VERSION 5.8 ;
BUSBITCHARS "[]" ;
DIVIDERCHAR "/" ;
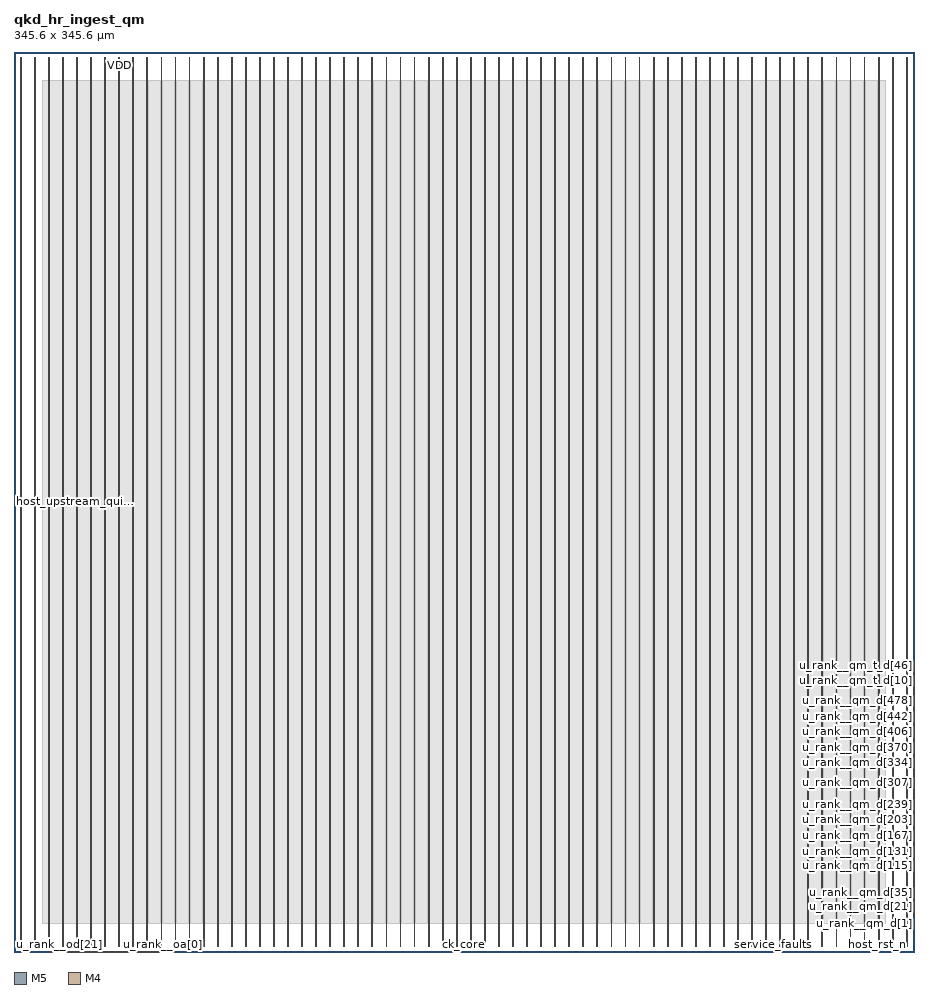
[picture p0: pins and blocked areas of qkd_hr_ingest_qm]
MACRO qkd_hr_ingest_qm
  CLASS BLOCK ;
  ORIGIN 0 0 ;
  FOREIGN qkd_hr_ingest_qm 0 0 ;
  SIZE 345.6 BY 345.6 ;
  SYMMETRY X Y ;
  PIN ck_core
    DIRECTION INPUT ;
    USE CLOCK ;
    PORT
      LAYER M5 ;
        RECT 172.800 0.000 172.824 0.192 ;
    END
  END ck_core
  PIN ck_host
    DIRECTION INPUT ;
    USE CLOCK ;
    PORT
      LAYER M5 ;
        RECT 177.120 0.000 177.144 0.192 ;
    END
  END ck_host
  PIN ck_ingest
    DIRECTION INPUT ;
    USE CLOCK ;
    PORT
      LAYER M5 ;
        RECT 181.440 0.000 181.464 0.192 ;
    END
  END ck_ingest
  PIN host_rst_n
    DIRECTION INPUT ;
    USE SIGNAL ;
    PORT
      LAYER M5 ;
        RECT 331.680 0.000 331.704 0.192 ;
    END
  END host_rst_n
  PIN host_upstream_quiet_core
    DIRECTION OUTPUT ;
    USE SIGNAL ;
    PORT
      LAYER M4 ;
        RECT 0.000 172.800 0.192 172.824 ;
    END
  END host_upstream_quiet_core
  PIN host_upstream_quiet_host
    DIRECTION OUTPUT ;
    USE SIGNAL ;
    PORT
      LAYER M4 ;
        RECT 0.000 172.944 0.192 172.968 ;
    END
  END host_upstream_quiet_host
  PIN host_upstream_quiet_ingest
    DIRECTION OUTPUT ;
    USE SIGNAL ;
    PORT
      LAYER M4 ;
        RECT 0.000 173.136 0.192 173.160 ;
    END
  END host_upstream_quiet_ingest
  PIN service_faults
    DIRECTION OUTPUT ;
    USE SIGNAL ;
    PORT
      LAYER M5 ;
        RECT 291.552 0.000 291.576 0.192 ;
    END
  END service_faults
  PIN u_rank__oa[0]
    DIRECTION OUTPUT ;
    USE SIGNAL ;
    PORT
      LAYER M5 ;
        RECT 57.072 0.000 57.096 0.192 ;
    END
  END u_rank__oa[0]
  PIN u_rank__oa[10]
    DIRECTION OUTPUT ;
    USE SIGNAL ;
    PORT
      LAYER M5 ;
        RECT 58.752 0.000 58.776 0.192 ;
    END
  END u_rank__oa[10]
  PIN u_rank__oa[11]
    DIRECTION OUTPUT ;
    USE SIGNAL ;
    PORT
      LAYER M5 ;
        RECT 58.896 0.000 58.920 0.192 ;
    END
  END u_rank__oa[11]
  PIN u_rank__oa[12]
    DIRECTION OUTPUT ;
    USE SIGNAL ;
    PORT
      LAYER M5 ;
        RECT 59.040 0.000 59.064 0.192 ;
    END
  END u_rank__oa[12]
  PIN u_rank__oa[13]
    DIRECTION OUTPUT ;
    USE SIGNAL ;
    PORT
      LAYER M5 ;
        RECT 59.232 0.000 59.256 0.192 ;
    END
  END u_rank__oa[13]
  PIN u_rank__oa[14]
    DIRECTION OUTPUT ;
    USE SIGNAL ;
    PORT
      LAYER M5 ;
        RECT 59.376 0.000 59.400 0.192 ;
    END
  END u_rank__oa[14]
  PIN u_rank__oa[15]
    DIRECTION OUTPUT ;
    USE SIGNAL ;
    PORT
      LAYER M5 ;
        RECT 59.568 0.000 59.592 0.192 ;
    END
  END u_rank__oa[15]
  PIN u_rank__oa[16]
    DIRECTION OUTPUT ;
    USE SIGNAL ;
    PORT
      LAYER M5 ;
        RECT 59.712 0.000 59.736 0.192 ;
    END
  END u_rank__oa[16]
  PIN u_rank__oa[17]
    DIRECTION OUTPUT ;
    USE SIGNAL ;
    PORT
      LAYER M5 ;
        RECT 59.904 0.000 59.928 0.192 ;
    END
  END u_rank__oa[17]
  PIN u_rank__oa[18]
    DIRECTION OUTPUT ;
    USE SIGNAL ;
    PORT
      LAYER M5 ;
        RECT 60.048 0.000 60.072 0.192 ;
    END
  END u_rank__oa[18]
  PIN u_rank__oa[19]
    DIRECTION OUTPUT ;
    USE SIGNAL ;
    PORT
      LAYER M5 ;
        RECT 60.240 0.000 60.264 0.192 ;
    END
  END u_rank__oa[19]
  PIN u_rank__oa[1]
    DIRECTION OUTPUT ;
    USE SIGNAL ;
    PORT
      LAYER M5 ;
        RECT 57.216 0.000 57.240 0.192 ;
    END
  END u_rank__oa[1]
  PIN u_rank__oa[20]
    DIRECTION OUTPUT ;
    USE SIGNAL ;
    PORT
      LAYER M5 ;
        RECT 60.384 0.000 60.408 0.192 ;
    END
  END u_rank__oa[20]
  PIN u_rank__oa[21]
    DIRECTION OUTPUT ;
    USE SIGNAL ;
    PORT
      LAYER M5 ;
        RECT 60.576 0.000 60.600 0.192 ;
    END
  END u_rank__oa[21]
  PIN u_rank__oa[22]
    DIRECTION OUTPUT ;
    USE SIGNAL ;
    PORT
      LAYER M5 ;
        RECT 60.720 0.000 60.744 0.192 ;
    END
  END u_rank__oa[22]
  PIN u_rank__oa[23]
    DIRECTION OUTPUT ;
    USE SIGNAL ;
    PORT
      LAYER M5 ;
        RECT 60.912 0.000 60.936 0.192 ;
    END
  END u_rank__oa[23]
  PIN u_rank__oa[24]
    DIRECTION OUTPUT ;
    USE SIGNAL ;
    PORT
      LAYER M5 ;
        RECT 61.056 0.000 61.080 0.192 ;
    END
  END u_rank__oa[24]
  PIN u_rank__oa[25]
    DIRECTION OUTPUT ;
    USE SIGNAL ;
    PORT
      LAYER M5 ;
        RECT 61.248 0.000 61.272 0.192 ;
    END
  END u_rank__oa[25]
  PIN u_rank__oa[26]
    DIRECTION OUTPUT ;
    USE SIGNAL ;
    PORT
      LAYER M5 ;
        RECT 61.392 0.000 61.416 0.192 ;
    END
  END u_rank__oa[26]
  PIN u_rank__oa[27]
    DIRECTION OUTPUT ;
    USE SIGNAL ;
    PORT
      LAYER M5 ;
        RECT 61.584 0.000 61.608 0.192 ;
    END
  END u_rank__oa[27]
  PIN u_rank__oa[28]
    DIRECTION OUTPUT ;
    USE SIGNAL ;
    PORT
      LAYER M5 ;
        RECT 62.304 0.000 62.328 0.192 ;
    END
  END u_rank__oa[28]
  PIN u_rank__oa[29]
    DIRECTION OUTPUT ;
    USE SIGNAL ;
    PORT
      LAYER M5 ;
        RECT 62.352 0.000 62.376 0.192 ;
    END
  END u_rank__oa[29]
  PIN u_rank__oa[2]
    DIRECTION OUTPUT ;
    USE SIGNAL ;
    PORT
      LAYER M5 ;
        RECT 57.408 0.000 57.432 0.192 ;
    END
  END u_rank__oa[2]
  PIN u_rank__oa[30]
    DIRECTION OUTPUT ;
    USE SIGNAL ;
    PORT
      LAYER M5 ;
        RECT 62.400 0.000 62.424 0.192 ;
    END
  END u_rank__oa[30]
  PIN u_rank__oa[31]
    DIRECTION OUTPUT ;
    USE SIGNAL ;
    PORT
      LAYER M5 ;
        RECT 62.448 0.000 62.472 0.192 ;
    END
  END u_rank__oa[31]
  PIN u_rank__oa[3]
    DIRECTION OUTPUT ;
    USE SIGNAL ;
    PORT
      LAYER M5 ;
        RECT 57.552 0.000 57.576 0.192 ;
    END
  END u_rank__oa[3]
  PIN u_rank__oa[4]
    DIRECTION OUTPUT ;
    USE SIGNAL ;
    PORT
      LAYER M5 ;
        RECT 57.744 0.000 57.768 0.192 ;
    END
  END u_rank__oa[4]
  PIN u_rank__oa[5]
    DIRECTION OUTPUT ;
    USE SIGNAL ;
    PORT
      LAYER M5 ;
        RECT 57.888 0.000 57.912 0.192 ;
    END
  END u_rank__oa[5]
  PIN u_rank__oa[6]
    DIRECTION OUTPUT ;
    USE SIGNAL ;
    PORT
      LAYER M5 ;
        RECT 58.080 0.000 58.104 0.192 ;
    END
  END u_rank__oa[6]
  PIN u_rank__oa[7]
    DIRECTION OUTPUT ;
    USE SIGNAL ;
    PORT
      LAYER M5 ;
        RECT 58.224 0.000 58.248 0.192 ;
    END
  END u_rank__oa[7]
  PIN u_rank__oa[8]
    DIRECTION OUTPUT ;
    USE SIGNAL ;
    PORT
      LAYER M5 ;
        RECT 58.416 0.000 58.440 0.192 ;
    END
  END u_rank__oa[8]
  PIN u_rank__oa[9]
    DIRECTION OUTPUT ;
    USE SIGNAL ;
    PORT
      LAYER M5 ;
        RECT 58.560 0.000 58.584 0.192 ;
    END
  END u_rank__oa[9]
  PIN u_rank__ocr
    DIRECTION INPUT ;
    USE SIGNAL ;
    PORT
      LAYER M5 ;
        RECT 56.928 0.000 56.952 0.192 ;
    END
  END u_rank__ocr
  PIN u_rank__od[0]
    DIRECTION OUTPUT ;
    USE SIGNAL ;
    PORT
      LAYER M5 ;
        RECT 13.872 0.000 13.896 0.192 ;
    END
  END u_rank__od[0]
  PIN u_rank__od[100]
    DIRECTION OUTPUT ;
    USE SIGNAL ;
    PORT
      LAYER M5 ;
        RECT 30.576 0.000 30.600 0.192 ;
    END
  END u_rank__od[100]
  PIN u_rank__od[101]
    DIRECTION OUTPUT ;
    USE SIGNAL ;
    PORT
      LAYER M5 ;
        RECT 30.720 0.000 30.744 0.192 ;
    END
  END u_rank__od[101]
  PIN u_rank__od[102]
    DIRECTION OUTPUT ;
    USE SIGNAL ;
    PORT
      LAYER M5 ;
        RECT 30.912 0.000 30.936 0.192 ;
    END
  END u_rank__od[102]
  PIN u_rank__od[103]
    DIRECTION OUTPUT ;
    USE SIGNAL ;
    PORT
      LAYER M5 ;
        RECT 31.056 0.000 31.080 0.192 ;
    END
  END u_rank__od[103]
  PIN u_rank__od[104]
    DIRECTION OUTPUT ;
    USE SIGNAL ;
    PORT
      LAYER M5 ;
        RECT 31.248 0.000 31.272 0.192 ;
    END
  END u_rank__od[104]
  PIN u_rank__od[105]
    DIRECTION OUTPUT ;
    USE SIGNAL ;
    PORT
      LAYER M5 ;
        RECT 31.392 0.000 31.416 0.192 ;
    END
  END u_rank__od[105]
  PIN u_rank__od[106]
    DIRECTION OUTPUT ;
    USE SIGNAL ;
    PORT
      LAYER M5 ;
        RECT 31.584 0.000 31.608 0.192 ;
    END
  END u_rank__od[106]
  PIN u_rank__od[107]
    DIRECTION OUTPUT ;
    USE SIGNAL ;
    PORT
      LAYER M5 ;
        RECT 31.728 0.000 31.752 0.192 ;
    END
  END u_rank__od[107]
  PIN u_rank__od[108]
    DIRECTION OUTPUT ;
    USE SIGNAL ;
    PORT
      LAYER M5 ;
        RECT 31.872 0.000 31.896 0.192 ;
    END
  END u_rank__od[108]
  PIN u_rank__od[109]
    DIRECTION OUTPUT ;
    USE SIGNAL ;
    PORT
      LAYER M5 ;
        RECT 32.064 0.000 32.088 0.192 ;
    END
  END u_rank__od[109]
  PIN u_rank__od[10]
    DIRECTION OUTPUT ;
    USE SIGNAL ;
    PORT
      LAYER M5 ;
        RECT 15.552 0.000 15.576 0.192 ;
    END
  END u_rank__od[10]
  PIN u_rank__od[110]
    DIRECTION OUTPUT ;
    USE SIGNAL ;
    PORT
      LAYER M5 ;
        RECT 32.208 0.000 32.232 0.192 ;
    END
  END u_rank__od[110]
  PIN u_rank__od[111]
    DIRECTION OUTPUT ;
    USE SIGNAL ;
    PORT
      LAYER M5 ;
        RECT 32.400 0.000 32.424 0.192 ;
    END
  END u_rank__od[111]
  PIN u_rank__od[112]
    DIRECTION OUTPUT ;
    USE SIGNAL ;
    PORT
      LAYER M5 ;
        RECT 32.544 0.000 32.568 0.192 ;
    END
  END u_rank__od[112]
  PIN u_rank__od[113]
    DIRECTION OUTPUT ;
    USE SIGNAL ;
    PORT
      LAYER M5 ;
        RECT 32.736 0.000 32.760 0.192 ;
    END
  END u_rank__od[113]
  PIN u_rank__od[114]
    DIRECTION OUTPUT ;
    USE SIGNAL ;
    PORT
      LAYER M5 ;
        RECT 32.880 0.000 32.904 0.192 ;
    END
  END u_rank__od[114]
  PIN u_rank__od[115]
    DIRECTION OUTPUT ;
    USE SIGNAL ;
    PORT
      LAYER M5 ;
        RECT 33.072 0.000 33.096 0.192 ;
    END
  END u_rank__od[115]
  PIN u_rank__od[116]
    DIRECTION OUTPUT ;
    USE SIGNAL ;
    PORT
      LAYER M5 ;
        RECT 33.216 0.000 33.240 0.192 ;
    END
  END u_rank__od[116]
  PIN u_rank__od[117]
    DIRECTION OUTPUT ;
    USE SIGNAL ;
    PORT
      LAYER M5 ;
        RECT 33.408 0.000 33.432 0.192 ;
    END
  END u_rank__od[117]
  PIN u_rank__od[118]
    DIRECTION OUTPUT ;
    USE SIGNAL ;
    PORT
      LAYER M5 ;
        RECT 33.552 0.000 33.576 0.192 ;
    END
  END u_rank__od[118]
  PIN u_rank__od[119]
    DIRECTION OUTPUT ;
    USE SIGNAL ;
    PORT
      LAYER M5 ;
        RECT 33.744 0.000 33.768 0.192 ;
    END
  END u_rank__od[119]
  PIN u_rank__od[11]
    DIRECTION OUTPUT ;
    USE SIGNAL ;
    PORT
      LAYER M5 ;
        RECT 15.744 0.000 15.768 0.192 ;
    END
  END u_rank__od[11]
  PIN u_rank__od[120]
    DIRECTION OUTPUT ;
    USE SIGNAL ;
    PORT
      LAYER M5 ;
        RECT 33.888 0.000 33.912 0.192 ;
    END
  END u_rank__od[120]
  PIN u_rank__od[121]
    DIRECTION OUTPUT ;
    USE SIGNAL ;
    PORT
      LAYER M5 ;
        RECT 34.080 0.000 34.104 0.192 ;
    END
  END u_rank__od[121]
  PIN u_rank__od[122]
    DIRECTION OUTPUT ;
    USE SIGNAL ;
    PORT
      LAYER M5 ;
        RECT 34.224 0.000 34.248 0.192 ;
    END
  END u_rank__od[122]
  PIN u_rank__od[123]
    DIRECTION OUTPUT ;
    USE SIGNAL ;
    PORT
      LAYER M5 ;
        RECT 34.416 0.000 34.440 0.192 ;
    END
  END u_rank__od[123]
  PIN u_rank__od[124]
    DIRECTION OUTPUT ;
    USE SIGNAL ;
    PORT
      LAYER M5 ;
        RECT 34.560 0.000 34.584 0.192 ;
    END
  END u_rank__od[124]
  PIN u_rank__od[125]
    DIRECTION OUTPUT ;
    USE SIGNAL ;
    PORT
      LAYER M5 ;
        RECT 35.328 0.000 35.352 0.192 ;
    END
  END u_rank__od[125]
  PIN u_rank__od[126]
    DIRECTION OUTPUT ;
    USE SIGNAL ;
    PORT
      LAYER M5 ;
        RECT 35.376 0.000 35.400 0.192 ;
    END
  END u_rank__od[126]
  PIN u_rank__od[127]
    DIRECTION OUTPUT ;
    USE SIGNAL ;
    PORT
      LAYER M5 ;
        RECT 35.424 0.000 35.448 0.192 ;
    END
  END u_rank__od[127]
  PIN u_rank__od[128]
    DIRECTION OUTPUT ;
    USE SIGNAL ;
    PORT
      LAYER M5 ;
        RECT 35.472 0.000 35.496 0.192 ;
    END
  END u_rank__od[128]
  PIN u_rank__od[129]
    DIRECTION OUTPUT ;
    USE SIGNAL ;
    PORT
      LAYER M5 ;
        RECT 35.520 0.000 35.544 0.192 ;
    END
  END u_rank__od[129]
  PIN u_rank__od[12]
    DIRECTION OUTPUT ;
    USE SIGNAL ;
    PORT
      LAYER M5 ;
        RECT 15.888 0.000 15.912 0.192 ;
    END
  END u_rank__od[12]
  PIN u_rank__od[130]
    DIRECTION OUTPUT ;
    USE SIGNAL ;
    PORT
      LAYER M5 ;
        RECT 35.568 0.000 35.592 0.192 ;
    END
  END u_rank__od[130]
  PIN u_rank__od[131]
    DIRECTION OUTPUT ;
    USE SIGNAL ;
    PORT
      LAYER M5 ;
        RECT 35.712 0.000 35.736 0.192 ;
    END
  END u_rank__od[131]
  PIN u_rank__od[132]
    DIRECTION OUTPUT ;
    USE SIGNAL ;
    PORT
      LAYER M5 ;
        RECT 35.904 0.000 35.928 0.192 ;
    END
  END u_rank__od[132]
  PIN u_rank__od[133]
    DIRECTION OUTPUT ;
    USE SIGNAL ;
    PORT
      LAYER M5 ;
        RECT 36.048 0.000 36.072 0.192 ;
    END
  END u_rank__od[133]
  PIN u_rank__od[134]
    DIRECTION OUTPUT ;
    USE SIGNAL ;
    PORT
      LAYER M5 ;
        RECT 36.240 0.000 36.264 0.192 ;
    END
  END u_rank__od[134]
  PIN u_rank__od[135]
    DIRECTION OUTPUT ;
    USE SIGNAL ;
    PORT
      LAYER M5 ;
        RECT 36.384 0.000 36.408 0.192 ;
    END
  END u_rank__od[135]
  PIN u_rank__od[136]
    DIRECTION OUTPUT ;
    USE SIGNAL ;
    PORT
      LAYER M5 ;
        RECT 36.576 0.000 36.600 0.192 ;
    END
  END u_rank__od[136]
  PIN u_rank__od[137]
    DIRECTION OUTPUT ;
    USE SIGNAL ;
    PORT
      LAYER M5 ;
        RECT 36.720 0.000 36.744 0.192 ;
    END
  END u_rank__od[137]
  PIN u_rank__od[138]
    DIRECTION OUTPUT ;
    USE SIGNAL ;
    PORT
      LAYER M5 ;
        RECT 36.912 0.000 36.936 0.192 ;
    END
  END u_rank__od[138]
  PIN u_rank__od[139]
    DIRECTION OUTPUT ;
    USE SIGNAL ;
    PORT
      LAYER M5 ;
        RECT 37.056 0.000 37.080 0.192 ;
    END
  END u_rank__od[139]
  PIN u_rank__od[13]
    DIRECTION OUTPUT ;
    USE SIGNAL ;
    PORT
      LAYER M5 ;
        RECT 16.080 0.000 16.104 0.192 ;
    END
  END u_rank__od[13]
  PIN u_rank__od[140]
    DIRECTION OUTPUT ;
    USE SIGNAL ;
    PORT
      LAYER M5 ;
        RECT 37.248 0.000 37.272 0.192 ;
    END
  END u_rank__od[140]
  PIN u_rank__od[141]
    DIRECTION OUTPUT ;
    USE SIGNAL ;
    PORT
      LAYER M5 ;
        RECT 37.392 0.000 37.416 0.192 ;
    END
  END u_rank__od[141]
  PIN u_rank__od[142]
    DIRECTION OUTPUT ;
    USE SIGNAL ;
    PORT
      LAYER M5 ;
        RECT 37.584 0.000 37.608 0.192 ;
    END
  END u_rank__od[142]
  PIN u_rank__od[143]
    DIRECTION OUTPUT ;
    USE SIGNAL ;
    PORT
      LAYER M5 ;
        RECT 37.728 0.000 37.752 0.192 ;
    END
  END u_rank__od[143]
  PIN u_rank__od[144]
    DIRECTION OUTPUT ;
    USE SIGNAL ;
    PORT
      LAYER M5 ;
        RECT 37.872 0.000 37.896 0.192 ;
    END
  END u_rank__od[144]
  PIN u_rank__od[145]
    DIRECTION OUTPUT ;
    USE SIGNAL ;
    PORT
      LAYER M5 ;
        RECT 38.064 0.000 38.088 0.192 ;
    END
  END u_rank__od[145]
  PIN u_rank__od[146]
    DIRECTION OUTPUT ;
    USE SIGNAL ;
    PORT
      LAYER M5 ;
        RECT 38.208 0.000 38.232 0.192 ;
    END
  END u_rank__od[146]
  PIN u_rank__od[147]
    DIRECTION OUTPUT ;
    USE SIGNAL ;
    PORT
      LAYER M5 ;
        RECT 38.400 0.000 38.424 0.192 ;
    END
  END u_rank__od[147]
  PIN u_rank__od[148]
    DIRECTION OUTPUT ;
    USE SIGNAL ;
    PORT
      LAYER M5 ;
        RECT 38.544 0.000 38.568 0.192 ;
    END
  END u_rank__od[148]
  PIN u_rank__od[149]
    DIRECTION OUTPUT ;
    USE SIGNAL ;
    PORT
      LAYER M5 ;
        RECT 38.736 0.000 38.760 0.192 ;
    END
  END u_rank__od[149]
  PIN u_rank__od[14]
    DIRECTION OUTPUT ;
    USE SIGNAL ;
    PORT
      LAYER M5 ;
        RECT 16.224 0.000 16.248 0.192 ;
    END
  END u_rank__od[14]
  PIN u_rank__od[150]
    DIRECTION OUTPUT ;
    USE SIGNAL ;
    PORT
      LAYER M5 ;
        RECT 38.880 0.000 38.904 0.192 ;
    END
  END u_rank__od[150]
  PIN u_rank__od[151]
    DIRECTION OUTPUT ;
    USE SIGNAL ;
    PORT
      LAYER M5 ;
        RECT 39.072 0.000 39.096 0.192 ;
    END
  END u_rank__od[151]
  PIN u_rank__od[152]
    DIRECTION OUTPUT ;
    USE SIGNAL ;
    PORT
      LAYER M5 ;
        RECT 39.216 0.000 39.240 0.192 ;
    END
  END u_rank__od[152]
  PIN u_rank__od[153]
    DIRECTION OUTPUT ;
    USE SIGNAL ;
    PORT
      LAYER M5 ;
        RECT 39.408 0.000 39.432 0.192 ;
    END
  END u_rank__od[153]
  PIN u_rank__od[154]
    DIRECTION OUTPUT ;
    USE SIGNAL ;
    PORT
      LAYER M5 ;
        RECT 39.552 0.000 39.576 0.192 ;
    END
  END u_rank__od[154]
  PIN u_rank__od[155]
    DIRECTION OUTPUT ;
    USE SIGNAL ;
    PORT
      LAYER M5 ;
        RECT 39.744 0.000 39.768 0.192 ;
    END
  END u_rank__od[155]
  PIN u_rank__od[156]
    DIRECTION OUTPUT ;
    USE SIGNAL ;
    PORT
      LAYER M5 ;
        RECT 39.888 0.000 39.912 0.192 ;
    END
  END u_rank__od[156]
  PIN u_rank__od[157]
    DIRECTION OUTPUT ;
    USE SIGNAL ;
    PORT
      LAYER M5 ;
        RECT 40.080 0.000 40.104 0.192 ;
    END
  END u_rank__od[157]
  PIN u_rank__od[158]
    DIRECTION OUTPUT ;
    USE SIGNAL ;
    PORT
      LAYER M5 ;
        RECT 40.704 0.000 40.728 0.192 ;
    END
  END u_rank__od[158]
  PIN u_rank__od[159]
    DIRECTION OUTPUT ;
    USE SIGNAL ;
    PORT
      LAYER M5 ;
        RECT 40.752 0.000 40.776 0.192 ;
    END
  END u_rank__od[159]
  PIN u_rank__od[15]
    DIRECTION OUTPUT ;
    USE SIGNAL ;
    PORT
      LAYER M5 ;
        RECT 16.416 0.000 16.440 0.192 ;
    END
  END u_rank__od[15]
  PIN u_rank__od[160]
    DIRECTION OUTPUT ;
    USE SIGNAL ;
    PORT
      LAYER M5 ;
        RECT 40.800 0.000 40.824 0.192 ;
    END
  END u_rank__od[160]
  PIN u_rank__od[161]
    DIRECTION OUTPUT ;
    USE SIGNAL ;
    PORT
      LAYER M5 ;
        RECT 40.848 0.000 40.872 0.192 ;
    END
  END u_rank__od[161]
  PIN u_rank__od[162]
    DIRECTION OUTPUT ;
    USE SIGNAL ;
    PORT
      LAYER M5 ;
        RECT 40.896 0.000 40.920 0.192 ;
    END
  END u_rank__od[162]
  PIN u_rank__od[163]
    DIRECTION OUTPUT ;
    USE SIGNAL ;
    PORT
      LAYER M5 ;
        RECT 41.040 0.000 41.064 0.192 ;
    END
  END u_rank__od[163]
  PIN u_rank__od[164]
    DIRECTION OUTPUT ;
    USE SIGNAL ;
    PORT
      LAYER M5 ;
        RECT 41.232 0.000 41.256 0.192 ;
    END
  END u_rank__od[164]
  PIN u_rank__od[165]
    DIRECTION OUTPUT ;
    USE SIGNAL ;
    PORT
      LAYER M5 ;
        RECT 41.376 0.000 41.400 0.192 ;
    END
  END u_rank__od[165]
  PIN u_rank__od[166]
    DIRECTION OUTPUT ;
    USE SIGNAL ;
    PORT
      LAYER M5 ;
        RECT 41.568 0.000 41.592 0.192 ;
    END
  END u_rank__od[166]
  PIN u_rank__od[167]
    DIRECTION OUTPUT ;
    USE SIGNAL ;
    PORT
      LAYER M5 ;
        RECT 41.712 0.000 41.736 0.192 ;
    END
  END u_rank__od[167]
  PIN u_rank__od[168]
    DIRECTION OUTPUT ;
    USE SIGNAL ;
    PORT
      LAYER M5 ;
        RECT 41.904 0.000 41.928 0.192 ;
    END
  END u_rank__od[168]
  PIN u_rank__od[169]
    DIRECTION OUTPUT ;
    USE SIGNAL ;
    PORT
      LAYER M5 ;
        RECT 42.048 0.000 42.072 0.192 ;
    END
  END u_rank__od[169]
  PIN u_rank__od[16]
    DIRECTION OUTPUT ;
    USE SIGNAL ;
    PORT
      LAYER M5 ;
        RECT 16.560 0.000 16.584 0.192 ;
    END
  END u_rank__od[16]
  PIN u_rank__od[170]
    DIRECTION OUTPUT ;
    USE SIGNAL ;
    PORT
      LAYER M5 ;
        RECT 42.240 0.000 42.264 0.192 ;
    END
  END u_rank__od[170]
  PIN u_rank__od[171]
    DIRECTION OUTPUT ;
    USE SIGNAL ;
    PORT
      LAYER M5 ;
        RECT 42.384 0.000 42.408 0.192 ;
    END
  END u_rank__od[171]
  PIN u_rank__od[172]
    DIRECTION OUTPUT ;
    USE SIGNAL ;
    PORT
      LAYER M5 ;
        RECT 42.576 0.000 42.600 0.192 ;
    END
  END u_rank__od[172]
  PIN u_rank__od[173]
    DIRECTION OUTPUT ;
    USE SIGNAL ;
    PORT
      LAYER M5 ;
        RECT 42.720 0.000 42.744 0.192 ;
    END
  END u_rank__od[173]
  PIN u_rank__od[174]
    DIRECTION OUTPUT ;
    USE SIGNAL ;
    PORT
      LAYER M5 ;
        RECT 42.912 0.000 42.936 0.192 ;
    END
  END u_rank__od[174]
  PIN u_rank__od[175]
    DIRECTION OUTPUT ;
    USE SIGNAL ;
    PORT
      LAYER M5 ;
        RECT 43.056 0.000 43.080 0.192 ;
    END
  END u_rank__od[175]
  PIN u_rank__od[176]
    DIRECTION OUTPUT ;
    USE SIGNAL ;
    PORT
      LAYER M5 ;
        RECT 43.248 0.000 43.272 0.192 ;
    END
  END u_rank__od[176]
  PIN u_rank__od[177]
    DIRECTION OUTPUT ;
    USE SIGNAL ;
    PORT
      LAYER M5 ;
        RECT 43.392 0.000 43.416 0.192 ;
    END
  END u_rank__od[177]
  PIN u_rank__od[178]
    DIRECTION OUTPUT ;
    USE SIGNAL ;
    PORT
      LAYER M5 ;
        RECT 43.584 0.000 43.608 0.192 ;
    END
  END u_rank__od[178]
  PIN u_rank__od[179]
    DIRECTION OUTPUT ;
    USE SIGNAL ;
    PORT
      LAYER M5 ;
        RECT 43.728 0.000 43.752 0.192 ;
    END
  END u_rank__od[179]
  PIN u_rank__od[17]
    DIRECTION OUTPUT ;
    USE SIGNAL ;
    PORT
      LAYER M5 ;
        RECT 16.752 0.000 16.776 0.192 ;
    END
  END u_rank__od[17]
  PIN u_rank__od[180]
    DIRECTION OUTPUT ;
    USE SIGNAL ;
    PORT
      LAYER M5 ;
        RECT 43.872 0.000 43.896 0.192 ;
    END
  END u_rank__od[180]
  PIN u_rank__od[181]
    DIRECTION OUTPUT ;
    USE SIGNAL ;
    PORT
      LAYER M5 ;
        RECT 44.064 0.000 44.088 0.192 ;
    END
  END u_rank__od[181]
  PIN u_rank__od[182]
    DIRECTION OUTPUT ;
    USE SIGNAL ;
    PORT
      LAYER M5 ;
        RECT 44.208 0.000 44.232 0.192 ;
    END
  END u_rank__od[182]
  PIN u_rank__od[183]
    DIRECTION OUTPUT ;
    USE SIGNAL ;
    PORT
      LAYER M5 ;
        RECT 44.400 0.000 44.424 0.192 ;
    END
  END u_rank__od[183]
  PIN u_rank__od[184]
    DIRECTION OUTPUT ;
    USE SIGNAL ;
    PORT
      LAYER M5 ;
        RECT 44.544 0.000 44.568 0.192 ;
    END
  END u_rank__od[184]
  PIN u_rank__od[185]
    DIRECTION OUTPUT ;
    USE SIGNAL ;
    PORT
      LAYER M5 ;
        RECT 44.736 0.000 44.760 0.192 ;
    END
  END u_rank__od[185]
  PIN u_rank__od[186]
    DIRECTION OUTPUT ;
    USE SIGNAL ;
    PORT
      LAYER M5 ;
        RECT 44.880 0.000 44.904 0.192 ;
    END
  END u_rank__od[186]
  PIN u_rank__od[187]
    DIRECTION OUTPUT ;
    USE SIGNAL ;
    PORT
      LAYER M5 ;
        RECT 45.072 0.000 45.096 0.192 ;
    END
  END u_rank__od[187]
  PIN u_rank__od[188]
    DIRECTION OUTPUT ;
    USE SIGNAL ;
    PORT
      LAYER M5 ;
        RECT 45.216 0.000 45.240 0.192 ;
    END
  END u_rank__od[188]
  PIN u_rank__od[189]
    DIRECTION OUTPUT ;
    USE SIGNAL ;
    PORT
      LAYER M5 ;
        RECT 45.408 0.000 45.432 0.192 ;
    END
  END u_rank__od[189]
  PIN u_rank__od[18]
    DIRECTION OUTPUT ;
    USE SIGNAL ;
    PORT
      LAYER M5 ;
        RECT 16.896 0.000 16.920 0.192 ;
    END
  END u_rank__od[18]
  PIN u_rank__od[190]
    DIRECTION OUTPUT ;
    USE SIGNAL ;
    PORT
      LAYER M5 ;
        RECT 46.128 0.000 46.152 0.192 ;
    END
  END u_rank__od[190]
  PIN u_rank__od[191]
    DIRECTION OUTPUT ;
    USE SIGNAL ;
    PORT
      LAYER M5 ;
        RECT 46.176 0.000 46.200 0.192 ;
    END
  END u_rank__od[191]
  PIN u_rank__od[192]
    DIRECTION OUTPUT ;
    USE SIGNAL ;
    PORT
      LAYER M5 ;
        RECT 46.224 0.000 46.248 0.192 ;
    END
  END u_rank__od[192]
  PIN u_rank__od[193]
    DIRECTION OUTPUT ;
    USE SIGNAL ;
    PORT
      LAYER M5 ;
        RECT 46.272 0.000 46.296 0.192 ;
    END
  END u_rank__od[193]
  PIN u_rank__od[194]
    DIRECTION OUTPUT ;
    USE SIGNAL ;
    PORT
      LAYER M5 ;
        RECT 46.320 0.000 46.344 0.192 ;
    END
  END u_rank__od[194]
  PIN u_rank__od[195]
    DIRECTION OUTPUT ;
    USE SIGNAL ;
    PORT
      LAYER M5 ;
        RECT 46.416 0.000 46.440 0.192 ;
    END
  END u_rank__od[195]
  PIN u_rank__od[196]
    DIRECTION OUTPUT ;
    USE SIGNAL ;
    PORT
      LAYER M5 ;
        RECT 46.560 0.000 46.584 0.192 ;
    END
  END u_rank__od[196]
  PIN u_rank__od[197]
    DIRECTION OUTPUT ;
    USE SIGNAL ;
    PORT
      LAYER M5 ;
        RECT 46.752 0.000 46.776 0.192 ;
    END
  END u_rank__od[197]
  PIN u_rank__od[198]
    DIRECTION OUTPUT ;
    USE SIGNAL ;
    PORT
      LAYER M5 ;
        RECT 46.896 0.000 46.920 0.192 ;
    END
  END u_rank__od[198]
  PIN u_rank__od[199]
    DIRECTION OUTPUT ;
    USE SIGNAL ;
    PORT
      LAYER M5 ;
        RECT 47.040 0.000 47.064 0.192 ;
    END
  END u_rank__od[199]
  PIN u_rank__od[19]
    DIRECTION OUTPUT ;
    USE SIGNAL ;
    PORT
      LAYER M5 ;
        RECT 17.040 0.000 17.064 0.192 ;
    END
  END u_rank__od[19]
  PIN u_rank__od[1]
    DIRECTION OUTPUT ;
    USE SIGNAL ;
    PORT
      LAYER M5 ;
        RECT 14.064 0.000 14.088 0.192 ;
    END
  END u_rank__od[1]
  PIN u_rank__od[200]
    DIRECTION OUTPUT ;
    USE SIGNAL ;
    PORT
      LAYER M5 ;
        RECT 47.232 0.000 47.256 0.192 ;
    END
  END u_rank__od[200]
  PIN u_rank__od[201]
    DIRECTION OUTPUT ;
    USE SIGNAL ;
    PORT
      LAYER M5 ;
        RECT 47.376 0.000 47.400 0.192 ;
    END
  END u_rank__od[201]
  PIN u_rank__od[202]
    DIRECTION OUTPUT ;
    USE SIGNAL ;
    PORT
      LAYER M5 ;
        RECT 47.568 0.000 47.592 0.192 ;
    END
  END u_rank__od[202]
  PIN u_rank__od[203]
    DIRECTION OUTPUT ;
    USE SIGNAL ;
    PORT
      LAYER M5 ;
        RECT 47.712 0.000 47.736 0.192 ;
    END
  END u_rank__od[203]
  PIN u_rank__od[204]
    DIRECTION OUTPUT ;
    USE SIGNAL ;
    PORT
      LAYER M5 ;
        RECT 47.904 0.000 47.928 0.192 ;
    END
  END u_rank__od[204]
  PIN u_rank__od[205]
    DIRECTION OUTPUT ;
    USE SIGNAL ;
    PORT
      LAYER M5 ;
        RECT 48.048 0.000 48.072 0.192 ;
    END
  END u_rank__od[205]
  PIN u_rank__od[206]
    DIRECTION OUTPUT ;
    USE SIGNAL ;
    PORT
      LAYER M5 ;
        RECT 48.240 0.000 48.264 0.192 ;
    END
  END u_rank__od[206]
  PIN u_rank__od[207]
    DIRECTION OUTPUT ;
    USE SIGNAL ;
    PORT
      LAYER M5 ;
        RECT 48.384 0.000 48.408 0.192 ;
    END
  END u_rank__od[207]
  PIN u_rank__od[208]
    DIRECTION OUTPUT ;
    USE SIGNAL ;
    PORT
      LAYER M5 ;
        RECT 48.576 0.000 48.600 0.192 ;
    END
  END u_rank__od[208]
  PIN u_rank__od[209]
    DIRECTION OUTPUT ;
    USE SIGNAL ;
    PORT
      LAYER M5 ;
        RECT 48.720 0.000 48.744 0.192 ;
    END
  END u_rank__od[209]
  PIN u_rank__od[20]
    DIRECTION OUTPUT ;
    USE SIGNAL ;
    PORT
      LAYER M5 ;
        RECT 17.232 0.000 17.256 0.192 ;
    END
  END u_rank__od[20]
  PIN u_rank__od[210]
    DIRECTION OUTPUT ;
    USE SIGNAL ;
    PORT
      LAYER M5 ;
        RECT 48.912 0.000 48.936 0.192 ;
    END
  END u_rank__od[210]
  PIN u_rank__od[211]
    DIRECTION OUTPUT ;
    USE SIGNAL ;
    PORT
      LAYER M5 ;
        RECT 49.056 0.000 49.080 0.192 ;
    END
  END u_rank__od[211]
  PIN u_rank__od[212]
    DIRECTION OUTPUT ;
    USE SIGNAL ;
    PORT
      LAYER M5 ;
        RECT 49.248 0.000 49.272 0.192 ;
    END
  END u_rank__od[212]
  PIN u_rank__od[213]
    DIRECTION OUTPUT ;
    USE SIGNAL ;
    PORT
      LAYER M5 ;
        RECT 49.392 0.000 49.416 0.192 ;
    END
  END u_rank__od[213]
  PIN u_rank__od[214]
    DIRECTION OUTPUT ;
    USE SIGNAL ;
    PORT
      LAYER M5 ;
        RECT 49.584 0.000 49.608 0.192 ;
    END
  END u_rank__od[214]
  PIN u_rank__od[215]
    DIRECTION OUTPUT ;
    USE SIGNAL ;
    PORT
      LAYER M5 ;
        RECT 49.728 0.000 49.752 0.192 ;
    END
  END u_rank__od[215]
  PIN u_rank__od[216]
    DIRECTION OUTPUT ;
    USE SIGNAL ;
    PORT
      LAYER M5 ;
        RECT 49.872 0.000 49.896 0.192 ;
    END
  END u_rank__od[216]
  PIN u_rank__od[217]
    DIRECTION OUTPUT ;
    USE SIGNAL ;
    PORT
      LAYER M5 ;
        RECT 50.064 0.000 50.088 0.192 ;
    END
  END u_rank__od[217]
  PIN u_rank__od[218]
    DIRECTION OUTPUT ;
    USE SIGNAL ;
    PORT
      LAYER M5 ;
        RECT 50.208 0.000 50.232 0.192 ;
    END
  END u_rank__od[218]
  PIN u_rank__od[219]
    DIRECTION OUTPUT ;
    USE SIGNAL ;
    PORT
      LAYER M5 ;
        RECT 50.400 0.000 50.424 0.192 ;
    END
  END u_rank__od[219]
  PIN u_rank__od[21]
    DIRECTION OUTPUT ;
    USE SIGNAL ;
    PORT
      LAYER M5 ;
        RECT 17.376 0.000 17.400 0.192 ;
    END
  END u_rank__od[21]
  PIN u_rank__od[220]
    DIRECTION OUTPUT ;
    USE SIGNAL ;
    PORT
      LAYER M5 ;
        RECT 50.544 0.000 50.568 0.192 ;
    END
  END u_rank__od[220]
  PIN u_rank__od[221]
    DIRECTION OUTPUT ;
    USE SIGNAL ;
    PORT
      LAYER M5 ;
        RECT 50.736 0.000 50.760 0.192 ;
    END
  END u_rank__od[221]
  PIN u_rank__od[222]
    DIRECTION OUTPUT ;
    USE SIGNAL ;
    PORT
      LAYER M5 ;
        RECT 50.880 0.000 50.904 0.192 ;
    END
  END u_rank__od[222]
  PIN u_rank__od[223]
    DIRECTION OUTPUT ;
    USE SIGNAL ;
    PORT
      LAYER M5 ;
        RECT 51.504 0.000 51.528 0.192 ;
    END
  END u_rank__od[223]
  PIN u_rank__od[224]
    DIRECTION OUTPUT ;
    USE SIGNAL ;
    PORT
      LAYER M5 ;
        RECT 51.552 0.000 51.576 0.192 ;
    END
  END u_rank__od[224]
  PIN u_rank__od[225]
    DIRECTION OUTPUT ;
    USE SIGNAL ;
    PORT
      LAYER M5 ;
        RECT 51.600 0.000 51.624 0.192 ;
    END
  END u_rank__od[225]
  PIN u_rank__od[226]
    DIRECTION OUTPUT ;
    USE SIGNAL ;
    PORT
      LAYER M5 ;
        RECT 51.648 0.000 51.672 0.192 ;
    END
  END u_rank__od[226]
  PIN u_rank__od[227]
    DIRECTION OUTPUT ;
    USE SIGNAL ;
    PORT
      LAYER M5 ;
        RECT 51.744 0.000 51.768 0.192 ;
    END
  END u_rank__od[227]
  PIN u_rank__od[228]
    DIRECTION OUTPUT ;
    USE SIGNAL ;
    PORT
      LAYER M5 ;
        RECT 51.888 0.000 51.912 0.192 ;
    END
  END u_rank__od[228]
  PIN u_rank__od[229]
    DIRECTION OUTPUT ;
    USE SIGNAL ;
    PORT
      LAYER M5 ;
        RECT 52.080 0.000 52.104 0.192 ;
    END
  END u_rank__od[229]
  PIN u_rank__od[22]
    DIRECTION OUTPUT ;
    USE SIGNAL ;
    PORT
      LAYER M5 ;
        RECT 17.568 0.000 17.592 0.192 ;
    END
  END u_rank__od[22]
  PIN u_rank__od[230]
    DIRECTION OUTPUT ;
    USE SIGNAL ;
    PORT
      LAYER M5 ;
        RECT 52.224 0.000 52.248 0.192 ;
    END
  END u_rank__od[230]
  PIN u_rank__od[231]
    DIRECTION OUTPUT ;
    USE SIGNAL ;
    PORT
      LAYER M5 ;
        RECT 52.416 0.000 52.440 0.192 ;
    END
  END u_rank__od[231]
  PIN u_rank__od[232]
    DIRECTION OUTPUT ;
    USE SIGNAL ;
    PORT
      LAYER M5 ;
        RECT 52.560 0.000 52.584 0.192 ;
    END
  END u_rank__od[232]
  PIN u_rank__od[233]
    DIRECTION OUTPUT ;
    USE SIGNAL ;
    PORT
      LAYER M5 ;
        RECT 52.752 0.000 52.776 0.192 ;
    END
  END u_rank__od[233]
  PIN u_rank__od[234]
    DIRECTION OUTPUT ;
    USE SIGNAL ;
    PORT
      LAYER M5 ;
        RECT 52.896 0.000 52.920 0.192 ;
    END
  END u_rank__od[234]
  PIN u_rank__od[235]
    DIRECTION OUTPUT ;
    USE SIGNAL ;
    PORT
      LAYER M5 ;
        RECT 53.040 0.000 53.064 0.192 ;
    END
  END u_rank__od[235]
  PIN u_rank__od[236]
    DIRECTION OUTPUT ;
    USE SIGNAL ;
    PORT
      LAYER M5 ;
        RECT 53.232 0.000 53.256 0.192 ;
    END
  END u_rank__od[236]
  PIN u_rank__od[237]
    DIRECTION OUTPUT ;
    USE SIGNAL ;
    PORT
      LAYER M5 ;
        RECT 53.376 0.000 53.400 0.192 ;
    END
  END u_rank__od[237]
  PIN u_rank__od[238]
    DIRECTION OUTPUT ;
    USE SIGNAL ;
    PORT
      LAYER M5 ;
        RECT 53.568 0.000 53.592 0.192 ;
    END
  END u_rank__od[238]
  PIN u_rank__od[239]
    DIRECTION OUTPUT ;
    USE SIGNAL ;
    PORT
      LAYER M5 ;
        RECT 53.712 0.000 53.736 0.192 ;
    END
  END u_rank__od[239]
  PIN u_rank__od[23]
    DIRECTION OUTPUT ;
    USE SIGNAL ;
    PORT
      LAYER M5 ;
        RECT 17.712 0.000 17.736 0.192 ;
    END
  END u_rank__od[23]
  PIN u_rank__od[240]
    DIRECTION OUTPUT ;
    USE SIGNAL ;
    PORT
      LAYER M5 ;
        RECT 53.904 0.000 53.928 0.192 ;
    END
  END u_rank__od[240]
  PIN u_rank__od[241]
    DIRECTION OUTPUT ;
    USE SIGNAL ;
    PORT
      LAYER M5 ;
        RECT 54.048 0.000 54.072 0.192 ;
    END
  END u_rank__od[241]
  PIN u_rank__od[242]
    DIRECTION OUTPUT ;
    USE SIGNAL ;
    PORT
      LAYER M5 ;
        RECT 54.240 0.000 54.264 0.192 ;
    END
  END u_rank__od[242]
  PIN u_rank__od[243]
    DIRECTION OUTPUT ;
    USE SIGNAL ;
    PORT
      LAYER M5 ;
        RECT 54.384 0.000 54.408 0.192 ;
    END
  END u_rank__od[243]
  PIN u_rank__od[244]
    DIRECTION OUTPUT ;
    USE SIGNAL ;
    PORT
      LAYER M5 ;
        RECT 54.576 0.000 54.600 0.192 ;
    END
  END u_rank__od[244]
  PIN u_rank__od[245]
    DIRECTION OUTPUT ;
    USE SIGNAL ;
    PORT
      LAYER M5 ;
        RECT 54.720 0.000 54.744 0.192 ;
    END
  END u_rank__od[245]
  PIN u_rank__od[246]
    DIRECTION OUTPUT ;
    USE SIGNAL ;
    PORT
      LAYER M5 ;
        RECT 54.912 0.000 54.936 0.192 ;
    END
  END u_rank__od[246]
  PIN u_rank__od[247]
    DIRECTION OUTPUT ;
    USE SIGNAL ;
    PORT
      LAYER M5 ;
        RECT 55.056 0.000 55.080 0.192 ;
    END
  END u_rank__od[247]
  PIN u_rank__od[248]
    DIRECTION OUTPUT ;
    USE SIGNAL ;
    PORT
      LAYER M5 ;
        RECT 55.248 0.000 55.272 0.192 ;
    END
  END u_rank__od[248]
  PIN u_rank__od[249]
    DIRECTION OUTPUT ;
    USE SIGNAL ;
    PORT
      LAYER M5 ;
        RECT 55.392 0.000 55.416 0.192 ;
    END
  END u_rank__od[249]
  PIN u_rank__od[24]
    DIRECTION OUTPUT ;
    USE SIGNAL ;
    PORT
      LAYER M5 ;
        RECT 17.904 0.000 17.928 0.192 ;
    END
  END u_rank__od[24]
  PIN u_rank__od[250]
    DIRECTION OUTPUT ;
    USE SIGNAL ;
    PORT
      LAYER M5 ;
        RECT 55.584 0.000 55.608 0.192 ;
    END
  END u_rank__od[250]
  PIN u_rank__od[251]
    DIRECTION OUTPUT ;
    USE SIGNAL ;
    PORT
      LAYER M5 ;
        RECT 55.728 0.000 55.752 0.192 ;
    END
  END u_rank__od[251]
  PIN u_rank__od[252]
    DIRECTION OUTPUT ;
    USE SIGNAL ;
    PORT
      LAYER M5 ;
        RECT 55.872 0.000 55.896 0.192 ;
    END
  END u_rank__od[252]
  PIN u_rank__od[253]
    DIRECTION OUTPUT ;
    USE SIGNAL ;
    PORT
      LAYER M5 ;
        RECT 56.064 0.000 56.088 0.192 ;
    END
  END u_rank__od[253]
  PIN u_rank__od[254]
    DIRECTION OUTPUT ;
    USE SIGNAL ;
    PORT
      LAYER M5 ;
        RECT 56.208 0.000 56.232 0.192 ;
    END
  END u_rank__od[254]
  PIN u_rank__od[255]
    DIRECTION OUTPUT ;
    USE SIGNAL ;
    PORT
      LAYER M5 ;
        RECT 56.976 0.000 57.000 0.192 ;
    END
  END u_rank__od[255]
  PIN u_rank__od[25]
    DIRECTION OUTPUT ;
    USE SIGNAL ;
    PORT
      LAYER M5 ;
        RECT 18.048 0.000 18.072 0.192 ;
    END
  END u_rank__od[25]
  PIN u_rank__od[26]
    DIRECTION OUTPUT ;
    USE SIGNAL ;
    PORT
      LAYER M5 ;
        RECT 18.240 0.000 18.264 0.192 ;
    END
  END u_rank__od[26]
  PIN u_rank__od[27]
    DIRECTION OUTPUT ;
    USE SIGNAL ;
    PORT
      LAYER M5 ;
        RECT 18.384 0.000 18.408 0.192 ;
    END
  END u_rank__od[27]
  PIN u_rank__od[28]
    DIRECTION OUTPUT ;
    USE SIGNAL ;
    PORT
      LAYER M5 ;
        RECT 19.104 0.000 19.128 0.192 ;
    END
  END u_rank__od[28]
  PIN u_rank__od[29]
    DIRECTION OUTPUT ;
    USE SIGNAL ;
    PORT
      LAYER M5 ;
        RECT 19.152 0.000 19.176 0.192 ;
    END
  END u_rank__od[29]
  PIN u_rank__od[2]
    DIRECTION OUTPUT ;
    USE SIGNAL ;
    PORT
      LAYER M5 ;
        RECT 14.208 0.000 14.232 0.192 ;
    END
  END u_rank__od[2]
  PIN u_rank__od[30]
    DIRECTION OUTPUT ;
    USE SIGNAL ;
    PORT
      LAYER M5 ;
        RECT 19.200 0.000 19.224 0.192 ;
    END
  END u_rank__od[30]
  PIN u_rank__od[31]
    DIRECTION OUTPUT ;
    USE SIGNAL ;
    PORT
      LAYER M5 ;
        RECT 19.248 0.000 19.272 0.192 ;
    END
  END u_rank__od[31]
  PIN u_rank__od[32]
    DIRECTION OUTPUT ;
    USE SIGNAL ;
    PORT
      LAYER M5 ;
        RECT 19.296 0.000 19.320 0.192 ;
    END
  END u_rank__od[32]
  PIN u_rank__od[33]
    DIRECTION OUTPUT ;
    USE SIGNAL ;
    PORT
      LAYER M5 ;
        RECT 19.392 0.000 19.416 0.192 ;
    END
  END u_rank__od[33]
  PIN u_rank__od[34]
    DIRECTION OUTPUT ;
    USE SIGNAL ;
    PORT
      LAYER M5 ;
        RECT 19.584 0.000 19.608 0.192 ;
    END
  END u_rank__od[34]
  PIN u_rank__od[35]
    DIRECTION OUTPUT ;
    USE SIGNAL ;
    PORT
      LAYER M5 ;
        RECT 19.728 0.000 19.752 0.192 ;
    END
  END u_rank__od[35]
  PIN u_rank__od[36]
    DIRECTION OUTPUT ;
    USE SIGNAL ;
    PORT
      LAYER M5 ;
        RECT 19.872 0.000 19.896 0.192 ;
    END
  END u_rank__od[36]
  PIN u_rank__od[37]
    DIRECTION OUTPUT ;
    USE SIGNAL ;
    PORT
      LAYER M5 ;
        RECT 20.064 0.000 20.088 0.192 ;
    END
  END u_rank__od[37]
  PIN u_rank__od[38]
    DIRECTION OUTPUT ;
    USE SIGNAL ;
    PORT
      LAYER M5 ;
        RECT 20.208 0.000 20.232 0.192 ;
    END
  END u_rank__od[38]
  PIN u_rank__od[39]
    DIRECTION OUTPUT ;
    USE SIGNAL ;
    PORT
      LAYER M5 ;
        RECT 20.400 0.000 20.424 0.192 ;
    END
  END u_rank__od[39]
  PIN u_rank__od[3]
    DIRECTION OUTPUT ;
    USE SIGNAL ;
    PORT
      LAYER M5 ;
        RECT 14.400 0.000 14.424 0.192 ;
    END
  END u_rank__od[3]
  PIN u_rank__od[40]
    DIRECTION OUTPUT ;
    USE SIGNAL ;
    PORT
      LAYER M5 ;
        RECT 20.544 0.000 20.568 0.192 ;
    END
  END u_rank__od[40]
  PIN u_rank__od[41]
    DIRECTION OUTPUT ;
    USE SIGNAL ;
    PORT
      LAYER M5 ;
        RECT 20.736 0.000 20.760 0.192 ;
    END
  END u_rank__od[41]
  PIN u_rank__od[42]
    DIRECTION OUTPUT ;
    USE SIGNAL ;
    PORT
      LAYER M5 ;
        RECT 20.880 0.000 20.904 0.192 ;
    END
  END u_rank__od[42]
  PIN u_rank__od[43]
    DIRECTION OUTPUT ;
    USE SIGNAL ;
    PORT
      LAYER M5 ;
        RECT 21.072 0.000 21.096 0.192 ;
    END
  END u_rank__od[43]
  PIN u_rank__od[44]
    DIRECTION OUTPUT ;
    USE SIGNAL ;
    PORT
      LAYER M5 ;
        RECT 21.216 0.000 21.240 0.192 ;
    END
  END u_rank__od[44]
  PIN u_rank__od[45]
    DIRECTION OUTPUT ;
    USE SIGNAL ;
    PORT
      LAYER M5 ;
        RECT 21.408 0.000 21.432 0.192 ;
    END
  END u_rank__od[45]
  PIN u_rank__od[46]
    DIRECTION OUTPUT ;
    USE SIGNAL ;
    PORT
      LAYER M5 ;
        RECT 21.552 0.000 21.576 0.192 ;
    END
  END u_rank__od[46]
  PIN u_rank__od[47]
    DIRECTION OUTPUT ;
    USE SIGNAL ;
    PORT
      LAYER M5 ;
        RECT 21.744 0.000 21.768 0.192 ;
    END
  END u_rank__od[47]
  PIN u_rank__od[48]
    DIRECTION OUTPUT ;
    USE SIGNAL ;
    PORT
      LAYER M5 ;
        RECT 21.888 0.000 21.912 0.192 ;
    END
  END u_rank__od[48]
  PIN u_rank__od[49]
    DIRECTION OUTPUT ;
    USE SIGNAL ;
    PORT
      LAYER M5 ;
        RECT 22.080 0.000 22.104 0.192 ;
    END
  END u_rank__od[49]
  PIN u_rank__od[4]
    DIRECTION OUTPUT ;
    USE SIGNAL ;
    PORT
      LAYER M5 ;
        RECT 14.544 0.000 14.568 0.192 ;
    END
  END u_rank__od[4]
  PIN u_rank__od[50]
    DIRECTION OUTPUT ;
    USE SIGNAL ;
    PORT
      LAYER M5 ;
        RECT 22.224 0.000 22.248 0.192 ;
    END
  END u_rank__od[50]
  PIN u_rank__od[51]
    DIRECTION OUTPUT ;
    USE SIGNAL ;
    PORT
      LAYER M5 ;
        RECT 22.416 0.000 22.440 0.192 ;
    END
  END u_rank__od[51]
  PIN u_rank__od[52]
    DIRECTION OUTPUT ;
    USE SIGNAL ;
    PORT
      LAYER M5 ;
        RECT 22.560 0.000 22.584 0.192 ;
    END
  END u_rank__od[52]
  PIN u_rank__od[53]
    DIRECTION OUTPUT ;
    USE SIGNAL ;
    PORT
      LAYER M5 ;
        RECT 22.752 0.000 22.776 0.192 ;
    END
  END u_rank__od[53]
  PIN u_rank__od[54]
    DIRECTION OUTPUT ;
    USE SIGNAL ;
    PORT
      LAYER M5 ;
        RECT 22.896 0.000 22.920 0.192 ;
    END
  END u_rank__od[54]
  PIN u_rank__od[55]
    DIRECTION OUTPUT ;
    USE SIGNAL ;
    PORT
      LAYER M5 ;
        RECT 23.040 0.000 23.064 0.192 ;
    END
  END u_rank__od[55]
  PIN u_rank__od[56]
    DIRECTION OUTPUT ;
    USE SIGNAL ;
    PORT
      LAYER M5 ;
        RECT 23.232 0.000 23.256 0.192 ;
    END
  END u_rank__od[56]
  PIN u_rank__od[57]
    DIRECTION OUTPUT ;
    USE SIGNAL ;
    PORT
      LAYER M5 ;
        RECT 23.376 0.000 23.400 0.192 ;
    END
  END u_rank__od[57]
  PIN u_rank__od[58]
    DIRECTION OUTPUT ;
    USE SIGNAL ;
    PORT
      LAYER M5 ;
        RECT 23.568 0.000 23.592 0.192 ;
    END
  END u_rank__od[58]
  PIN u_rank__od[59]
    DIRECTION OUTPUT ;
    USE SIGNAL ;
    PORT
      LAYER M5 ;
        RECT 23.712 0.000 23.736 0.192 ;
    END
  END u_rank__od[59]
  PIN u_rank__od[5]
    DIRECTION OUTPUT ;
    USE SIGNAL ;
    PORT
      LAYER M5 ;
        RECT 14.736 0.000 14.760 0.192 ;
    END
  END u_rank__od[5]
  PIN u_rank__od[60]
    DIRECTION OUTPUT ;
    USE SIGNAL ;
    PORT
      LAYER M5 ;
        RECT 23.904 0.000 23.928 0.192 ;
    END
  END u_rank__od[60]
  PIN u_rank__od[61]
    DIRECTION OUTPUT ;
    USE SIGNAL ;
    PORT
      LAYER M5 ;
        RECT 24.528 0.000 24.552 0.192 ;
    END
  END u_rank__od[61]
  PIN u_rank__od[62]
    DIRECTION OUTPUT ;
    USE SIGNAL ;
    PORT
      LAYER M5 ;
        RECT 24.576 0.000 24.600 0.192 ;
    END
  END u_rank__od[62]
  PIN u_rank__od[63]
    DIRECTION OUTPUT ;
    USE SIGNAL ;
    PORT
      LAYER M5 ;
        RECT 24.624 0.000 24.648 0.192 ;
    END
  END u_rank__od[63]
  PIN u_rank__od[64]
    DIRECTION OUTPUT ;
    USE SIGNAL ;
    PORT
      LAYER M5 ;
        RECT 24.672 0.000 24.696 0.192 ;
    END
  END u_rank__od[64]
  PIN u_rank__od[65]
    DIRECTION OUTPUT ;
    USE SIGNAL ;
    PORT
      LAYER M5 ;
        RECT 24.720 0.000 24.744 0.192 ;
    END
  END u_rank__od[65]
  PIN u_rank__od[66]
    DIRECTION OUTPUT ;
    USE SIGNAL ;
    PORT
      LAYER M5 ;
        RECT 24.912 0.000 24.936 0.192 ;
    END
  END u_rank__od[66]
  PIN u_rank__od[67]
    DIRECTION OUTPUT ;
    USE SIGNAL ;
    PORT
      LAYER M5 ;
        RECT 25.056 0.000 25.080 0.192 ;
    END
  END u_rank__od[67]
  PIN u_rank__od[68]
    DIRECTION OUTPUT ;
    USE SIGNAL ;
    PORT
      LAYER M5 ;
        RECT 25.248 0.000 25.272 0.192 ;
    END
  END u_rank__od[68]
  PIN u_rank__od[69]
    DIRECTION OUTPUT ;
    USE SIGNAL ;
    PORT
      LAYER M5 ;
        RECT 25.392 0.000 25.416 0.192 ;
    END
  END u_rank__od[69]
  PIN u_rank__od[6]
    DIRECTION OUTPUT ;
    USE SIGNAL ;
    PORT
      LAYER M5 ;
        RECT 14.880 0.000 14.904 0.192 ;
    END
  END u_rank__od[6]
  PIN u_rank__od[70]
    DIRECTION OUTPUT ;
    USE SIGNAL ;
    PORT
      LAYER M5 ;
        RECT 25.584 0.000 25.608 0.192 ;
    END
  END u_rank__od[70]
  PIN u_rank__od[71]
    DIRECTION OUTPUT ;
    USE SIGNAL ;
    PORT
      LAYER M5 ;
        RECT 25.728 0.000 25.752 0.192 ;
    END
  END u_rank__od[71]
  PIN u_rank__od[72]
    DIRECTION OUTPUT ;
    USE SIGNAL ;
    PORT
      LAYER M5 ;
        RECT 25.872 0.000 25.896 0.192 ;
    END
  END u_rank__od[72]
  PIN u_rank__od[73]
    DIRECTION OUTPUT ;
    USE SIGNAL ;
    PORT
      LAYER M5 ;
        RECT 26.064 0.000 26.088 0.192 ;
    END
  END u_rank__od[73]
  PIN u_rank__od[74]
    DIRECTION OUTPUT ;
    USE SIGNAL ;
    PORT
      LAYER M5 ;
        RECT 26.208 0.000 26.232 0.192 ;
    END
  END u_rank__od[74]
  PIN u_rank__od[75]
    DIRECTION OUTPUT ;
    USE SIGNAL ;
    PORT
      LAYER M5 ;
        RECT 26.400 0.000 26.424 0.192 ;
    END
  END u_rank__od[75]
  PIN u_rank__od[76]
    DIRECTION OUTPUT ;
    USE SIGNAL ;
    PORT
      LAYER M5 ;
        RECT 26.544 0.000 26.568 0.192 ;
    END
  END u_rank__od[76]
  PIN u_rank__od[77]
    DIRECTION OUTPUT ;
    USE SIGNAL ;
    PORT
      LAYER M5 ;
        RECT 26.736 0.000 26.760 0.192 ;
    END
  END u_rank__od[77]
  PIN u_rank__od[78]
    DIRECTION OUTPUT ;
    USE SIGNAL ;
    PORT
      LAYER M5 ;
        RECT 26.880 0.000 26.904 0.192 ;
    END
  END u_rank__od[78]
  PIN u_rank__od[79]
    DIRECTION OUTPUT ;
    USE SIGNAL ;
    PORT
      LAYER M5 ;
        RECT 27.072 0.000 27.096 0.192 ;
    END
  END u_rank__od[79]
  PIN u_rank__od[7]
    DIRECTION OUTPUT ;
    USE SIGNAL ;
    PORT
      LAYER M5 ;
        RECT 15.072 0.000 15.096 0.192 ;
    END
  END u_rank__od[7]
  PIN u_rank__od[80]
    DIRECTION OUTPUT ;
    USE SIGNAL ;
    PORT
      LAYER M5 ;
        RECT 27.216 0.000 27.240 0.192 ;
    END
  END u_rank__od[80]
  PIN u_rank__od[81]
    DIRECTION OUTPUT ;
    USE SIGNAL ;
    PORT
      LAYER M5 ;
        RECT 27.408 0.000 27.432 0.192 ;
    END
  END u_rank__od[81]
  PIN u_rank__od[82]
    DIRECTION OUTPUT ;
    USE SIGNAL ;
    PORT
      LAYER M5 ;
        RECT 27.552 0.000 27.576 0.192 ;
    END
  END u_rank__od[82]
  PIN u_rank__od[83]
    DIRECTION OUTPUT ;
    USE SIGNAL ;
    PORT
      LAYER M5 ;
        RECT 27.744 0.000 27.768 0.192 ;
    END
  END u_rank__od[83]
  PIN u_rank__od[84]
    DIRECTION OUTPUT ;
    USE SIGNAL ;
    PORT
      LAYER M5 ;
        RECT 27.888 0.000 27.912 0.192 ;
    END
  END u_rank__od[84]
  PIN u_rank__od[85]
    DIRECTION OUTPUT ;
    USE SIGNAL ;
    PORT
      LAYER M5 ;
        RECT 28.080 0.000 28.104 0.192 ;
    END
  END u_rank__od[85]
  PIN u_rank__od[86]
    DIRECTION OUTPUT ;
    USE SIGNAL ;
    PORT
      LAYER M5 ;
        RECT 28.224 0.000 28.248 0.192 ;
    END
  END u_rank__od[86]
  PIN u_rank__od[87]
    DIRECTION OUTPUT ;
    USE SIGNAL ;
    PORT
      LAYER M5 ;
        RECT 28.416 0.000 28.440 0.192 ;
    END
  END u_rank__od[87]
  PIN u_rank__od[88]
    DIRECTION OUTPUT ;
    USE SIGNAL ;
    PORT
      LAYER M5 ;
        RECT 28.560 0.000 28.584 0.192 ;
    END
  END u_rank__od[88]
  PIN u_rank__od[89]
    DIRECTION OUTPUT ;
    USE SIGNAL ;
    PORT
      LAYER M5 ;
        RECT 28.752 0.000 28.776 0.192 ;
    END
  END u_rank__od[89]
  PIN u_rank__od[8]
    DIRECTION OUTPUT ;
    USE SIGNAL ;
    PORT
      LAYER M5 ;
        RECT 15.216 0.000 15.240 0.192 ;
    END
  END u_rank__od[8]
  PIN u_rank__od[90]
    DIRECTION OUTPUT ;
    USE SIGNAL ;
    PORT
      LAYER M5 ;
        RECT 28.896 0.000 28.920 0.192 ;
    END
  END u_rank__od[90]
  PIN u_rank__od[91]
    DIRECTION OUTPUT ;
    USE SIGNAL ;
    PORT
      LAYER M5 ;
        RECT 29.040 0.000 29.064 0.192 ;
    END
  END u_rank__od[91]
  PIN u_rank__od[92]
    DIRECTION OUTPUT ;
    USE SIGNAL ;
    PORT
      LAYER M5 ;
        RECT 29.232 0.000 29.256 0.192 ;
    END
  END u_rank__od[92]
  PIN u_rank__od[93]
    DIRECTION OUTPUT ;
    USE SIGNAL ;
    PORT
      LAYER M5 ;
        RECT 29.904 0.000 29.928 0.192 ;
    END
  END u_rank__od[93]
  PIN u_rank__od[94]
    DIRECTION OUTPUT ;
    USE SIGNAL ;
    PORT
      LAYER M5 ;
        RECT 29.952 0.000 29.976 0.192 ;
    END
  END u_rank__od[94]
  PIN u_rank__od[95]
    DIRECTION OUTPUT ;
    USE SIGNAL ;
    PORT
      LAYER M5 ;
        RECT 30.000 0.000 30.024 0.192 ;
    END
  END u_rank__od[95]
  PIN u_rank__od[96]
    DIRECTION OUTPUT ;
    USE SIGNAL ;
    PORT
      LAYER M5 ;
        RECT 30.048 0.000 30.072 0.192 ;
    END
  END u_rank__od[96]
  PIN u_rank__od[97]
    DIRECTION OUTPUT ;
    USE SIGNAL ;
    PORT
      LAYER M5 ;
        RECT 30.096 0.000 30.120 0.192 ;
    END
  END u_rank__od[97]
  PIN u_rank__od[98]
    DIRECTION OUTPUT ;
    USE SIGNAL ;
    PORT
      LAYER M5 ;
        RECT 30.240 0.000 30.264 0.192 ;
    END
  END u_rank__od[98]
  PIN u_rank__od[99]
    DIRECTION OUTPUT ;
    USE SIGNAL ;
    PORT
      LAYER M5 ;
        RECT 30.384 0.000 30.408 0.192 ;
    END
  END u_rank__od[99]
  PIN u_rank__od[9]
    DIRECTION OUTPUT ;
    USE SIGNAL ;
    PORT
      LAYER M5 ;
        RECT 15.408 0.000 15.432 0.192 ;
    END
  END u_rank__od[9]
  PIN u_rank__ov
    DIRECTION OUTPUT ;
    USE SIGNAL ;
    PORT
      LAYER M5 ;
        RECT 57.024 0.000 57.048 0.192 ;
    END
  END u_rank__ov
  PIN u_rank__owe
    DIRECTION OUTPUT ;
    USE SIGNAL ;
    PORT
      LAYER M5 ;
        RECT 57.120 0.000 57.144 0.192 ;
    END
  END u_rank__owe
  PIN u_rank__qm_cls[0]
    DIRECTION INPUT ;
    USE SIGNAL ;
    PORT
      LAYER M5 ;
        RECT 330.528 0.000 330.552 0.192 ;
    END
  END u_rank__qm_cls[0]
  PIN u_rank__qm_cls[1]
    DIRECTION INPUT ;
    USE SIGNAL ;
    PORT
      LAYER M5 ;
        RECT 330.672 0.000 330.696 0.192 ;
    END
  END u_rank__qm_cls[1]
  PIN u_rank__qm_crn[0]
    DIRECTION OUTPUT ;
    USE SIGNAL ;
    PORT
      LAYER M5 ;
        RECT 330.864 0.000 330.888 0.192 ;
    END
  END u_rank__qm_crn[0]
  PIN u_rank__qm_crn[1]
    DIRECTION OUTPUT ;
    USE SIGNAL ;
    PORT
      LAYER M5 ;
        RECT 331.008 0.000 331.032 0.192 ;
    END
  END u_rank__qm_crn[1]
  PIN u_rank__qm_crn[2]
    DIRECTION OUTPUT ;
    USE SIGNAL ;
    PORT
      LAYER M5 ;
        RECT 331.200 0.000 331.224 0.192 ;
    END
  END u_rank__qm_crn[2]
  PIN u_rank__qm_crn[3]
    DIRECTION OUTPUT ;
    USE SIGNAL ;
    PORT
      LAYER M5 ;
        RECT 331.344 0.000 331.368 0.192 ;
    END
  END u_rank__qm_crn[3]
  PIN u_rank__qm_crn[4]
    DIRECTION OUTPUT ;
    USE SIGNAL ;
    PORT
      LAYER M5 ;
        RECT 331.536 0.000 331.560 0.192 ;
    END
  END u_rank__qm_crn[4]
  PIN u_rank__qm_d[0]
    DIRECTION INPUT ;
    USE SIGNAL ;
    PORT
      LAYER M4 ;
        RECT 345.408 13.872 345.600 13.896 ;
    END
  END u_rank__qm_d[0]
  PIN u_rank__qm_d[100]
    DIRECTION INPUT ;
    USE SIGNAL ;
    PORT
      LAYER M4 ;
        RECT 345.408 30.576 345.600 30.600 ;
    END
  END u_rank__qm_d[100]
  PIN u_rank__qm_d[101]
    DIRECTION INPUT ;
    USE SIGNAL ;
    PORT
      LAYER M4 ;
        RECT 345.408 30.720 345.600 30.744 ;
    END
  END u_rank__qm_d[101]
  PIN u_rank__qm_d[102]
    DIRECTION INPUT ;
    USE SIGNAL ;
    PORT
      LAYER M4 ;
        RECT 345.408 30.912 345.600 30.936 ;
    END
  END u_rank__qm_d[102]
  PIN u_rank__qm_d[103]
    DIRECTION INPUT ;
    USE SIGNAL ;
    PORT
      LAYER M4 ;
        RECT 345.408 31.056 345.600 31.080 ;
    END
  END u_rank__qm_d[103]
  PIN u_rank__qm_d[104]
    DIRECTION INPUT ;
    USE SIGNAL ;
    PORT
      LAYER M4 ;
        RECT 345.408 31.248 345.600 31.272 ;
    END
  END u_rank__qm_d[104]
  PIN u_rank__qm_d[105]
    DIRECTION INPUT ;
    USE SIGNAL ;
    PORT
      LAYER M4 ;
        RECT 345.408 31.392 345.600 31.416 ;
    END
  END u_rank__qm_d[105]
  PIN u_rank__qm_d[106]
    DIRECTION INPUT ;
    USE SIGNAL ;
    PORT
      LAYER M4 ;
        RECT 345.408 31.584 345.600 31.608 ;
    END
  END u_rank__qm_d[106]
  PIN u_rank__qm_d[107]
    DIRECTION INPUT ;
    USE SIGNAL ;
    PORT
      LAYER M4 ;
        RECT 345.408 31.728 345.600 31.752 ;
    END
  END u_rank__qm_d[107]
  PIN u_rank__qm_d[108]
    DIRECTION INPUT ;
    USE SIGNAL ;
    PORT
      LAYER M4 ;
        RECT 345.408 31.872 345.600 31.896 ;
    END
  END u_rank__qm_d[108]
  PIN u_rank__qm_d[109]
    DIRECTION INPUT ;
    USE SIGNAL ;
    PORT
      LAYER M4 ;
        RECT 345.408 32.064 345.600 32.088 ;
    END
  END u_rank__qm_d[109]
  PIN u_rank__qm_d[10]
    DIRECTION INPUT ;
    USE SIGNAL ;
    PORT
      LAYER M4 ;
        RECT 345.408 15.552 345.600 15.576 ;
    END
  END u_rank__qm_d[10]
  PIN u_rank__qm_d[110]
    DIRECTION INPUT ;
    USE SIGNAL ;
    PORT
      LAYER M4 ;
        RECT 345.408 32.208 345.600 32.232 ;
    END
  END u_rank__qm_d[110]
  PIN u_rank__qm_d[111]
    DIRECTION INPUT ;
    USE SIGNAL ;
    PORT
      LAYER M4 ;
        RECT 345.408 32.400 345.600 32.424 ;
    END
  END u_rank__qm_d[111]
  PIN u_rank__qm_d[112]
    DIRECTION INPUT ;
    USE SIGNAL ;
    PORT
      LAYER M4 ;
        RECT 345.408 32.544 345.600 32.568 ;
    END
  END u_rank__qm_d[112]
  PIN u_rank__qm_d[113]
    DIRECTION INPUT ;
    USE SIGNAL ;
    PORT
      LAYER M4 ;
        RECT 345.408 32.736 345.600 32.760 ;
    END
  END u_rank__qm_d[113]
  PIN u_rank__qm_d[114]
    DIRECTION INPUT ;
    USE SIGNAL ;
    PORT
      LAYER M4 ;
        RECT 345.408 32.880 345.600 32.904 ;
    END
  END u_rank__qm_d[114]
  PIN u_rank__qm_d[115]
    DIRECTION INPUT ;
    USE SIGNAL ;
    PORT
      LAYER M4 ;
        RECT 345.408 33.072 345.600 33.096 ;
    END
  END u_rank__qm_d[115]
  PIN u_rank__qm_d[116]
    DIRECTION INPUT ;
    USE SIGNAL ;
    PORT
      LAYER M4 ;
        RECT 345.408 33.216 345.600 33.240 ;
    END
  END u_rank__qm_d[116]
  PIN u_rank__qm_d[117]
    DIRECTION INPUT ;
    USE SIGNAL ;
    PORT
      LAYER M4 ;
        RECT 345.408 33.408 345.600 33.432 ;
    END
  END u_rank__qm_d[117]
  PIN u_rank__qm_d[118]
    DIRECTION INPUT ;
    USE SIGNAL ;
    PORT
      LAYER M4 ;
        RECT 345.408 33.552 345.600 33.576 ;
    END
  END u_rank__qm_d[118]
  PIN u_rank__qm_d[119]
    DIRECTION INPUT ;
    USE SIGNAL ;
    PORT
      LAYER M4 ;
        RECT 345.408 33.744 345.600 33.768 ;
    END
  END u_rank__qm_d[119]
  PIN u_rank__qm_d[11]
    DIRECTION INPUT ;
    USE SIGNAL ;
    PORT
      LAYER M4 ;
        RECT 345.408 15.744 345.600 15.768 ;
    END
  END u_rank__qm_d[11]
  PIN u_rank__qm_d[120]
    DIRECTION INPUT ;
    USE SIGNAL ;
    PORT
      LAYER M4 ;
        RECT 345.408 33.888 345.600 33.912 ;
    END
  END u_rank__qm_d[120]
  PIN u_rank__qm_d[121]
    DIRECTION INPUT ;
    USE SIGNAL ;
    PORT
      LAYER M4 ;
        RECT 345.408 34.080 345.600 34.104 ;
    END
  END u_rank__qm_d[121]
  PIN u_rank__qm_d[122]
    DIRECTION INPUT ;
    USE SIGNAL ;
    PORT
      LAYER M4 ;
        RECT 345.408 34.224 345.600 34.248 ;
    END
  END u_rank__qm_d[122]
  PIN u_rank__qm_d[123]
    DIRECTION INPUT ;
    USE SIGNAL ;
    PORT
      LAYER M4 ;
        RECT 345.408 34.416 345.600 34.440 ;
    END
  END u_rank__qm_d[123]
  PIN u_rank__qm_d[124]
    DIRECTION INPUT ;
    USE SIGNAL ;
    PORT
      LAYER M4 ;
        RECT 345.408 34.560 345.600 34.584 ;
    END
  END u_rank__qm_d[124]
  PIN u_rank__qm_d[125]
    DIRECTION INPUT ;
    USE SIGNAL ;
    PORT
      LAYER M4 ;
        RECT 345.408 34.752 345.600 34.776 ;
    END
  END u_rank__qm_d[125]
  PIN u_rank__qm_d[126]
    DIRECTION INPUT ;
    USE SIGNAL ;
    PORT
      LAYER M4 ;
        RECT 345.408 34.896 345.600 34.920 ;
    END
  END u_rank__qm_d[126]
  PIN u_rank__qm_d[127]
    DIRECTION INPUT ;
    USE SIGNAL ;
    PORT
      LAYER M4 ;
        RECT 345.408 35.040 345.600 35.064 ;
    END
  END u_rank__qm_d[127]
  PIN u_rank__qm_d[128]
    DIRECTION INPUT ;
    USE SIGNAL ;
    PORT
      LAYER M4 ;
        RECT 345.408 35.232 345.600 35.256 ;
    END
  END u_rank__qm_d[128]
  PIN u_rank__qm_d[129]
    DIRECTION INPUT ;
    USE SIGNAL ;
    PORT
      LAYER M4 ;
        RECT 345.408 35.376 345.600 35.400 ;
    END
  END u_rank__qm_d[129]
  PIN u_rank__qm_d[12]
    DIRECTION INPUT ;
    USE SIGNAL ;
    PORT
      LAYER M4 ;
        RECT 345.408 15.888 345.600 15.912 ;
    END
  END u_rank__qm_d[12]
  PIN u_rank__qm_d[130]
    DIRECTION INPUT ;
    USE SIGNAL ;
    PORT
      LAYER M4 ;
        RECT 345.408 35.568 345.600 35.592 ;
    END
  END u_rank__qm_d[130]
  PIN u_rank__qm_d[131]
    DIRECTION INPUT ;
    USE SIGNAL ;
    PORT
      LAYER M4 ;
        RECT 345.408 35.712 345.600 35.736 ;
    END
  END u_rank__qm_d[131]
  PIN u_rank__qm_d[132]
    DIRECTION INPUT ;
    USE SIGNAL ;
    PORT
      LAYER M4 ;
        RECT 345.408 35.904 345.600 35.928 ;
    END
  END u_rank__qm_d[132]
  PIN u_rank__qm_d[133]
    DIRECTION INPUT ;
    USE SIGNAL ;
    PORT
      LAYER M4 ;
        RECT 345.408 36.048 345.600 36.072 ;
    END
  END u_rank__qm_d[133]
  PIN u_rank__qm_d[134]
    DIRECTION INPUT ;
    USE SIGNAL ;
    PORT
      LAYER M4 ;
        RECT 345.408 36.240 345.600 36.264 ;
    END
  END u_rank__qm_d[134]
  PIN u_rank__qm_d[135]
    DIRECTION INPUT ;
    USE SIGNAL ;
    PORT
      LAYER M4 ;
        RECT 345.408 36.384 345.600 36.408 ;
    END
  END u_rank__qm_d[135]
  PIN u_rank__qm_d[136]
    DIRECTION INPUT ;
    USE SIGNAL ;
    PORT
      LAYER M4 ;
        RECT 345.408 36.576 345.600 36.600 ;
    END
  END u_rank__qm_d[136]
  PIN u_rank__qm_d[137]
    DIRECTION INPUT ;
    USE SIGNAL ;
    PORT
      LAYER M4 ;
        RECT 345.408 36.720 345.600 36.744 ;
    END
  END u_rank__qm_d[137]
  PIN u_rank__qm_d[138]
    DIRECTION INPUT ;
    USE SIGNAL ;
    PORT
      LAYER M4 ;
        RECT 345.408 36.912 345.600 36.936 ;
    END
  END u_rank__qm_d[138]
  PIN u_rank__qm_d[139]
    DIRECTION INPUT ;
    USE SIGNAL ;
    PORT
      LAYER M4 ;
        RECT 345.408 37.056 345.600 37.080 ;
    END
  END u_rank__qm_d[139]
  PIN u_rank__qm_d[13]
    DIRECTION INPUT ;
    USE SIGNAL ;
    PORT
      LAYER M4 ;
        RECT 345.408 16.080 345.600 16.104 ;
    END
  END u_rank__qm_d[13]
  PIN u_rank__qm_d[140]
    DIRECTION INPUT ;
    USE SIGNAL ;
    PORT
      LAYER M4 ;
        RECT 345.408 37.248 345.600 37.272 ;
    END
  END u_rank__qm_d[140]
  PIN u_rank__qm_d[141]
    DIRECTION INPUT ;
    USE SIGNAL ;
    PORT
      LAYER M4 ;
        RECT 345.408 37.392 345.600 37.416 ;
    END
  END u_rank__qm_d[141]
  PIN u_rank__qm_d[142]
    DIRECTION INPUT ;
    USE SIGNAL ;
    PORT
      LAYER M4 ;
        RECT 345.408 37.584 345.600 37.608 ;
    END
  END u_rank__qm_d[142]
  PIN u_rank__qm_d[143]
    DIRECTION INPUT ;
    USE SIGNAL ;
    PORT
      LAYER M4 ;
        RECT 345.408 37.728 345.600 37.752 ;
    END
  END u_rank__qm_d[143]
  PIN u_rank__qm_d[144]
    DIRECTION INPUT ;
    USE SIGNAL ;
    PORT
      LAYER M4 ;
        RECT 345.408 37.872 345.600 37.896 ;
    END
  END u_rank__qm_d[144]
  PIN u_rank__qm_d[145]
    DIRECTION INPUT ;
    USE SIGNAL ;
    PORT
      LAYER M4 ;
        RECT 345.408 38.064 345.600 38.088 ;
    END
  END u_rank__qm_d[145]
  PIN u_rank__qm_d[146]
    DIRECTION INPUT ;
    USE SIGNAL ;
    PORT
      LAYER M4 ;
        RECT 345.408 38.208 345.600 38.232 ;
    END
  END u_rank__qm_d[146]
  PIN u_rank__qm_d[147]
    DIRECTION INPUT ;
    USE SIGNAL ;
    PORT
      LAYER M4 ;
        RECT 345.408 38.400 345.600 38.424 ;
    END
  END u_rank__qm_d[147]
  PIN u_rank__qm_d[148]
    DIRECTION INPUT ;
    USE SIGNAL ;
    PORT
      LAYER M4 ;
        RECT 345.408 38.544 345.600 38.568 ;
    END
  END u_rank__qm_d[148]
  PIN u_rank__qm_d[149]
    DIRECTION INPUT ;
    USE SIGNAL ;
    PORT
      LAYER M4 ;
        RECT 345.408 38.736 345.600 38.760 ;
    END
  END u_rank__qm_d[149]
  PIN u_rank__qm_d[14]
    DIRECTION INPUT ;
    USE SIGNAL ;
    PORT
      LAYER M4 ;
        RECT 345.408 16.224 345.600 16.248 ;
    END
  END u_rank__qm_d[14]
  PIN u_rank__qm_d[150]
    DIRECTION INPUT ;
    USE SIGNAL ;
    PORT
      LAYER M4 ;
        RECT 345.408 38.880 345.600 38.904 ;
    END
  END u_rank__qm_d[150]
  PIN u_rank__qm_d[151]
    DIRECTION INPUT ;
    USE SIGNAL ;
    PORT
      LAYER M4 ;
        RECT 345.408 39.072 345.600 39.096 ;
    END
  END u_rank__qm_d[151]
  PIN u_rank__qm_d[152]
    DIRECTION INPUT ;
    USE SIGNAL ;
    PORT
      LAYER M4 ;
        RECT 345.408 39.216 345.600 39.240 ;
    END
  END u_rank__qm_d[152]
  PIN u_rank__qm_d[153]
    DIRECTION INPUT ;
    USE SIGNAL ;
    PORT
      LAYER M4 ;
        RECT 345.408 39.408 345.600 39.432 ;
    END
  END u_rank__qm_d[153]
  PIN u_rank__qm_d[154]
    DIRECTION INPUT ;
    USE SIGNAL ;
    PORT
      LAYER M4 ;
        RECT 345.408 39.552 345.600 39.576 ;
    END
  END u_rank__qm_d[154]
  PIN u_rank__qm_d[155]
    DIRECTION INPUT ;
    USE SIGNAL ;
    PORT
      LAYER M4 ;
        RECT 345.408 39.744 345.600 39.768 ;
    END
  END u_rank__qm_d[155]
  PIN u_rank__qm_d[156]
    DIRECTION INPUT ;
    USE SIGNAL ;
    PORT
      LAYER M4 ;
        RECT 345.408 39.888 345.600 39.912 ;
    END
  END u_rank__qm_d[156]
  PIN u_rank__qm_d[157]
    DIRECTION INPUT ;
    USE SIGNAL ;
    PORT
      LAYER M4 ;
        RECT 345.408 40.080 345.600 40.104 ;
    END
  END u_rank__qm_d[157]
  PIN u_rank__qm_d[158]
    DIRECTION INPUT ;
    USE SIGNAL ;
    PORT
      LAYER M4 ;
        RECT 345.408 40.224 345.600 40.248 ;
    END
  END u_rank__qm_d[158]
  PIN u_rank__qm_d[159]
    DIRECTION INPUT ;
    USE SIGNAL ;
    PORT
      LAYER M4 ;
        RECT 345.408 40.416 345.600 40.440 ;
    END
  END u_rank__qm_d[159]
  PIN u_rank__qm_d[15]
    DIRECTION INPUT ;
    USE SIGNAL ;
    PORT
      LAYER M4 ;
        RECT 345.408 16.416 345.600 16.440 ;
    END
  END u_rank__qm_d[15]
  PIN u_rank__qm_d[160]
    DIRECTION INPUT ;
    USE SIGNAL ;
    PORT
      LAYER M4 ;
        RECT 345.408 40.560 345.600 40.584 ;
    END
  END u_rank__qm_d[160]
  PIN u_rank__qm_d[161]
    DIRECTION INPUT ;
    USE SIGNAL ;
    PORT
      LAYER M4 ;
        RECT 345.408 40.752 345.600 40.776 ;
    END
  END u_rank__qm_d[161]
  PIN u_rank__qm_d[162]
    DIRECTION INPUT ;
    USE SIGNAL ;
    PORT
      LAYER M4 ;
        RECT 345.408 40.896 345.600 40.920 ;
    END
  END u_rank__qm_d[162]
  PIN u_rank__qm_d[163]
    DIRECTION INPUT ;
    USE SIGNAL ;
    PORT
      LAYER M4 ;
        RECT 345.408 41.040 345.600 41.064 ;
    END
  END u_rank__qm_d[163]
  PIN u_rank__qm_d[164]
    DIRECTION INPUT ;
    USE SIGNAL ;
    PORT
      LAYER M4 ;
        RECT 345.408 41.232 345.600 41.256 ;
    END
  END u_rank__qm_d[164]
  PIN u_rank__qm_d[165]
    DIRECTION INPUT ;
    USE SIGNAL ;
    PORT
      LAYER M4 ;
        RECT 345.408 41.376 345.600 41.400 ;
    END
  END u_rank__qm_d[165]
  PIN u_rank__qm_d[166]
    DIRECTION INPUT ;
    USE SIGNAL ;
    PORT
      LAYER M4 ;
        RECT 345.408 41.568 345.600 41.592 ;
    END
  END u_rank__qm_d[166]
  PIN u_rank__qm_d[167]
    DIRECTION INPUT ;
    USE SIGNAL ;
    PORT
      LAYER M4 ;
        RECT 345.408 41.712 345.600 41.736 ;
    END
  END u_rank__qm_d[167]
  PIN u_rank__qm_d[168]
    DIRECTION INPUT ;
    USE SIGNAL ;
    PORT
      LAYER M4 ;
        RECT 345.408 41.904 345.600 41.928 ;
    END
  END u_rank__qm_d[168]
  PIN u_rank__qm_d[169]
    DIRECTION INPUT ;
    USE SIGNAL ;
    PORT
      LAYER M4 ;
        RECT 345.408 42.048 345.600 42.072 ;
    END
  END u_rank__qm_d[169]
  PIN u_rank__qm_d[16]
    DIRECTION INPUT ;
    USE SIGNAL ;
    PORT
      LAYER M4 ;
        RECT 345.408 16.560 345.600 16.584 ;
    END
  END u_rank__qm_d[16]
  PIN u_rank__qm_d[170]
    DIRECTION INPUT ;
    USE SIGNAL ;
    PORT
      LAYER M4 ;
        RECT 345.408 42.240 345.600 42.264 ;
    END
  END u_rank__qm_d[170]
  PIN u_rank__qm_d[171]
    DIRECTION INPUT ;
    USE SIGNAL ;
    PORT
      LAYER M4 ;
        RECT 345.408 42.384 345.600 42.408 ;
    END
  END u_rank__qm_d[171]
  PIN u_rank__qm_d[172]
    DIRECTION INPUT ;
    USE SIGNAL ;
    PORT
      LAYER M4 ;
        RECT 345.408 42.576 345.600 42.600 ;
    END
  END u_rank__qm_d[172]
  PIN u_rank__qm_d[173]
    DIRECTION INPUT ;
    USE SIGNAL ;
    PORT
      LAYER M4 ;
        RECT 345.408 42.720 345.600 42.744 ;
    END
  END u_rank__qm_d[173]
  PIN u_rank__qm_d[174]
    DIRECTION INPUT ;
    USE SIGNAL ;
    PORT
      LAYER M4 ;
        RECT 345.408 42.912 345.600 42.936 ;
    END
  END u_rank__qm_d[174]
  PIN u_rank__qm_d[175]
    DIRECTION INPUT ;
    USE SIGNAL ;
    PORT
      LAYER M4 ;
        RECT 345.408 43.056 345.600 43.080 ;
    END
  END u_rank__qm_d[175]
  PIN u_rank__qm_d[176]
    DIRECTION INPUT ;
    USE SIGNAL ;
    PORT
      LAYER M4 ;
        RECT 345.408 43.248 345.600 43.272 ;
    END
  END u_rank__qm_d[176]
  PIN u_rank__qm_d[177]
    DIRECTION INPUT ;
    USE SIGNAL ;
    PORT
      LAYER M4 ;
        RECT 345.408 43.392 345.600 43.416 ;
    END
  END u_rank__qm_d[177]
  PIN u_rank__qm_d[178]
    DIRECTION INPUT ;
    USE SIGNAL ;
    PORT
      LAYER M4 ;
        RECT 345.408 43.584 345.600 43.608 ;
    END
  END u_rank__qm_d[178]
  PIN u_rank__qm_d[179]
    DIRECTION INPUT ;
    USE SIGNAL ;
    PORT
      LAYER M4 ;
        RECT 345.408 43.728 345.600 43.752 ;
    END
  END u_rank__qm_d[179]
  PIN u_rank__qm_d[17]
    DIRECTION INPUT ;
    USE SIGNAL ;
    PORT
      LAYER M4 ;
        RECT 345.408 16.752 345.600 16.776 ;
    END
  END u_rank__qm_d[17]
  PIN u_rank__qm_d[180]
    DIRECTION INPUT ;
    USE SIGNAL ;
    PORT
      LAYER M4 ;
        RECT 345.408 43.872 345.600 43.896 ;
    END
  END u_rank__qm_d[180]
  PIN u_rank__qm_d[181]
    DIRECTION INPUT ;
    USE SIGNAL ;
    PORT
      LAYER M4 ;
        RECT 345.408 44.064 345.600 44.088 ;
    END
  END u_rank__qm_d[181]
  PIN u_rank__qm_d[182]
    DIRECTION INPUT ;
    USE SIGNAL ;
    PORT
      LAYER M4 ;
        RECT 345.408 44.208 345.600 44.232 ;
    END
  END u_rank__qm_d[182]
  PIN u_rank__qm_d[183]
    DIRECTION INPUT ;
    USE SIGNAL ;
    PORT
      LAYER M4 ;
        RECT 345.408 44.400 345.600 44.424 ;
    END
  END u_rank__qm_d[183]
  PIN u_rank__qm_d[184]
    DIRECTION INPUT ;
    USE SIGNAL ;
    PORT
      LAYER M4 ;
        RECT 345.408 44.544 345.600 44.568 ;
    END
  END u_rank__qm_d[184]
  PIN u_rank__qm_d[185]
    DIRECTION INPUT ;
    USE SIGNAL ;
    PORT
      LAYER M4 ;
        RECT 345.408 44.736 345.600 44.760 ;
    END
  END u_rank__qm_d[185]
  PIN u_rank__qm_d[186]
    DIRECTION INPUT ;
    USE SIGNAL ;
    PORT
      LAYER M4 ;
        RECT 345.408 44.880 345.600 44.904 ;
    END
  END u_rank__qm_d[186]
  PIN u_rank__qm_d[187]
    DIRECTION INPUT ;
    USE SIGNAL ;
    PORT
      LAYER M4 ;
        RECT 345.408 45.072 345.600 45.096 ;
    END
  END u_rank__qm_d[187]
  PIN u_rank__qm_d[188]
    DIRECTION INPUT ;
    USE SIGNAL ;
    PORT
      LAYER M4 ;
        RECT 345.408 45.216 345.600 45.240 ;
    END
  END u_rank__qm_d[188]
  PIN u_rank__qm_d[189]
    DIRECTION INPUT ;
    USE SIGNAL ;
    PORT
      LAYER M4 ;
        RECT 345.408 45.408 345.600 45.432 ;
    END
  END u_rank__qm_d[189]
  PIN u_rank__qm_d[18]
    DIRECTION INPUT ;
    USE SIGNAL ;
    PORT
      LAYER M4 ;
        RECT 345.408 16.896 345.600 16.920 ;
    END
  END u_rank__qm_d[18]
  PIN u_rank__qm_d[190]
    DIRECTION INPUT ;
    USE SIGNAL ;
    PORT
      LAYER M4 ;
        RECT 345.408 45.552 345.600 45.576 ;
    END
  END u_rank__qm_d[190]
  PIN u_rank__qm_d[191]
    DIRECTION INPUT ;
    USE SIGNAL ;
    PORT
      LAYER M4 ;
        RECT 345.408 45.744 345.600 45.768 ;
    END
  END u_rank__qm_d[191]
  PIN u_rank__qm_d[192]
    DIRECTION INPUT ;
    USE SIGNAL ;
    PORT
      LAYER M4 ;
        RECT 345.408 45.888 345.600 45.912 ;
    END
  END u_rank__qm_d[192]
  PIN u_rank__qm_d[193]
    DIRECTION INPUT ;
    USE SIGNAL ;
    PORT
      LAYER M4 ;
        RECT 345.408 46.080 345.600 46.104 ;
    END
  END u_rank__qm_d[193]
  PIN u_rank__qm_d[194]
    DIRECTION INPUT ;
    USE SIGNAL ;
    PORT
      LAYER M4 ;
        RECT 345.408 46.224 345.600 46.248 ;
    END
  END u_rank__qm_d[194]
  PIN u_rank__qm_d[195]
    DIRECTION INPUT ;
    USE SIGNAL ;
    PORT
      LAYER M4 ;
        RECT 345.408 46.416 345.600 46.440 ;
    END
  END u_rank__qm_d[195]
  PIN u_rank__qm_d[196]
    DIRECTION INPUT ;
    USE SIGNAL ;
    PORT
      LAYER M4 ;
        RECT 345.408 46.560 345.600 46.584 ;
    END
  END u_rank__qm_d[196]
  PIN u_rank__qm_d[197]
    DIRECTION INPUT ;
    USE SIGNAL ;
    PORT
      LAYER M4 ;
        RECT 345.408 46.752 345.600 46.776 ;
    END
  END u_rank__qm_d[197]
  PIN u_rank__qm_d[198]
    DIRECTION INPUT ;
    USE SIGNAL ;
    PORT
      LAYER M4 ;
        RECT 345.408 46.896 345.600 46.920 ;
    END
  END u_rank__qm_d[198]
  PIN u_rank__qm_d[199]
    DIRECTION INPUT ;
    USE SIGNAL ;
    PORT
      LAYER M4 ;
        RECT 345.408 47.040 345.600 47.064 ;
    END
  END u_rank__qm_d[199]
  PIN u_rank__qm_d[19]
    DIRECTION INPUT ;
    USE SIGNAL ;
    PORT
      LAYER M4 ;
        RECT 345.408 17.040 345.600 17.064 ;
    END
  END u_rank__qm_d[19]
  PIN u_rank__qm_d[1]
    DIRECTION INPUT ;
    USE SIGNAL ;
    PORT
      LAYER M4 ;
        RECT 345.408 14.064 345.600 14.088 ;
    END
  END u_rank__qm_d[1]
  PIN u_rank__qm_d[200]
    DIRECTION INPUT ;
    USE SIGNAL ;
    PORT
      LAYER M4 ;
        RECT 345.408 47.232 345.600 47.256 ;
    END
  END u_rank__qm_d[200]
  PIN u_rank__qm_d[201]
    DIRECTION INPUT ;
    USE SIGNAL ;
    PORT
      LAYER M4 ;
        RECT 345.408 47.376 345.600 47.400 ;
    END
  END u_rank__qm_d[201]
  PIN u_rank__qm_d[202]
    DIRECTION INPUT ;
    USE SIGNAL ;
    PORT
      LAYER M4 ;
        RECT 345.408 47.568 345.600 47.592 ;
    END
  END u_rank__qm_d[202]
  PIN u_rank__qm_d[203]
    DIRECTION INPUT ;
    USE SIGNAL ;
    PORT
      LAYER M4 ;
        RECT 345.408 47.712 345.600 47.736 ;
    END
  END u_rank__qm_d[203]
  PIN u_rank__qm_d[204]
    DIRECTION INPUT ;
    USE SIGNAL ;
    PORT
      LAYER M4 ;
        RECT 345.408 47.904 345.600 47.928 ;
    END
  END u_rank__qm_d[204]
  PIN u_rank__qm_d[205]
    DIRECTION INPUT ;
    USE SIGNAL ;
    PORT
      LAYER M4 ;
        RECT 345.408 48.048 345.600 48.072 ;
    END
  END u_rank__qm_d[205]
  PIN u_rank__qm_d[206]
    DIRECTION INPUT ;
    USE SIGNAL ;
    PORT
      LAYER M4 ;
        RECT 345.408 48.240 345.600 48.264 ;
    END
  END u_rank__qm_d[206]
  PIN u_rank__qm_d[207]
    DIRECTION INPUT ;
    USE SIGNAL ;
    PORT
      LAYER M4 ;
        RECT 345.408 48.384 345.600 48.408 ;
    END
  END u_rank__qm_d[207]
  PIN u_rank__qm_d[208]
    DIRECTION INPUT ;
    USE SIGNAL ;
    PORT
      LAYER M4 ;
        RECT 345.408 48.576 345.600 48.600 ;
    END
  END u_rank__qm_d[208]
  PIN u_rank__qm_d[209]
    DIRECTION INPUT ;
    USE SIGNAL ;
    PORT
      LAYER M4 ;
        RECT 345.408 48.720 345.600 48.744 ;
    END
  END u_rank__qm_d[209]
  PIN u_rank__qm_d[20]
    DIRECTION INPUT ;
    USE SIGNAL ;
    PORT
      LAYER M4 ;
        RECT 345.408 17.232 345.600 17.256 ;
    END
  END u_rank__qm_d[20]
  PIN u_rank__qm_d[210]
    DIRECTION INPUT ;
    USE SIGNAL ;
    PORT
      LAYER M4 ;
        RECT 345.408 48.912 345.600 48.936 ;
    END
  END u_rank__qm_d[210]
  PIN u_rank__qm_d[211]
    DIRECTION INPUT ;
    USE SIGNAL ;
    PORT
      LAYER M4 ;
        RECT 345.408 49.056 345.600 49.080 ;
    END
  END u_rank__qm_d[211]
  PIN u_rank__qm_d[212]
    DIRECTION INPUT ;
    USE SIGNAL ;
    PORT
      LAYER M4 ;
        RECT 345.408 49.248 345.600 49.272 ;
    END
  END u_rank__qm_d[212]
  PIN u_rank__qm_d[213]
    DIRECTION INPUT ;
    USE SIGNAL ;
    PORT
      LAYER M4 ;
        RECT 345.408 49.392 345.600 49.416 ;
    END
  END u_rank__qm_d[213]
  PIN u_rank__qm_d[214]
    DIRECTION INPUT ;
    USE SIGNAL ;
    PORT
      LAYER M4 ;
        RECT 345.408 49.584 345.600 49.608 ;
    END
  END u_rank__qm_d[214]
  PIN u_rank__qm_d[215]
    DIRECTION INPUT ;
    USE SIGNAL ;
    PORT
      LAYER M4 ;
        RECT 345.408 49.728 345.600 49.752 ;
    END
  END u_rank__qm_d[215]
  PIN u_rank__qm_d[216]
    DIRECTION INPUT ;
    USE SIGNAL ;
    PORT
      LAYER M4 ;
        RECT 345.408 49.872 345.600 49.896 ;
    END
  END u_rank__qm_d[216]
  PIN u_rank__qm_d[217]
    DIRECTION INPUT ;
    USE SIGNAL ;
    PORT
      LAYER M4 ;
        RECT 345.408 50.064 345.600 50.088 ;
    END
  END u_rank__qm_d[217]
  PIN u_rank__qm_d[218]
    DIRECTION INPUT ;
    USE SIGNAL ;
    PORT
      LAYER M4 ;
        RECT 345.408 50.208 345.600 50.232 ;
    END
  END u_rank__qm_d[218]
  PIN u_rank__qm_d[219]
    DIRECTION INPUT ;
    USE SIGNAL ;
    PORT
      LAYER M4 ;
        RECT 345.408 50.400 345.600 50.424 ;
    END
  END u_rank__qm_d[219]
  PIN u_rank__qm_d[21]
    DIRECTION INPUT ;
    USE SIGNAL ;
    PORT
      LAYER M4 ;
        RECT 345.408 17.376 345.600 17.400 ;
    END
  END u_rank__qm_d[21]
  PIN u_rank__qm_d[220]
    DIRECTION INPUT ;
    USE SIGNAL ;
    PORT
      LAYER M4 ;
        RECT 345.408 50.544 345.600 50.568 ;
    END
  END u_rank__qm_d[220]
  PIN u_rank__qm_d[221]
    DIRECTION INPUT ;
    USE SIGNAL ;
    PORT
      LAYER M4 ;
        RECT 345.408 50.736 345.600 50.760 ;
    END
  END u_rank__qm_d[221]
  PIN u_rank__qm_d[222]
    DIRECTION INPUT ;
    USE SIGNAL ;
    PORT
      LAYER M4 ;
        RECT 345.408 50.880 345.600 50.904 ;
    END
  END u_rank__qm_d[222]
  PIN u_rank__qm_d[223]
    DIRECTION INPUT ;
    USE SIGNAL ;
    PORT
      LAYER M4 ;
        RECT 345.408 51.072 345.600 51.096 ;
    END
  END u_rank__qm_d[223]
  PIN u_rank__qm_d[224]
    DIRECTION INPUT ;
    USE SIGNAL ;
    PORT
      LAYER M4 ;
        RECT 345.408 51.216 345.600 51.240 ;
    END
  END u_rank__qm_d[224]
  PIN u_rank__qm_d[225]
    DIRECTION INPUT ;
    USE SIGNAL ;
    PORT
      LAYER M4 ;
        RECT 345.408 51.408 345.600 51.432 ;
    END
  END u_rank__qm_d[225]
  PIN u_rank__qm_d[226]
    DIRECTION INPUT ;
    USE SIGNAL ;
    PORT
      LAYER M4 ;
        RECT 345.408 51.552 345.600 51.576 ;
    END
  END u_rank__qm_d[226]
  PIN u_rank__qm_d[227]
    DIRECTION INPUT ;
    USE SIGNAL ;
    PORT
      LAYER M4 ;
        RECT 345.408 51.744 345.600 51.768 ;
    END
  END u_rank__qm_d[227]
  PIN u_rank__qm_d[228]
    DIRECTION INPUT ;
    USE SIGNAL ;
    PORT
      LAYER M4 ;
        RECT 345.408 51.888 345.600 51.912 ;
    END
  END u_rank__qm_d[228]
  PIN u_rank__qm_d[229]
    DIRECTION INPUT ;
    USE SIGNAL ;
    PORT
      LAYER M4 ;
        RECT 345.408 52.080 345.600 52.104 ;
    END
  END u_rank__qm_d[229]
  PIN u_rank__qm_d[22]
    DIRECTION INPUT ;
    USE SIGNAL ;
    PORT
      LAYER M4 ;
        RECT 345.408 17.568 345.600 17.592 ;
    END
  END u_rank__qm_d[22]
  PIN u_rank__qm_d[230]
    DIRECTION INPUT ;
    USE SIGNAL ;
    PORT
      LAYER M4 ;
        RECT 345.408 52.224 345.600 52.248 ;
    END
  END u_rank__qm_d[230]
  PIN u_rank__qm_d[231]
    DIRECTION INPUT ;
    USE SIGNAL ;
    PORT
      LAYER M4 ;
        RECT 345.408 52.416 345.600 52.440 ;
    END
  END u_rank__qm_d[231]
  PIN u_rank__qm_d[232]
    DIRECTION INPUT ;
    USE SIGNAL ;
    PORT
      LAYER M4 ;
        RECT 345.408 52.560 345.600 52.584 ;
    END
  END u_rank__qm_d[232]
  PIN u_rank__qm_d[233]
    DIRECTION INPUT ;
    USE SIGNAL ;
    PORT
      LAYER M4 ;
        RECT 345.408 52.752 345.600 52.776 ;
    END
  END u_rank__qm_d[233]
  PIN u_rank__qm_d[234]
    DIRECTION INPUT ;
    USE SIGNAL ;
    PORT
      LAYER M4 ;
        RECT 345.408 52.896 345.600 52.920 ;
    END
  END u_rank__qm_d[234]
  PIN u_rank__qm_d[235]
    DIRECTION INPUT ;
    USE SIGNAL ;
    PORT
      LAYER M4 ;
        RECT 345.408 53.040 345.600 53.064 ;
    END
  END u_rank__qm_d[235]
  PIN u_rank__qm_d[236]
    DIRECTION INPUT ;
    USE SIGNAL ;
    PORT
      LAYER M4 ;
        RECT 345.408 53.232 345.600 53.256 ;
    END
  END u_rank__qm_d[236]
  PIN u_rank__qm_d[237]
    DIRECTION INPUT ;
    USE SIGNAL ;
    PORT
      LAYER M4 ;
        RECT 345.408 53.376 345.600 53.400 ;
    END
  END u_rank__qm_d[237]
  PIN u_rank__qm_d[238]
    DIRECTION INPUT ;
    USE SIGNAL ;
    PORT
      LAYER M4 ;
        RECT 345.408 53.568 345.600 53.592 ;
    END
  END u_rank__qm_d[238]
  PIN u_rank__qm_d[239]
    DIRECTION INPUT ;
    USE SIGNAL ;
    PORT
      LAYER M4 ;
        RECT 345.408 53.712 345.600 53.736 ;
    END
  END u_rank__qm_d[239]
  PIN u_rank__qm_d[23]
    DIRECTION INPUT ;
    USE SIGNAL ;
    PORT
      LAYER M4 ;
        RECT 345.408 17.712 345.600 17.736 ;
    END
  END u_rank__qm_d[23]
  PIN u_rank__qm_d[240]
    DIRECTION INPUT ;
    USE SIGNAL ;
    PORT
      LAYER M4 ;
        RECT 345.408 53.904 345.600 53.928 ;
    END
  END u_rank__qm_d[240]
  PIN u_rank__qm_d[241]
    DIRECTION INPUT ;
    USE SIGNAL ;
    PORT
      LAYER M4 ;
        RECT 345.408 54.048 345.600 54.072 ;
    END
  END u_rank__qm_d[241]
  PIN u_rank__qm_d[242]
    DIRECTION INPUT ;
    USE SIGNAL ;
    PORT
      LAYER M4 ;
        RECT 345.408 54.240 345.600 54.264 ;
    END
  END u_rank__qm_d[242]
  PIN u_rank__qm_d[243]
    DIRECTION INPUT ;
    USE SIGNAL ;
    PORT
      LAYER M4 ;
        RECT 345.408 54.384 345.600 54.408 ;
    END
  END u_rank__qm_d[243]
  PIN u_rank__qm_d[244]
    DIRECTION INPUT ;
    USE SIGNAL ;
    PORT
      LAYER M4 ;
        RECT 345.408 54.576 345.600 54.600 ;
    END
  END u_rank__qm_d[244]
  PIN u_rank__qm_d[245]
    DIRECTION INPUT ;
    USE SIGNAL ;
    PORT
      LAYER M4 ;
        RECT 345.408 54.720 345.600 54.744 ;
    END
  END u_rank__qm_d[245]
  PIN u_rank__qm_d[246]
    DIRECTION INPUT ;
    USE SIGNAL ;
    PORT
      LAYER M4 ;
        RECT 345.408 54.912 345.600 54.936 ;
    END
  END u_rank__qm_d[246]
  PIN u_rank__qm_d[247]
    DIRECTION INPUT ;
    USE SIGNAL ;
    PORT
      LAYER M4 ;
        RECT 345.408 55.056 345.600 55.080 ;
    END
  END u_rank__qm_d[247]
  PIN u_rank__qm_d[248]
    DIRECTION INPUT ;
    USE SIGNAL ;
    PORT
      LAYER M4 ;
        RECT 345.408 55.248 345.600 55.272 ;
    END
  END u_rank__qm_d[248]
  PIN u_rank__qm_d[249]
    DIRECTION INPUT ;
    USE SIGNAL ;
    PORT
      LAYER M4 ;
        RECT 345.408 55.392 345.600 55.416 ;
    END
  END u_rank__qm_d[249]
  PIN u_rank__qm_d[24]
    DIRECTION INPUT ;
    USE SIGNAL ;
    PORT
      LAYER M4 ;
        RECT 345.408 17.904 345.600 17.928 ;
    END
  END u_rank__qm_d[24]
  PIN u_rank__qm_d[250]
    DIRECTION INPUT ;
    USE SIGNAL ;
    PORT
      LAYER M4 ;
        RECT 345.408 55.584 345.600 55.608 ;
    END
  END u_rank__qm_d[250]
  PIN u_rank__qm_d[251]
    DIRECTION INPUT ;
    USE SIGNAL ;
    PORT
      LAYER M4 ;
        RECT 345.408 55.728 345.600 55.752 ;
    END
  END u_rank__qm_d[251]
  PIN u_rank__qm_d[252]
    DIRECTION INPUT ;
    USE SIGNAL ;
    PORT
      LAYER M4 ;
        RECT 345.408 55.872 345.600 55.896 ;
    END
  END u_rank__qm_d[252]
  PIN u_rank__qm_d[253]
    DIRECTION INPUT ;
    USE SIGNAL ;
    PORT
      LAYER M4 ;
        RECT 345.408 56.064 345.600 56.088 ;
    END
  END u_rank__qm_d[253]
  PIN u_rank__qm_d[254]
    DIRECTION INPUT ;
    USE SIGNAL ;
    PORT
      LAYER M4 ;
        RECT 345.408 56.208 345.600 56.232 ;
    END
  END u_rank__qm_d[254]
  PIN u_rank__qm_d[255]
    DIRECTION INPUT ;
    USE SIGNAL ;
    PORT
      LAYER M4 ;
        RECT 345.408 56.400 345.600 56.424 ;
    END
  END u_rank__qm_d[255]
  PIN u_rank__qm_d[256]
    DIRECTION INPUT ;
    USE SIGNAL ;
    PORT
      LAYER M4 ;
        RECT 345.408 56.544 345.600 56.568 ;
    END
  END u_rank__qm_d[256]
  PIN u_rank__qm_d[257]
    DIRECTION INPUT ;
    USE SIGNAL ;
    PORT
      LAYER M4 ;
        RECT 345.408 56.736 345.600 56.760 ;
    END
  END u_rank__qm_d[257]
  PIN u_rank__qm_d[258]
    DIRECTION INPUT ;
    USE SIGNAL ;
    PORT
      LAYER M4 ;
        RECT 345.408 56.880 345.600 56.904 ;
    END
  END u_rank__qm_d[258]
  PIN u_rank__qm_d[259]
    DIRECTION INPUT ;
    USE SIGNAL ;
    PORT
      LAYER M4 ;
        RECT 345.408 57.072 345.600 57.096 ;
    END
  END u_rank__qm_d[259]
  PIN u_rank__qm_d[25]
    DIRECTION INPUT ;
    USE SIGNAL ;
    PORT
      LAYER M4 ;
        RECT 345.408 18.048 345.600 18.072 ;
    END
  END u_rank__qm_d[25]
  PIN u_rank__qm_d[260]
    DIRECTION INPUT ;
    USE SIGNAL ;
    PORT
      LAYER M4 ;
        RECT 345.408 57.216 345.600 57.240 ;
    END
  END u_rank__qm_d[260]
  PIN u_rank__qm_d[261]
    DIRECTION INPUT ;
    USE SIGNAL ;
    PORT
      LAYER M4 ;
        RECT 345.408 57.408 345.600 57.432 ;
    END
  END u_rank__qm_d[261]
  PIN u_rank__qm_d[262]
    DIRECTION INPUT ;
    USE SIGNAL ;
    PORT
      LAYER M4 ;
        RECT 345.408 57.552 345.600 57.576 ;
    END
  END u_rank__qm_d[262]
  PIN u_rank__qm_d[263]
    DIRECTION INPUT ;
    USE SIGNAL ;
    PORT
      LAYER M4 ;
        RECT 345.408 57.744 345.600 57.768 ;
    END
  END u_rank__qm_d[263]
  PIN u_rank__qm_d[264]
    DIRECTION INPUT ;
    USE SIGNAL ;
    PORT
      LAYER M4 ;
        RECT 345.408 57.888 345.600 57.912 ;
    END
  END u_rank__qm_d[264]
  PIN u_rank__qm_d[265]
    DIRECTION INPUT ;
    USE SIGNAL ;
    PORT
      LAYER M4 ;
        RECT 345.408 58.080 345.600 58.104 ;
    END
  END u_rank__qm_d[265]
  PIN u_rank__qm_d[266]
    DIRECTION INPUT ;
    USE SIGNAL ;
    PORT
      LAYER M4 ;
        RECT 345.408 58.224 345.600 58.248 ;
    END
  END u_rank__qm_d[266]
  PIN u_rank__qm_d[267]
    DIRECTION INPUT ;
    USE SIGNAL ;
    PORT
      LAYER M4 ;
        RECT 345.408 58.416 345.600 58.440 ;
    END
  END u_rank__qm_d[267]
  PIN u_rank__qm_d[268]
    DIRECTION INPUT ;
    USE SIGNAL ;
    PORT
      LAYER M4 ;
        RECT 345.408 58.560 345.600 58.584 ;
    END
  END u_rank__qm_d[268]
  PIN u_rank__qm_d[269]
    DIRECTION INPUT ;
    USE SIGNAL ;
    PORT
      LAYER M4 ;
        RECT 345.408 58.752 345.600 58.776 ;
    END
  END u_rank__qm_d[269]
  PIN u_rank__qm_d[26]
    DIRECTION INPUT ;
    USE SIGNAL ;
    PORT
      LAYER M4 ;
        RECT 345.408 18.240 345.600 18.264 ;
    END
  END u_rank__qm_d[26]
  PIN u_rank__qm_d[270]
    DIRECTION INPUT ;
    USE SIGNAL ;
    PORT
      LAYER M4 ;
        RECT 345.408 58.896 345.600 58.920 ;
    END
  END u_rank__qm_d[270]
  PIN u_rank__qm_d[271]
    DIRECTION INPUT ;
    USE SIGNAL ;
    PORT
      LAYER M4 ;
        RECT 345.408 59.040 345.600 59.064 ;
    END
  END u_rank__qm_d[271]
  PIN u_rank__qm_d[272]
    DIRECTION INPUT ;
    USE SIGNAL ;
    PORT
      LAYER M4 ;
        RECT 345.408 59.232 345.600 59.256 ;
    END
  END u_rank__qm_d[272]
  PIN u_rank__qm_d[273]
    DIRECTION INPUT ;
    USE SIGNAL ;
    PORT
      LAYER M4 ;
        RECT 345.408 59.376 345.600 59.400 ;
    END
  END u_rank__qm_d[273]
  PIN u_rank__qm_d[274]
    DIRECTION INPUT ;
    USE SIGNAL ;
    PORT
      LAYER M4 ;
        RECT 345.408 59.568 345.600 59.592 ;
    END
  END u_rank__qm_d[274]
  PIN u_rank__qm_d[275]
    DIRECTION INPUT ;
    USE SIGNAL ;
    PORT
      LAYER M4 ;
        RECT 345.408 59.712 345.600 59.736 ;
    END
  END u_rank__qm_d[275]
  PIN u_rank__qm_d[276]
    DIRECTION INPUT ;
    USE SIGNAL ;
    PORT
      LAYER M4 ;
        RECT 345.408 59.904 345.600 59.928 ;
    END
  END u_rank__qm_d[276]
  PIN u_rank__qm_d[277]
    DIRECTION INPUT ;
    USE SIGNAL ;
    PORT
      LAYER M4 ;
        RECT 345.408 60.048 345.600 60.072 ;
    END
  END u_rank__qm_d[277]
  PIN u_rank__qm_d[278]
    DIRECTION INPUT ;
    USE SIGNAL ;
    PORT
      LAYER M4 ;
        RECT 345.408 60.240 345.600 60.264 ;
    END
  END u_rank__qm_d[278]
  PIN u_rank__qm_d[279]
    DIRECTION INPUT ;
    USE SIGNAL ;
    PORT
      LAYER M4 ;
        RECT 345.408 60.384 345.600 60.408 ;
    END
  END u_rank__qm_d[279]
  PIN u_rank__qm_d[27]
    DIRECTION INPUT ;
    USE SIGNAL ;
    PORT
      LAYER M4 ;
        RECT 345.408 18.384 345.600 18.408 ;
    END
  END u_rank__qm_d[27]
  PIN u_rank__qm_d[280]
    DIRECTION INPUT ;
    USE SIGNAL ;
    PORT
      LAYER M4 ;
        RECT 345.408 60.576 345.600 60.600 ;
    END
  END u_rank__qm_d[280]
  PIN u_rank__qm_d[281]
    DIRECTION INPUT ;
    USE SIGNAL ;
    PORT
      LAYER M4 ;
        RECT 345.408 60.720 345.600 60.744 ;
    END
  END u_rank__qm_d[281]
  PIN u_rank__qm_d[282]
    DIRECTION INPUT ;
    USE SIGNAL ;
    PORT
      LAYER M4 ;
        RECT 345.408 60.912 345.600 60.936 ;
    END
  END u_rank__qm_d[282]
  PIN u_rank__qm_d[283]
    DIRECTION INPUT ;
    USE SIGNAL ;
    PORT
      LAYER M4 ;
        RECT 345.408 61.056 345.600 61.080 ;
    END
  END u_rank__qm_d[283]
  PIN u_rank__qm_d[284]
    DIRECTION INPUT ;
    USE SIGNAL ;
    PORT
      LAYER M4 ;
        RECT 345.408 61.248 345.600 61.272 ;
    END
  END u_rank__qm_d[284]
  PIN u_rank__qm_d[285]
    DIRECTION INPUT ;
    USE SIGNAL ;
    PORT
      LAYER M4 ;
        RECT 345.408 61.392 345.600 61.416 ;
    END
  END u_rank__qm_d[285]
  PIN u_rank__qm_d[286]
    DIRECTION INPUT ;
    USE SIGNAL ;
    PORT
      LAYER M4 ;
        RECT 345.408 61.584 345.600 61.608 ;
    END
  END u_rank__qm_d[286]
  PIN u_rank__qm_d[287]
    DIRECTION INPUT ;
    USE SIGNAL ;
    PORT
      LAYER M4 ;
        RECT 345.408 61.728 345.600 61.752 ;
    END
  END u_rank__qm_d[287]
  PIN u_rank__qm_d[288]
    DIRECTION INPUT ;
    USE SIGNAL ;
    PORT
      LAYER M4 ;
        RECT 345.408 61.872 345.600 61.896 ;
    END
  END u_rank__qm_d[288]
  PIN u_rank__qm_d[289]
    DIRECTION INPUT ;
    USE SIGNAL ;
    PORT
      LAYER M4 ;
        RECT 345.408 62.064 345.600 62.088 ;
    END
  END u_rank__qm_d[289]
  PIN u_rank__qm_d[28]
    DIRECTION INPUT ;
    USE SIGNAL ;
    PORT
      LAYER M4 ;
        RECT 345.408 18.576 345.600 18.600 ;
    END
  END u_rank__qm_d[28]
  PIN u_rank__qm_d[290]
    DIRECTION INPUT ;
    USE SIGNAL ;
    PORT
      LAYER M4 ;
        RECT 345.408 62.208 345.600 62.232 ;
    END
  END u_rank__qm_d[290]
  PIN u_rank__qm_d[291]
    DIRECTION INPUT ;
    USE SIGNAL ;
    PORT
      LAYER M4 ;
        RECT 345.408 62.400 345.600 62.424 ;
    END
  END u_rank__qm_d[291]
  PIN u_rank__qm_d[292]
    DIRECTION INPUT ;
    USE SIGNAL ;
    PORT
      LAYER M4 ;
        RECT 345.408 62.544 345.600 62.568 ;
    END
  END u_rank__qm_d[292]
  PIN u_rank__qm_d[293]
    DIRECTION INPUT ;
    USE SIGNAL ;
    PORT
      LAYER M4 ;
        RECT 345.408 62.736 345.600 62.760 ;
    END
  END u_rank__qm_d[293]
  PIN u_rank__qm_d[294]
    DIRECTION INPUT ;
    USE SIGNAL ;
    PORT
      LAYER M4 ;
        RECT 345.408 62.880 345.600 62.904 ;
    END
  END u_rank__qm_d[294]
  PIN u_rank__qm_d[295]
    DIRECTION INPUT ;
    USE SIGNAL ;
    PORT
      LAYER M4 ;
        RECT 345.408 63.072 345.600 63.096 ;
    END
  END u_rank__qm_d[295]
  PIN u_rank__qm_d[296]
    DIRECTION INPUT ;
    USE SIGNAL ;
    PORT
      LAYER M4 ;
        RECT 345.408 63.216 345.600 63.240 ;
    END
  END u_rank__qm_d[296]
  PIN u_rank__qm_d[297]
    DIRECTION INPUT ;
    USE SIGNAL ;
    PORT
      LAYER M4 ;
        RECT 345.408 63.408 345.600 63.432 ;
    END
  END u_rank__qm_d[297]
  PIN u_rank__qm_d[298]
    DIRECTION INPUT ;
    USE SIGNAL ;
    PORT
      LAYER M4 ;
        RECT 345.408 63.552 345.600 63.576 ;
    END
  END u_rank__qm_d[298]
  PIN u_rank__qm_d[299]
    DIRECTION INPUT ;
    USE SIGNAL ;
    PORT
      LAYER M4 ;
        RECT 345.408 63.744 345.600 63.768 ;
    END
  END u_rank__qm_d[299]
  PIN u_rank__qm_d[29]
    DIRECTION INPUT ;
    USE SIGNAL ;
    PORT
      LAYER M4 ;
        RECT 345.408 18.720 345.600 18.744 ;
    END
  END u_rank__qm_d[29]
  PIN u_rank__qm_d[2]
    DIRECTION INPUT ;
    USE SIGNAL ;
    PORT
      LAYER M4 ;
        RECT 345.408 14.208 345.600 14.232 ;
    END
  END u_rank__qm_d[2]
  PIN u_rank__qm_d[300]
    DIRECTION INPUT ;
    USE SIGNAL ;
    PORT
      LAYER M4 ;
        RECT 345.408 63.888 345.600 63.912 ;
    END
  END u_rank__qm_d[300]
  PIN u_rank__qm_d[301]
    DIRECTION INPUT ;
    USE SIGNAL ;
    PORT
      LAYER M4 ;
        RECT 345.408 64.080 345.600 64.104 ;
    END
  END u_rank__qm_d[301]
  PIN u_rank__qm_d[302]
    DIRECTION INPUT ;
    USE SIGNAL ;
    PORT
      LAYER M4 ;
        RECT 345.408 64.224 345.600 64.248 ;
    END
  END u_rank__qm_d[302]
  PIN u_rank__qm_d[303]
    DIRECTION INPUT ;
    USE SIGNAL ;
    PORT
      LAYER M4 ;
        RECT 345.408 64.416 345.600 64.440 ;
    END
  END u_rank__qm_d[303]
  PIN u_rank__qm_d[304]
    DIRECTION INPUT ;
    USE SIGNAL ;
    PORT
      LAYER M4 ;
        RECT 345.408 64.560 345.600 64.584 ;
    END
  END u_rank__qm_d[304]
  PIN u_rank__qm_d[305]
    DIRECTION INPUT ;
    USE SIGNAL ;
    PORT
      LAYER M4 ;
        RECT 345.408 64.752 345.600 64.776 ;
    END
  END u_rank__qm_d[305]
  PIN u_rank__qm_d[306]
    DIRECTION INPUT ;
    USE SIGNAL ;
    PORT
      LAYER M4 ;
        RECT 345.408 64.896 345.600 64.920 ;
    END
  END u_rank__qm_d[306]
  PIN u_rank__qm_d[307]
    DIRECTION INPUT ;
    USE SIGNAL ;
    PORT
      LAYER M4 ;
        RECT 345.408 65.040 345.600 65.064 ;
    END
  END u_rank__qm_d[307]
  PIN u_rank__qm_d[308]
    DIRECTION INPUT ;
    USE SIGNAL ;
    PORT
      LAYER M4 ;
        RECT 345.408 65.232 345.600 65.256 ;
    END
  END u_rank__qm_d[308]
  PIN u_rank__qm_d[309]
    DIRECTION INPUT ;
    USE SIGNAL ;
    PORT
      LAYER M4 ;
        RECT 345.408 65.376 345.600 65.400 ;
    END
  END u_rank__qm_d[309]
  PIN u_rank__qm_d[30]
    DIRECTION INPUT ;
    USE SIGNAL ;
    PORT
      LAYER M4 ;
        RECT 345.408 18.912 345.600 18.936 ;
    END
  END u_rank__qm_d[30]
  PIN u_rank__qm_d[310]
    DIRECTION INPUT ;
    USE SIGNAL ;
    PORT
      LAYER M4 ;
        RECT 345.408 65.568 345.600 65.592 ;
    END
  END u_rank__qm_d[310]
  PIN u_rank__qm_d[311]
    DIRECTION INPUT ;
    USE SIGNAL ;
    PORT
      LAYER M4 ;
        RECT 345.408 65.712 345.600 65.736 ;
    END
  END u_rank__qm_d[311]
  PIN u_rank__qm_d[312]
    DIRECTION INPUT ;
    USE SIGNAL ;
    PORT
      LAYER M4 ;
        RECT 345.408 65.904 345.600 65.928 ;
    END
  END u_rank__qm_d[312]
  PIN u_rank__qm_d[313]
    DIRECTION INPUT ;
    USE SIGNAL ;
    PORT
      LAYER M4 ;
        RECT 345.408 66.048 345.600 66.072 ;
    END
  END u_rank__qm_d[313]
  PIN u_rank__qm_d[314]
    DIRECTION INPUT ;
    USE SIGNAL ;
    PORT
      LAYER M4 ;
        RECT 345.408 66.240 345.600 66.264 ;
    END
  END u_rank__qm_d[314]
  PIN u_rank__qm_d[315]
    DIRECTION INPUT ;
    USE SIGNAL ;
    PORT
      LAYER M4 ;
        RECT 345.408 66.384 345.600 66.408 ;
    END
  END u_rank__qm_d[315]
  PIN u_rank__qm_d[316]
    DIRECTION INPUT ;
    USE SIGNAL ;
    PORT
      LAYER M4 ;
        RECT 345.408 66.576 345.600 66.600 ;
    END
  END u_rank__qm_d[316]
  PIN u_rank__qm_d[317]
    DIRECTION INPUT ;
    USE SIGNAL ;
    PORT
      LAYER M4 ;
        RECT 345.408 66.720 345.600 66.744 ;
    END
  END u_rank__qm_d[317]
  PIN u_rank__qm_d[318]
    DIRECTION INPUT ;
    USE SIGNAL ;
    PORT
      LAYER M4 ;
        RECT 345.408 66.912 345.600 66.936 ;
    END
  END u_rank__qm_d[318]
  PIN u_rank__qm_d[319]
    DIRECTION INPUT ;
    USE SIGNAL ;
    PORT
      LAYER M4 ;
        RECT 345.408 67.056 345.600 67.080 ;
    END
  END u_rank__qm_d[319]
  PIN u_rank__qm_d[31]
    DIRECTION INPUT ;
    USE SIGNAL ;
    PORT
      LAYER M4 ;
        RECT 345.408 19.056 345.600 19.080 ;
    END
  END u_rank__qm_d[31]
  PIN u_rank__qm_d[320]
    DIRECTION INPUT ;
    USE SIGNAL ;
    PORT
      LAYER M4 ;
        RECT 345.408 67.248 345.600 67.272 ;
    END
  END u_rank__qm_d[320]
  PIN u_rank__qm_d[321]
    DIRECTION INPUT ;
    USE SIGNAL ;
    PORT
      LAYER M4 ;
        RECT 345.408 67.392 345.600 67.416 ;
    END
  END u_rank__qm_d[321]
  PIN u_rank__qm_d[322]
    DIRECTION INPUT ;
    USE SIGNAL ;
    PORT
      LAYER M4 ;
        RECT 345.408 67.584 345.600 67.608 ;
    END
  END u_rank__qm_d[322]
  PIN u_rank__qm_d[323]
    DIRECTION INPUT ;
    USE SIGNAL ;
    PORT
      LAYER M4 ;
        RECT 345.408 67.728 345.600 67.752 ;
    END
  END u_rank__qm_d[323]
  PIN u_rank__qm_d[324]
    DIRECTION INPUT ;
    USE SIGNAL ;
    PORT
      LAYER M4 ;
        RECT 345.408 67.872 345.600 67.896 ;
    END
  END u_rank__qm_d[324]
  PIN u_rank__qm_d[325]
    DIRECTION INPUT ;
    USE SIGNAL ;
    PORT
      LAYER M4 ;
        RECT 345.408 68.064 345.600 68.088 ;
    END
  END u_rank__qm_d[325]
  PIN u_rank__qm_d[326]
    DIRECTION INPUT ;
    USE SIGNAL ;
    PORT
      LAYER M4 ;
        RECT 345.408 68.208 345.600 68.232 ;
    END
  END u_rank__qm_d[326]
  PIN u_rank__qm_d[327]
    DIRECTION INPUT ;
    USE SIGNAL ;
    PORT
      LAYER M4 ;
        RECT 345.408 68.400 345.600 68.424 ;
    END
  END u_rank__qm_d[327]
  PIN u_rank__qm_d[328]
    DIRECTION INPUT ;
    USE SIGNAL ;
    PORT
      LAYER M4 ;
        RECT 345.408 68.544 345.600 68.568 ;
    END
  END u_rank__qm_d[328]
  PIN u_rank__qm_d[329]
    DIRECTION INPUT ;
    USE SIGNAL ;
    PORT
      LAYER M4 ;
        RECT 345.408 68.736 345.600 68.760 ;
    END
  END u_rank__qm_d[329]
  PIN u_rank__qm_d[32]
    DIRECTION INPUT ;
    USE SIGNAL ;
    PORT
      LAYER M4 ;
        RECT 345.408 19.248 345.600 19.272 ;
    END
  END u_rank__qm_d[32]
  PIN u_rank__qm_d[330]
    DIRECTION INPUT ;
    USE SIGNAL ;
    PORT
      LAYER M4 ;
        RECT 345.408 68.880 345.600 68.904 ;
    END
  END u_rank__qm_d[330]
  PIN u_rank__qm_d[331]
    DIRECTION INPUT ;
    USE SIGNAL ;
    PORT
      LAYER M4 ;
        RECT 345.408 69.072 345.600 69.096 ;
    END
  END u_rank__qm_d[331]
  PIN u_rank__qm_d[332]
    DIRECTION INPUT ;
    USE SIGNAL ;
    PORT
      LAYER M4 ;
        RECT 345.408 69.216 345.600 69.240 ;
    END
  END u_rank__qm_d[332]
  PIN u_rank__qm_d[333]
    DIRECTION INPUT ;
    USE SIGNAL ;
    PORT
      LAYER M4 ;
        RECT 345.408 69.408 345.600 69.432 ;
    END
  END u_rank__qm_d[333]
  PIN u_rank__qm_d[334]
    DIRECTION INPUT ;
    USE SIGNAL ;
    PORT
      LAYER M4 ;
        RECT 345.408 69.552 345.600 69.576 ;
    END
  END u_rank__qm_d[334]
  PIN u_rank__qm_d[335]
    DIRECTION INPUT ;
    USE SIGNAL ;
    PORT
      LAYER M4 ;
        RECT 345.408 69.744 345.600 69.768 ;
    END
  END u_rank__qm_d[335]
  PIN u_rank__qm_d[336]
    DIRECTION INPUT ;
    USE SIGNAL ;
    PORT
      LAYER M4 ;
        RECT 345.408 69.888 345.600 69.912 ;
    END
  END u_rank__qm_d[336]
  PIN u_rank__qm_d[337]
    DIRECTION INPUT ;
    USE SIGNAL ;
    PORT
      LAYER M4 ;
        RECT 345.408 70.080 345.600 70.104 ;
    END
  END u_rank__qm_d[337]
  PIN u_rank__qm_d[338]
    DIRECTION INPUT ;
    USE SIGNAL ;
    PORT
      LAYER M4 ;
        RECT 345.408 70.224 345.600 70.248 ;
    END
  END u_rank__qm_d[338]
  PIN u_rank__qm_d[339]
    DIRECTION INPUT ;
    USE SIGNAL ;
    PORT
      LAYER M4 ;
        RECT 345.408 70.416 345.600 70.440 ;
    END
  END u_rank__qm_d[339]
  PIN u_rank__qm_d[33]
    DIRECTION INPUT ;
    USE SIGNAL ;
    PORT
      LAYER M4 ;
        RECT 345.408 19.392 345.600 19.416 ;
    END
  END u_rank__qm_d[33]
  PIN u_rank__qm_d[340]
    DIRECTION INPUT ;
    USE SIGNAL ;
    PORT
      LAYER M4 ;
        RECT 345.408 70.560 345.600 70.584 ;
    END
  END u_rank__qm_d[340]
  PIN u_rank__qm_d[341]
    DIRECTION INPUT ;
    USE SIGNAL ;
    PORT
      LAYER M4 ;
        RECT 345.408 70.752 345.600 70.776 ;
    END
  END u_rank__qm_d[341]
  PIN u_rank__qm_d[342]
    DIRECTION INPUT ;
    USE SIGNAL ;
    PORT
      LAYER M4 ;
        RECT 345.408 70.896 345.600 70.920 ;
    END
  END u_rank__qm_d[342]
  PIN u_rank__qm_d[343]
    DIRECTION INPUT ;
    USE SIGNAL ;
    PORT
      LAYER M4 ;
        RECT 345.408 71.040 345.600 71.064 ;
    END
  END u_rank__qm_d[343]
  PIN u_rank__qm_d[344]
    DIRECTION INPUT ;
    USE SIGNAL ;
    PORT
      LAYER M4 ;
        RECT 345.408 71.232 345.600 71.256 ;
    END
  END u_rank__qm_d[344]
  PIN u_rank__qm_d[345]
    DIRECTION INPUT ;
    USE SIGNAL ;
    PORT
      LAYER M4 ;
        RECT 345.408 71.376 345.600 71.400 ;
    END
  END u_rank__qm_d[345]
  PIN u_rank__qm_d[346]
    DIRECTION INPUT ;
    USE SIGNAL ;
    PORT
      LAYER M4 ;
        RECT 345.408 71.568 345.600 71.592 ;
    END
  END u_rank__qm_d[346]
  PIN u_rank__qm_d[347]
    DIRECTION INPUT ;
    USE SIGNAL ;
    PORT
      LAYER M4 ;
        RECT 345.408 71.712 345.600 71.736 ;
    END
  END u_rank__qm_d[347]
  PIN u_rank__qm_d[348]
    DIRECTION INPUT ;
    USE SIGNAL ;
    PORT
      LAYER M4 ;
        RECT 345.408 71.904 345.600 71.928 ;
    END
  END u_rank__qm_d[348]
  PIN u_rank__qm_d[349]
    DIRECTION INPUT ;
    USE SIGNAL ;
    PORT
      LAYER M4 ;
        RECT 345.408 72.048 345.600 72.072 ;
    END
  END u_rank__qm_d[349]
  PIN u_rank__qm_d[34]
    DIRECTION INPUT ;
    USE SIGNAL ;
    PORT
      LAYER M4 ;
        RECT 345.408 19.584 345.600 19.608 ;
    END
  END u_rank__qm_d[34]
  PIN u_rank__qm_d[350]
    DIRECTION INPUT ;
    USE SIGNAL ;
    PORT
      LAYER M4 ;
        RECT 345.408 72.240 345.600 72.264 ;
    END
  END u_rank__qm_d[350]
  PIN u_rank__qm_d[351]
    DIRECTION INPUT ;
    USE SIGNAL ;
    PORT
      LAYER M4 ;
        RECT 345.408 72.384 345.600 72.408 ;
    END
  END u_rank__qm_d[351]
  PIN u_rank__qm_d[352]
    DIRECTION INPUT ;
    USE SIGNAL ;
    PORT
      LAYER M4 ;
        RECT 345.408 72.576 345.600 72.600 ;
    END
  END u_rank__qm_d[352]
  PIN u_rank__qm_d[353]
    DIRECTION INPUT ;
    USE SIGNAL ;
    PORT
      LAYER M4 ;
        RECT 345.408 72.720 345.600 72.744 ;
    END
  END u_rank__qm_d[353]
  PIN u_rank__qm_d[354]
    DIRECTION INPUT ;
    USE SIGNAL ;
    PORT
      LAYER M4 ;
        RECT 345.408 72.912 345.600 72.936 ;
    END
  END u_rank__qm_d[354]
  PIN u_rank__qm_d[355]
    DIRECTION INPUT ;
    USE SIGNAL ;
    PORT
      LAYER M4 ;
        RECT 345.408 73.056 345.600 73.080 ;
    END
  END u_rank__qm_d[355]
  PIN u_rank__qm_d[356]
    DIRECTION INPUT ;
    USE SIGNAL ;
    PORT
      LAYER M4 ;
        RECT 345.408 73.248 345.600 73.272 ;
    END
  END u_rank__qm_d[356]
  PIN u_rank__qm_d[357]
    DIRECTION INPUT ;
    USE SIGNAL ;
    PORT
      LAYER M4 ;
        RECT 345.408 73.392 345.600 73.416 ;
    END
  END u_rank__qm_d[357]
  PIN u_rank__qm_d[358]
    DIRECTION INPUT ;
    USE SIGNAL ;
    PORT
      LAYER M4 ;
        RECT 345.408 73.584 345.600 73.608 ;
    END
  END u_rank__qm_d[358]
  PIN u_rank__qm_d[359]
    DIRECTION INPUT ;
    USE SIGNAL ;
    PORT
      LAYER M4 ;
        RECT 345.408 73.728 345.600 73.752 ;
    END
  END u_rank__qm_d[359]
  PIN u_rank__qm_d[35]
    DIRECTION INPUT ;
    USE SIGNAL ;
    PORT
      LAYER M4 ;
        RECT 345.408 19.728 345.600 19.752 ;
    END
  END u_rank__qm_d[35]
  PIN u_rank__qm_d[360]
    DIRECTION INPUT ;
    USE SIGNAL ;
    PORT
      LAYER M4 ;
        RECT 345.408 73.872 345.600 73.896 ;
    END
  END u_rank__qm_d[360]
  PIN u_rank__qm_d[361]
    DIRECTION INPUT ;
    USE SIGNAL ;
    PORT
      LAYER M4 ;
        RECT 345.408 74.064 345.600 74.088 ;
    END
  END u_rank__qm_d[361]
  PIN u_rank__qm_d[362]
    DIRECTION INPUT ;
    USE SIGNAL ;
    PORT
      LAYER M4 ;
        RECT 345.408 74.208 345.600 74.232 ;
    END
  END u_rank__qm_d[362]
  PIN u_rank__qm_d[363]
    DIRECTION INPUT ;
    USE SIGNAL ;
    PORT
      LAYER M4 ;
        RECT 345.408 74.400 345.600 74.424 ;
    END
  END u_rank__qm_d[363]
  PIN u_rank__qm_d[364]
    DIRECTION INPUT ;
    USE SIGNAL ;
    PORT
      LAYER M4 ;
        RECT 345.408 74.544 345.600 74.568 ;
    END
  END u_rank__qm_d[364]
  PIN u_rank__qm_d[365]
    DIRECTION INPUT ;
    USE SIGNAL ;
    PORT
      LAYER M4 ;
        RECT 345.408 74.736 345.600 74.760 ;
    END
  END u_rank__qm_d[365]
  PIN u_rank__qm_d[366]
    DIRECTION INPUT ;
    USE SIGNAL ;
    PORT
      LAYER M4 ;
        RECT 345.408 74.880 345.600 74.904 ;
    END
  END u_rank__qm_d[366]
  PIN u_rank__qm_d[367]
    DIRECTION INPUT ;
    USE SIGNAL ;
    PORT
      LAYER M4 ;
        RECT 345.408 75.072 345.600 75.096 ;
    END
  END u_rank__qm_d[367]
  PIN u_rank__qm_d[368]
    DIRECTION INPUT ;
    USE SIGNAL ;
    PORT
      LAYER M4 ;
        RECT 345.408 75.216 345.600 75.240 ;
    END
  END u_rank__qm_d[368]
  PIN u_rank__qm_d[369]
    DIRECTION INPUT ;
    USE SIGNAL ;
    PORT
      LAYER M4 ;
        RECT 345.408 75.408 345.600 75.432 ;
    END
  END u_rank__qm_d[369]
  PIN u_rank__qm_d[36]
    DIRECTION INPUT ;
    USE SIGNAL ;
    PORT
      LAYER M4 ;
        RECT 345.408 19.872 345.600 19.896 ;
    END
  END u_rank__qm_d[36]
  PIN u_rank__qm_d[370]
    DIRECTION INPUT ;
    USE SIGNAL ;
    PORT
      LAYER M4 ;
        RECT 345.408 75.552 345.600 75.576 ;
    END
  END u_rank__qm_d[370]
  PIN u_rank__qm_d[371]
    DIRECTION INPUT ;
    USE SIGNAL ;
    PORT
      LAYER M4 ;
        RECT 345.408 75.744 345.600 75.768 ;
    END
  END u_rank__qm_d[371]
  PIN u_rank__qm_d[372]
    DIRECTION INPUT ;
    USE SIGNAL ;
    PORT
      LAYER M4 ;
        RECT 345.408 75.888 345.600 75.912 ;
    END
  END u_rank__qm_d[372]
  PIN u_rank__qm_d[373]
    DIRECTION INPUT ;
    USE SIGNAL ;
    PORT
      LAYER M4 ;
        RECT 345.408 76.080 345.600 76.104 ;
    END
  END u_rank__qm_d[373]
  PIN u_rank__qm_d[374]
    DIRECTION INPUT ;
    USE SIGNAL ;
    PORT
      LAYER M4 ;
        RECT 345.408 76.224 345.600 76.248 ;
    END
  END u_rank__qm_d[374]
  PIN u_rank__qm_d[375]
    DIRECTION INPUT ;
    USE SIGNAL ;
    PORT
      LAYER M4 ;
        RECT 345.408 76.416 345.600 76.440 ;
    END
  END u_rank__qm_d[375]
  PIN u_rank__qm_d[376]
    DIRECTION INPUT ;
    USE SIGNAL ;
    PORT
      LAYER M4 ;
        RECT 345.408 76.560 345.600 76.584 ;
    END
  END u_rank__qm_d[376]
  PIN u_rank__qm_d[377]
    DIRECTION INPUT ;
    USE SIGNAL ;
    PORT
      LAYER M4 ;
        RECT 345.408 76.752 345.600 76.776 ;
    END
  END u_rank__qm_d[377]
  PIN u_rank__qm_d[378]
    DIRECTION INPUT ;
    USE SIGNAL ;
    PORT
      LAYER M4 ;
        RECT 345.408 76.896 345.600 76.920 ;
    END
  END u_rank__qm_d[378]
  PIN u_rank__qm_d[379]
    DIRECTION INPUT ;
    USE SIGNAL ;
    PORT
      LAYER M4 ;
        RECT 345.408 77.040 345.600 77.064 ;
    END
  END u_rank__qm_d[379]
  PIN u_rank__qm_d[37]
    DIRECTION INPUT ;
    USE SIGNAL ;
    PORT
      LAYER M4 ;
        RECT 345.408 20.064 345.600 20.088 ;
    END
  END u_rank__qm_d[37]
  PIN u_rank__qm_d[380]
    DIRECTION INPUT ;
    USE SIGNAL ;
    PORT
      LAYER M4 ;
        RECT 345.408 77.232 345.600 77.256 ;
    END
  END u_rank__qm_d[380]
  PIN u_rank__qm_d[381]
    DIRECTION INPUT ;
    USE SIGNAL ;
    PORT
      LAYER M4 ;
        RECT 345.408 77.376 345.600 77.400 ;
    END
  END u_rank__qm_d[381]
  PIN u_rank__qm_d[382]
    DIRECTION INPUT ;
    USE SIGNAL ;
    PORT
      LAYER M4 ;
        RECT 345.408 77.568 345.600 77.592 ;
    END
  END u_rank__qm_d[382]
  PIN u_rank__qm_d[383]
    DIRECTION INPUT ;
    USE SIGNAL ;
    PORT
      LAYER M4 ;
        RECT 345.408 77.712 345.600 77.736 ;
    END
  END u_rank__qm_d[383]
  PIN u_rank__qm_d[384]
    DIRECTION INPUT ;
    USE SIGNAL ;
    PORT
      LAYER M4 ;
        RECT 345.408 77.904 345.600 77.928 ;
    END
  END u_rank__qm_d[384]
  PIN u_rank__qm_d[385]
    DIRECTION INPUT ;
    USE SIGNAL ;
    PORT
      LAYER M4 ;
        RECT 345.408 78.048 345.600 78.072 ;
    END
  END u_rank__qm_d[385]
  PIN u_rank__qm_d[386]
    DIRECTION INPUT ;
    USE SIGNAL ;
    PORT
      LAYER M4 ;
        RECT 345.408 78.240 345.600 78.264 ;
    END
  END u_rank__qm_d[386]
  PIN u_rank__qm_d[387]
    DIRECTION INPUT ;
    USE SIGNAL ;
    PORT
      LAYER M4 ;
        RECT 345.408 78.384 345.600 78.408 ;
    END
  END u_rank__qm_d[387]
  PIN u_rank__qm_d[388]
    DIRECTION INPUT ;
    USE SIGNAL ;
    PORT
      LAYER M4 ;
        RECT 345.408 78.576 345.600 78.600 ;
    END
  END u_rank__qm_d[388]
  PIN u_rank__qm_d[389]
    DIRECTION INPUT ;
    USE SIGNAL ;
    PORT
      LAYER M4 ;
        RECT 345.408 78.720 345.600 78.744 ;
    END
  END u_rank__qm_d[389]
  PIN u_rank__qm_d[38]
    DIRECTION INPUT ;
    USE SIGNAL ;
    PORT
      LAYER M4 ;
        RECT 345.408 20.208 345.600 20.232 ;
    END
  END u_rank__qm_d[38]
  PIN u_rank__qm_d[390]
    DIRECTION INPUT ;
    USE SIGNAL ;
    PORT
      LAYER M4 ;
        RECT 345.408 78.912 345.600 78.936 ;
    END
  END u_rank__qm_d[390]
  PIN u_rank__qm_d[391]
    DIRECTION INPUT ;
    USE SIGNAL ;
    PORT
      LAYER M4 ;
        RECT 345.408 79.056 345.600 79.080 ;
    END
  END u_rank__qm_d[391]
  PIN u_rank__qm_d[392]
    DIRECTION INPUT ;
    USE SIGNAL ;
    PORT
      LAYER M4 ;
        RECT 345.408 79.248 345.600 79.272 ;
    END
  END u_rank__qm_d[392]
  PIN u_rank__qm_d[393]
    DIRECTION INPUT ;
    USE SIGNAL ;
    PORT
      LAYER M4 ;
        RECT 345.408 79.392 345.600 79.416 ;
    END
  END u_rank__qm_d[393]
  PIN u_rank__qm_d[394]
    DIRECTION INPUT ;
    USE SIGNAL ;
    PORT
      LAYER M4 ;
        RECT 345.408 79.584 345.600 79.608 ;
    END
  END u_rank__qm_d[394]
  PIN u_rank__qm_d[395]
    DIRECTION INPUT ;
    USE SIGNAL ;
    PORT
      LAYER M4 ;
        RECT 345.408 79.728 345.600 79.752 ;
    END
  END u_rank__qm_d[395]
  PIN u_rank__qm_d[396]
    DIRECTION INPUT ;
    USE SIGNAL ;
    PORT
      LAYER M4 ;
        RECT 345.408 79.872 345.600 79.896 ;
    END
  END u_rank__qm_d[396]
  PIN u_rank__qm_d[397]
    DIRECTION INPUT ;
    USE SIGNAL ;
    PORT
      LAYER M4 ;
        RECT 345.408 80.064 345.600 80.088 ;
    END
  END u_rank__qm_d[397]
  PIN u_rank__qm_d[398]
    DIRECTION INPUT ;
    USE SIGNAL ;
    PORT
      LAYER M4 ;
        RECT 345.408 80.208 345.600 80.232 ;
    END
  END u_rank__qm_d[398]
  PIN u_rank__qm_d[399]
    DIRECTION INPUT ;
    USE SIGNAL ;
    PORT
      LAYER M4 ;
        RECT 345.408 80.400 345.600 80.424 ;
    END
  END u_rank__qm_d[399]
  PIN u_rank__qm_d[39]
    DIRECTION INPUT ;
    USE SIGNAL ;
    PORT
      LAYER M4 ;
        RECT 345.408 20.400 345.600 20.424 ;
    END
  END u_rank__qm_d[39]
  PIN u_rank__qm_d[3]
    DIRECTION INPUT ;
    USE SIGNAL ;
    PORT
      LAYER M4 ;
        RECT 345.408 14.400 345.600 14.424 ;
    END
  END u_rank__qm_d[3]
  PIN u_rank__qm_d[400]
    DIRECTION INPUT ;
    USE SIGNAL ;
    PORT
      LAYER M4 ;
        RECT 345.408 80.544 345.600 80.568 ;
    END
  END u_rank__qm_d[400]
  PIN u_rank__qm_d[401]
    DIRECTION INPUT ;
    USE SIGNAL ;
    PORT
      LAYER M4 ;
        RECT 345.408 80.736 345.600 80.760 ;
    END
  END u_rank__qm_d[401]
  PIN u_rank__qm_d[402]
    DIRECTION INPUT ;
    USE SIGNAL ;
    PORT
      LAYER M4 ;
        RECT 345.408 80.880 345.600 80.904 ;
    END
  END u_rank__qm_d[402]
  PIN u_rank__qm_d[403]
    DIRECTION INPUT ;
    USE SIGNAL ;
    PORT
      LAYER M4 ;
        RECT 345.408 81.072 345.600 81.096 ;
    END
  END u_rank__qm_d[403]
  PIN u_rank__qm_d[404]
    DIRECTION INPUT ;
    USE SIGNAL ;
    PORT
      LAYER M4 ;
        RECT 345.408 81.216 345.600 81.240 ;
    END
  END u_rank__qm_d[404]
  PIN u_rank__qm_d[405]
    DIRECTION INPUT ;
    USE SIGNAL ;
    PORT
      LAYER M4 ;
        RECT 345.408 81.408 345.600 81.432 ;
    END
  END u_rank__qm_d[405]
  PIN u_rank__qm_d[406]
    DIRECTION INPUT ;
    USE SIGNAL ;
    PORT
      LAYER M4 ;
        RECT 345.408 81.552 345.600 81.576 ;
    END
  END u_rank__qm_d[406]
  PIN u_rank__qm_d[407]
    DIRECTION INPUT ;
    USE SIGNAL ;
    PORT
      LAYER M4 ;
        RECT 345.408 81.744 345.600 81.768 ;
    END
  END u_rank__qm_d[407]
  PIN u_rank__qm_d[408]
    DIRECTION INPUT ;
    USE SIGNAL ;
    PORT
      LAYER M4 ;
        RECT 345.408 81.888 345.600 81.912 ;
    END
  END u_rank__qm_d[408]
  PIN u_rank__qm_d[409]
    DIRECTION INPUT ;
    USE SIGNAL ;
    PORT
      LAYER M4 ;
        RECT 345.408 82.080 345.600 82.104 ;
    END
  END u_rank__qm_d[409]
  PIN u_rank__qm_d[40]
    DIRECTION INPUT ;
    USE SIGNAL ;
    PORT
      LAYER M4 ;
        RECT 345.408 20.544 345.600 20.568 ;
    END
  END u_rank__qm_d[40]
  PIN u_rank__qm_d[410]
    DIRECTION INPUT ;
    USE SIGNAL ;
    PORT
      LAYER M4 ;
        RECT 345.408 82.224 345.600 82.248 ;
    END
  END u_rank__qm_d[410]
  PIN u_rank__qm_d[411]
    DIRECTION INPUT ;
    USE SIGNAL ;
    PORT
      LAYER M4 ;
        RECT 345.408 82.416 345.600 82.440 ;
    END
  END u_rank__qm_d[411]
  PIN u_rank__qm_d[412]
    DIRECTION INPUT ;
    USE SIGNAL ;
    PORT
      LAYER M4 ;
        RECT 345.408 82.560 345.600 82.584 ;
    END
  END u_rank__qm_d[412]
  PIN u_rank__qm_d[413]
    DIRECTION INPUT ;
    USE SIGNAL ;
    PORT
      LAYER M4 ;
        RECT 345.408 82.752 345.600 82.776 ;
    END
  END u_rank__qm_d[413]
  PIN u_rank__qm_d[414]
    DIRECTION INPUT ;
    USE SIGNAL ;
    PORT
      LAYER M4 ;
        RECT 345.408 82.896 345.600 82.920 ;
    END
  END u_rank__qm_d[414]
  PIN u_rank__qm_d[415]
    DIRECTION INPUT ;
    USE SIGNAL ;
    PORT
      LAYER M4 ;
        RECT 345.408 83.040 345.600 83.064 ;
    END
  END u_rank__qm_d[415]
  PIN u_rank__qm_d[416]
    DIRECTION INPUT ;
    USE SIGNAL ;
    PORT
      LAYER M4 ;
        RECT 345.408 83.232 345.600 83.256 ;
    END
  END u_rank__qm_d[416]
  PIN u_rank__qm_d[417]
    DIRECTION INPUT ;
    USE SIGNAL ;
    PORT
      LAYER M4 ;
        RECT 345.408 83.376 345.600 83.400 ;
    END
  END u_rank__qm_d[417]
  PIN u_rank__qm_d[418]
    DIRECTION INPUT ;
    USE SIGNAL ;
    PORT
      LAYER M4 ;
        RECT 345.408 83.568 345.600 83.592 ;
    END
  END u_rank__qm_d[418]
  PIN u_rank__qm_d[419]
    DIRECTION INPUT ;
    USE SIGNAL ;
    PORT
      LAYER M4 ;
        RECT 345.408 83.712 345.600 83.736 ;
    END
  END u_rank__qm_d[419]
  PIN u_rank__qm_d[41]
    DIRECTION INPUT ;
    USE SIGNAL ;
    PORT
      LAYER M4 ;
        RECT 345.408 20.736 345.600 20.760 ;
    END
  END u_rank__qm_d[41]
  PIN u_rank__qm_d[420]
    DIRECTION INPUT ;
    USE SIGNAL ;
    PORT
      LAYER M4 ;
        RECT 345.408 83.904 345.600 83.928 ;
    END
  END u_rank__qm_d[420]
  PIN u_rank__qm_d[421]
    DIRECTION INPUT ;
    USE SIGNAL ;
    PORT
      LAYER M4 ;
        RECT 345.408 84.048 345.600 84.072 ;
    END
  END u_rank__qm_d[421]
  PIN u_rank__qm_d[422]
    DIRECTION INPUT ;
    USE SIGNAL ;
    PORT
      LAYER M4 ;
        RECT 345.408 84.240 345.600 84.264 ;
    END
  END u_rank__qm_d[422]
  PIN u_rank__qm_d[423]
    DIRECTION INPUT ;
    USE SIGNAL ;
    PORT
      LAYER M4 ;
        RECT 345.408 84.384 345.600 84.408 ;
    END
  END u_rank__qm_d[423]
  PIN u_rank__qm_d[424]
    DIRECTION INPUT ;
    USE SIGNAL ;
    PORT
      LAYER M4 ;
        RECT 345.408 84.576 345.600 84.600 ;
    END
  END u_rank__qm_d[424]
  PIN u_rank__qm_d[425]
    DIRECTION INPUT ;
    USE SIGNAL ;
    PORT
      LAYER M4 ;
        RECT 345.408 84.720 345.600 84.744 ;
    END
  END u_rank__qm_d[425]
  PIN u_rank__qm_d[426]
    DIRECTION INPUT ;
    USE SIGNAL ;
    PORT
      LAYER M4 ;
        RECT 345.408 84.912 345.600 84.936 ;
    END
  END u_rank__qm_d[426]
  PIN u_rank__qm_d[427]
    DIRECTION INPUT ;
    USE SIGNAL ;
    PORT
      LAYER M4 ;
        RECT 345.408 85.056 345.600 85.080 ;
    END
  END u_rank__qm_d[427]
  PIN u_rank__qm_d[428]
    DIRECTION INPUT ;
    USE SIGNAL ;
    PORT
      LAYER M4 ;
        RECT 345.408 85.248 345.600 85.272 ;
    END
  END u_rank__qm_d[428]
  PIN u_rank__qm_d[429]
    DIRECTION INPUT ;
    USE SIGNAL ;
    PORT
      LAYER M4 ;
        RECT 345.408 85.392 345.600 85.416 ;
    END
  END u_rank__qm_d[429]
  PIN u_rank__qm_d[42]
    DIRECTION INPUT ;
    USE SIGNAL ;
    PORT
      LAYER M4 ;
        RECT 345.408 20.880 345.600 20.904 ;
    END
  END u_rank__qm_d[42]
  PIN u_rank__qm_d[430]
    DIRECTION INPUT ;
    USE SIGNAL ;
    PORT
      LAYER M4 ;
        RECT 345.408 85.584 345.600 85.608 ;
    END
  END u_rank__qm_d[430]
  PIN u_rank__qm_d[431]
    DIRECTION INPUT ;
    USE SIGNAL ;
    PORT
      LAYER M4 ;
        RECT 345.408 85.728 345.600 85.752 ;
    END
  END u_rank__qm_d[431]
  PIN u_rank__qm_d[432]
    DIRECTION INPUT ;
    USE SIGNAL ;
    PORT
      LAYER M4 ;
        RECT 345.408 85.872 345.600 85.896 ;
    END
  END u_rank__qm_d[432]
  PIN u_rank__qm_d[433]
    DIRECTION INPUT ;
    USE SIGNAL ;
    PORT
      LAYER M4 ;
        RECT 345.408 86.064 345.600 86.088 ;
    END
  END u_rank__qm_d[433]
  PIN u_rank__qm_d[434]
    DIRECTION INPUT ;
    USE SIGNAL ;
    PORT
      LAYER M4 ;
        RECT 345.408 86.208 345.600 86.232 ;
    END
  END u_rank__qm_d[434]
  PIN u_rank__qm_d[435]
    DIRECTION INPUT ;
    USE SIGNAL ;
    PORT
      LAYER M4 ;
        RECT 345.408 86.400 345.600 86.424 ;
    END
  END u_rank__qm_d[435]
  PIN u_rank__qm_d[436]
    DIRECTION INPUT ;
    USE SIGNAL ;
    PORT
      LAYER M4 ;
        RECT 345.408 86.544 345.600 86.568 ;
    END
  END u_rank__qm_d[436]
  PIN u_rank__qm_d[437]
    DIRECTION INPUT ;
    USE SIGNAL ;
    PORT
      LAYER M4 ;
        RECT 345.408 86.736 345.600 86.760 ;
    END
  END u_rank__qm_d[437]
  PIN u_rank__qm_d[438]
    DIRECTION INPUT ;
    USE SIGNAL ;
    PORT
      LAYER M4 ;
        RECT 345.408 86.880 345.600 86.904 ;
    END
  END u_rank__qm_d[438]
  PIN u_rank__qm_d[439]
    DIRECTION INPUT ;
    USE SIGNAL ;
    PORT
      LAYER M4 ;
        RECT 345.408 87.072 345.600 87.096 ;
    END
  END u_rank__qm_d[439]
  PIN u_rank__qm_d[43]
    DIRECTION INPUT ;
    USE SIGNAL ;
    PORT
      LAYER M4 ;
        RECT 345.408 21.072 345.600 21.096 ;
    END
  END u_rank__qm_d[43]
  PIN u_rank__qm_d[440]
    DIRECTION INPUT ;
    USE SIGNAL ;
    PORT
      LAYER M4 ;
        RECT 345.408 87.216 345.600 87.240 ;
    END
  END u_rank__qm_d[440]
  PIN u_rank__qm_d[441]
    DIRECTION INPUT ;
    USE SIGNAL ;
    PORT
      LAYER M4 ;
        RECT 345.408 87.408 345.600 87.432 ;
    END
  END u_rank__qm_d[441]
  PIN u_rank__qm_d[442]
    DIRECTION INPUT ;
    USE SIGNAL ;
    PORT
      LAYER M4 ;
        RECT 345.408 87.552 345.600 87.576 ;
    END
  END u_rank__qm_d[442]
  PIN u_rank__qm_d[443]
    DIRECTION INPUT ;
    USE SIGNAL ;
    PORT
      LAYER M4 ;
        RECT 345.408 87.744 345.600 87.768 ;
    END
  END u_rank__qm_d[443]
  PIN u_rank__qm_d[444]
    DIRECTION INPUT ;
    USE SIGNAL ;
    PORT
      LAYER M4 ;
        RECT 345.408 87.888 345.600 87.912 ;
    END
  END u_rank__qm_d[444]
  PIN u_rank__qm_d[445]
    DIRECTION INPUT ;
    USE SIGNAL ;
    PORT
      LAYER M4 ;
        RECT 345.408 88.080 345.600 88.104 ;
    END
  END u_rank__qm_d[445]
  PIN u_rank__qm_d[446]
    DIRECTION INPUT ;
    USE SIGNAL ;
    PORT
      LAYER M4 ;
        RECT 345.408 88.224 345.600 88.248 ;
    END
  END u_rank__qm_d[446]
  PIN u_rank__qm_d[447]
    DIRECTION INPUT ;
    USE SIGNAL ;
    PORT
      LAYER M4 ;
        RECT 345.408 88.416 345.600 88.440 ;
    END
  END u_rank__qm_d[447]
  PIN u_rank__qm_d[448]
    DIRECTION INPUT ;
    USE SIGNAL ;
    PORT
      LAYER M4 ;
        RECT 345.408 88.560 345.600 88.584 ;
    END
  END u_rank__qm_d[448]
  PIN u_rank__qm_d[449]
    DIRECTION INPUT ;
    USE SIGNAL ;
    PORT
      LAYER M4 ;
        RECT 345.408 88.752 345.600 88.776 ;
    END
  END u_rank__qm_d[449]
  PIN u_rank__qm_d[44]
    DIRECTION INPUT ;
    USE SIGNAL ;
    PORT
      LAYER M4 ;
        RECT 345.408 21.216 345.600 21.240 ;
    END
  END u_rank__qm_d[44]
  PIN u_rank__qm_d[450]
    DIRECTION INPUT ;
    USE SIGNAL ;
    PORT
      LAYER M4 ;
        RECT 345.408 88.896 345.600 88.920 ;
    END
  END u_rank__qm_d[450]
  PIN u_rank__qm_d[451]
    DIRECTION INPUT ;
    USE SIGNAL ;
    PORT
      LAYER M4 ;
        RECT 345.408 89.040 345.600 89.064 ;
    END
  END u_rank__qm_d[451]
  PIN u_rank__qm_d[452]
    DIRECTION INPUT ;
    USE SIGNAL ;
    PORT
      LAYER M4 ;
        RECT 345.408 89.232 345.600 89.256 ;
    END
  END u_rank__qm_d[452]
  PIN u_rank__qm_d[453]
    DIRECTION INPUT ;
    USE SIGNAL ;
    PORT
      LAYER M4 ;
        RECT 345.408 89.376 345.600 89.400 ;
    END
  END u_rank__qm_d[453]
  PIN u_rank__qm_d[454]
    DIRECTION INPUT ;
    USE SIGNAL ;
    PORT
      LAYER M4 ;
        RECT 345.408 89.568 345.600 89.592 ;
    END
  END u_rank__qm_d[454]
  PIN u_rank__qm_d[455]
    DIRECTION INPUT ;
    USE SIGNAL ;
    PORT
      LAYER M4 ;
        RECT 345.408 89.712 345.600 89.736 ;
    END
  END u_rank__qm_d[455]
  PIN u_rank__qm_d[456]
    DIRECTION INPUT ;
    USE SIGNAL ;
    PORT
      LAYER M4 ;
        RECT 345.408 89.904 345.600 89.928 ;
    END
  END u_rank__qm_d[456]
  PIN u_rank__qm_d[457]
    DIRECTION INPUT ;
    USE SIGNAL ;
    PORT
      LAYER M4 ;
        RECT 345.408 90.048 345.600 90.072 ;
    END
  END u_rank__qm_d[457]
  PIN u_rank__qm_d[458]
    DIRECTION INPUT ;
    USE SIGNAL ;
    PORT
      LAYER M4 ;
        RECT 345.408 90.240 345.600 90.264 ;
    END
  END u_rank__qm_d[458]
  PIN u_rank__qm_d[459]
    DIRECTION INPUT ;
    USE SIGNAL ;
    PORT
      LAYER M4 ;
        RECT 345.408 90.384 345.600 90.408 ;
    END
  END u_rank__qm_d[459]
  PIN u_rank__qm_d[45]
    DIRECTION INPUT ;
    USE SIGNAL ;
    PORT
      LAYER M4 ;
        RECT 345.408 21.408 345.600 21.432 ;
    END
  END u_rank__qm_d[45]
  PIN u_rank__qm_d[460]
    DIRECTION INPUT ;
    USE SIGNAL ;
    PORT
      LAYER M4 ;
        RECT 345.408 90.576 345.600 90.600 ;
    END
  END u_rank__qm_d[460]
  PIN u_rank__qm_d[461]
    DIRECTION INPUT ;
    USE SIGNAL ;
    PORT
      LAYER M4 ;
        RECT 345.408 90.720 345.600 90.744 ;
    END
  END u_rank__qm_d[461]
  PIN u_rank__qm_d[462]
    DIRECTION INPUT ;
    USE SIGNAL ;
    PORT
      LAYER M4 ;
        RECT 345.408 90.912 345.600 90.936 ;
    END
  END u_rank__qm_d[462]
  PIN u_rank__qm_d[463]
    DIRECTION INPUT ;
    USE SIGNAL ;
    PORT
      LAYER M4 ;
        RECT 345.408 91.056 345.600 91.080 ;
    END
  END u_rank__qm_d[463]
  PIN u_rank__qm_d[464]
    DIRECTION INPUT ;
    USE SIGNAL ;
    PORT
      LAYER M4 ;
        RECT 345.408 91.248 345.600 91.272 ;
    END
  END u_rank__qm_d[464]
  PIN u_rank__qm_d[465]
    DIRECTION INPUT ;
    USE SIGNAL ;
    PORT
      LAYER M4 ;
        RECT 345.408 91.392 345.600 91.416 ;
    END
  END u_rank__qm_d[465]
  PIN u_rank__qm_d[466]
    DIRECTION INPUT ;
    USE SIGNAL ;
    PORT
      LAYER M4 ;
        RECT 345.408 91.584 345.600 91.608 ;
    END
  END u_rank__qm_d[466]
  PIN u_rank__qm_d[467]
    DIRECTION INPUT ;
    USE SIGNAL ;
    PORT
      LAYER M4 ;
        RECT 345.408 91.728 345.600 91.752 ;
    END
  END u_rank__qm_d[467]
  PIN u_rank__qm_d[468]
    DIRECTION INPUT ;
    USE SIGNAL ;
    PORT
      LAYER M4 ;
        RECT 345.408 91.872 345.600 91.896 ;
    END
  END u_rank__qm_d[468]
  PIN u_rank__qm_d[469]
    DIRECTION INPUT ;
    USE SIGNAL ;
    PORT
      LAYER M4 ;
        RECT 345.408 92.064 345.600 92.088 ;
    END
  END u_rank__qm_d[469]
  PIN u_rank__qm_d[46]
    DIRECTION INPUT ;
    USE SIGNAL ;
    PORT
      LAYER M4 ;
        RECT 345.408 21.552 345.600 21.576 ;
    END
  END u_rank__qm_d[46]
  PIN u_rank__qm_d[470]
    DIRECTION INPUT ;
    USE SIGNAL ;
    PORT
      LAYER M4 ;
        RECT 345.408 92.208 345.600 92.232 ;
    END
  END u_rank__qm_d[470]
  PIN u_rank__qm_d[471]
    DIRECTION INPUT ;
    USE SIGNAL ;
    PORT
      LAYER M4 ;
        RECT 345.408 92.400 345.600 92.424 ;
    END
  END u_rank__qm_d[471]
  PIN u_rank__qm_d[472]
    DIRECTION INPUT ;
    USE SIGNAL ;
    PORT
      LAYER M4 ;
        RECT 345.408 92.544 345.600 92.568 ;
    END
  END u_rank__qm_d[472]
  PIN u_rank__qm_d[473]
    DIRECTION INPUT ;
    USE SIGNAL ;
    PORT
      LAYER M4 ;
        RECT 345.408 92.736 345.600 92.760 ;
    END
  END u_rank__qm_d[473]
  PIN u_rank__qm_d[474]
    DIRECTION INPUT ;
    USE SIGNAL ;
    PORT
      LAYER M4 ;
        RECT 345.408 92.880 345.600 92.904 ;
    END
  END u_rank__qm_d[474]
  PIN u_rank__qm_d[475]
    DIRECTION INPUT ;
    USE SIGNAL ;
    PORT
      LAYER M4 ;
        RECT 345.408 93.072 345.600 93.096 ;
    END
  END u_rank__qm_d[475]
  PIN u_rank__qm_d[476]
    DIRECTION INPUT ;
    USE SIGNAL ;
    PORT
      LAYER M4 ;
        RECT 345.408 93.216 345.600 93.240 ;
    END
  END u_rank__qm_d[476]
  PIN u_rank__qm_d[477]
    DIRECTION INPUT ;
    USE SIGNAL ;
    PORT
      LAYER M4 ;
        RECT 345.408 93.408 345.600 93.432 ;
    END
  END u_rank__qm_d[477]
  PIN u_rank__qm_d[478]
    DIRECTION INPUT ;
    USE SIGNAL ;
    PORT
      LAYER M4 ;
        RECT 345.408 93.552 345.600 93.576 ;
    END
  END u_rank__qm_d[478]
  PIN u_rank__qm_d[479]
    DIRECTION INPUT ;
    USE SIGNAL ;
    PORT
      LAYER M4 ;
        RECT 345.408 93.744 345.600 93.768 ;
    END
  END u_rank__qm_d[479]
  PIN u_rank__qm_d[47]
    DIRECTION INPUT ;
    USE SIGNAL ;
    PORT
      LAYER M4 ;
        RECT 345.408 21.744 345.600 21.768 ;
    END
  END u_rank__qm_d[47]
  PIN u_rank__qm_d[480]
    DIRECTION INPUT ;
    USE SIGNAL ;
    PORT
      LAYER M4 ;
        RECT 345.408 93.888 345.600 93.912 ;
    END
  END u_rank__qm_d[480]
  PIN u_rank__qm_d[481]
    DIRECTION INPUT ;
    USE SIGNAL ;
    PORT
      LAYER M4 ;
        RECT 345.408 94.080 345.600 94.104 ;
    END
  END u_rank__qm_d[481]
  PIN u_rank__qm_d[482]
    DIRECTION INPUT ;
    USE SIGNAL ;
    PORT
      LAYER M4 ;
        RECT 345.408 94.224 345.600 94.248 ;
    END
  END u_rank__qm_d[482]
  PIN u_rank__qm_d[483]
    DIRECTION INPUT ;
    USE SIGNAL ;
    PORT
      LAYER M4 ;
        RECT 345.408 94.416 345.600 94.440 ;
    END
  END u_rank__qm_d[483]
  PIN u_rank__qm_d[484]
    DIRECTION INPUT ;
    USE SIGNAL ;
    PORT
      LAYER M4 ;
        RECT 345.408 94.560 345.600 94.584 ;
    END
  END u_rank__qm_d[484]
  PIN u_rank__qm_d[485]
    DIRECTION INPUT ;
    USE SIGNAL ;
    PORT
      LAYER M4 ;
        RECT 345.408 94.752 345.600 94.776 ;
    END
  END u_rank__qm_d[485]
  PIN u_rank__qm_d[486]
    DIRECTION INPUT ;
    USE SIGNAL ;
    PORT
      LAYER M4 ;
        RECT 345.408 94.896 345.600 94.920 ;
    END
  END u_rank__qm_d[486]
  PIN u_rank__qm_d[487]
    DIRECTION INPUT ;
    USE SIGNAL ;
    PORT
      LAYER M4 ;
        RECT 345.408 95.040 345.600 95.064 ;
    END
  END u_rank__qm_d[487]
  PIN u_rank__qm_d[488]
    DIRECTION INPUT ;
    USE SIGNAL ;
    PORT
      LAYER M4 ;
        RECT 345.408 95.232 345.600 95.256 ;
    END
  END u_rank__qm_d[488]
  PIN u_rank__qm_d[489]
    DIRECTION INPUT ;
    USE SIGNAL ;
    PORT
      LAYER M4 ;
        RECT 345.408 95.376 345.600 95.400 ;
    END
  END u_rank__qm_d[489]
  PIN u_rank__qm_d[48]
    DIRECTION INPUT ;
    USE SIGNAL ;
    PORT
      LAYER M4 ;
        RECT 345.408 21.888 345.600 21.912 ;
    END
  END u_rank__qm_d[48]
  PIN u_rank__qm_d[490]
    DIRECTION INPUT ;
    USE SIGNAL ;
    PORT
      LAYER M4 ;
        RECT 345.408 95.568 345.600 95.592 ;
    END
  END u_rank__qm_d[490]
  PIN u_rank__qm_d[491]
    DIRECTION INPUT ;
    USE SIGNAL ;
    PORT
      LAYER M4 ;
        RECT 345.408 95.712 345.600 95.736 ;
    END
  END u_rank__qm_d[491]
  PIN u_rank__qm_d[492]
    DIRECTION INPUT ;
    USE SIGNAL ;
    PORT
      LAYER M4 ;
        RECT 345.408 95.904 345.600 95.928 ;
    END
  END u_rank__qm_d[492]
  PIN u_rank__qm_d[493]
    DIRECTION INPUT ;
    USE SIGNAL ;
    PORT
      LAYER M4 ;
        RECT 345.408 96.048 345.600 96.072 ;
    END
  END u_rank__qm_d[493]
  PIN u_rank__qm_d[494]
    DIRECTION INPUT ;
    USE SIGNAL ;
    PORT
      LAYER M4 ;
        RECT 345.408 96.240 345.600 96.264 ;
    END
  END u_rank__qm_d[494]
  PIN u_rank__qm_d[495]
    DIRECTION INPUT ;
    USE SIGNAL ;
    PORT
      LAYER M4 ;
        RECT 345.408 96.384 345.600 96.408 ;
    END
  END u_rank__qm_d[495]
  PIN u_rank__qm_d[496]
    DIRECTION INPUT ;
    USE SIGNAL ;
    PORT
      LAYER M4 ;
        RECT 345.408 96.576 345.600 96.600 ;
    END
  END u_rank__qm_d[496]
  PIN u_rank__qm_d[497]
    DIRECTION INPUT ;
    USE SIGNAL ;
    PORT
      LAYER M4 ;
        RECT 345.408 96.720 345.600 96.744 ;
    END
  END u_rank__qm_d[497]
  PIN u_rank__qm_d[498]
    DIRECTION INPUT ;
    USE SIGNAL ;
    PORT
      LAYER M4 ;
        RECT 345.408 96.912 345.600 96.936 ;
    END
  END u_rank__qm_d[498]
  PIN u_rank__qm_d[499]
    DIRECTION INPUT ;
    USE SIGNAL ;
    PORT
      LAYER M4 ;
        RECT 345.408 97.056 345.600 97.080 ;
    END
  END u_rank__qm_d[499]
  PIN u_rank__qm_d[49]
    DIRECTION INPUT ;
    USE SIGNAL ;
    PORT
      LAYER M4 ;
        RECT 345.408 22.080 345.600 22.104 ;
    END
  END u_rank__qm_d[49]
  PIN u_rank__qm_d[4]
    DIRECTION INPUT ;
    USE SIGNAL ;
    PORT
      LAYER M4 ;
        RECT 345.408 14.544 345.600 14.568 ;
    END
  END u_rank__qm_d[4]
  PIN u_rank__qm_d[500]
    DIRECTION INPUT ;
    USE SIGNAL ;
    PORT
      LAYER M4 ;
        RECT 345.408 97.248 345.600 97.272 ;
    END
  END u_rank__qm_d[500]
  PIN u_rank__qm_d[501]
    DIRECTION INPUT ;
    USE SIGNAL ;
    PORT
      LAYER M4 ;
        RECT 345.408 97.392 345.600 97.416 ;
    END
  END u_rank__qm_d[501]
  PIN u_rank__qm_d[502]
    DIRECTION INPUT ;
    USE SIGNAL ;
    PORT
      LAYER M4 ;
        RECT 345.408 97.584 345.600 97.608 ;
    END
  END u_rank__qm_d[502]
  PIN u_rank__qm_d[503]
    DIRECTION INPUT ;
    USE SIGNAL ;
    PORT
      LAYER M4 ;
        RECT 345.408 97.728 345.600 97.752 ;
    END
  END u_rank__qm_d[503]
  PIN u_rank__qm_d[504]
    DIRECTION INPUT ;
    USE SIGNAL ;
    PORT
      LAYER M4 ;
        RECT 345.408 97.872 345.600 97.896 ;
    END
  END u_rank__qm_d[504]
  PIN u_rank__qm_d[505]
    DIRECTION INPUT ;
    USE SIGNAL ;
    PORT
      LAYER M4 ;
        RECT 345.408 98.064 345.600 98.088 ;
    END
  END u_rank__qm_d[505]
  PIN u_rank__qm_d[506]
    DIRECTION INPUT ;
    USE SIGNAL ;
    PORT
      LAYER M4 ;
        RECT 345.408 98.208 345.600 98.232 ;
    END
  END u_rank__qm_d[506]
  PIN u_rank__qm_d[507]
    DIRECTION INPUT ;
    USE SIGNAL ;
    PORT
      LAYER M4 ;
        RECT 345.408 98.400 345.600 98.424 ;
    END
  END u_rank__qm_d[507]
  PIN u_rank__qm_d[508]
    DIRECTION INPUT ;
    USE SIGNAL ;
    PORT
      LAYER M4 ;
        RECT 345.408 98.544 345.600 98.568 ;
    END
  END u_rank__qm_d[508]
  PIN u_rank__qm_d[509]
    DIRECTION INPUT ;
    USE SIGNAL ;
    PORT
      LAYER M4 ;
        RECT 345.408 98.736 345.600 98.760 ;
    END
  END u_rank__qm_d[509]
  PIN u_rank__qm_d[50]
    DIRECTION INPUT ;
    USE SIGNAL ;
    PORT
      LAYER M4 ;
        RECT 345.408 22.224 345.600 22.248 ;
    END
  END u_rank__qm_d[50]
  PIN u_rank__qm_d[510]
    DIRECTION INPUT ;
    USE SIGNAL ;
    PORT
      LAYER M4 ;
        RECT 345.408 98.880 345.600 98.904 ;
    END
  END u_rank__qm_d[510]
  PIN u_rank__qm_d[511]
    DIRECTION INPUT ;
    USE SIGNAL ;
    PORT
      LAYER M4 ;
        RECT 345.408 99.072 345.600 99.096 ;
    END
  END u_rank__qm_d[511]
  PIN u_rank__qm_d[51]
    DIRECTION INPUT ;
    USE SIGNAL ;
    PORT
      LAYER M4 ;
        RECT 345.408 22.416 345.600 22.440 ;
    END
  END u_rank__qm_d[51]
  PIN u_rank__qm_d[52]
    DIRECTION INPUT ;
    USE SIGNAL ;
    PORT
      LAYER M4 ;
        RECT 345.408 22.560 345.600 22.584 ;
    END
  END u_rank__qm_d[52]
  PIN u_rank__qm_d[53]
    DIRECTION INPUT ;
    USE SIGNAL ;
    PORT
      LAYER M4 ;
        RECT 345.408 22.752 345.600 22.776 ;
    END
  END u_rank__qm_d[53]
  PIN u_rank__qm_d[54]
    DIRECTION INPUT ;
    USE SIGNAL ;
    PORT
      LAYER M4 ;
        RECT 345.408 22.896 345.600 22.920 ;
    END
  END u_rank__qm_d[54]
  PIN u_rank__qm_d[55]
    DIRECTION INPUT ;
    USE SIGNAL ;
    PORT
      LAYER M4 ;
        RECT 345.408 23.040 345.600 23.064 ;
    END
  END u_rank__qm_d[55]
  PIN u_rank__qm_d[56]
    DIRECTION INPUT ;
    USE SIGNAL ;
    PORT
      LAYER M4 ;
        RECT 345.408 23.232 345.600 23.256 ;
    END
  END u_rank__qm_d[56]
  PIN u_rank__qm_d[57]
    DIRECTION INPUT ;
    USE SIGNAL ;
    PORT
      LAYER M4 ;
        RECT 345.408 23.376 345.600 23.400 ;
    END
  END u_rank__qm_d[57]
  PIN u_rank__qm_d[58]
    DIRECTION INPUT ;
    USE SIGNAL ;
    PORT
      LAYER M4 ;
        RECT 345.408 23.568 345.600 23.592 ;
    END
  END u_rank__qm_d[58]
  PIN u_rank__qm_d[59]
    DIRECTION INPUT ;
    USE SIGNAL ;
    PORT
      LAYER M4 ;
        RECT 345.408 23.712 345.600 23.736 ;
    END
  END u_rank__qm_d[59]
  PIN u_rank__qm_d[5]
    DIRECTION INPUT ;
    USE SIGNAL ;
    PORT
      LAYER M4 ;
        RECT 345.408 14.736 345.600 14.760 ;
    END
  END u_rank__qm_d[5]
  PIN u_rank__qm_d[60]
    DIRECTION INPUT ;
    USE SIGNAL ;
    PORT
      LAYER M4 ;
        RECT 345.408 23.904 345.600 23.928 ;
    END
  END u_rank__qm_d[60]
  PIN u_rank__qm_d[61]
    DIRECTION INPUT ;
    USE SIGNAL ;
    PORT
      LAYER M4 ;
        RECT 345.408 24.048 345.600 24.072 ;
    END
  END u_rank__qm_d[61]
  PIN u_rank__qm_d[62]
    DIRECTION INPUT ;
    USE SIGNAL ;
    PORT
      LAYER M4 ;
        RECT 345.408 24.240 345.600 24.264 ;
    END
  END u_rank__qm_d[62]
  PIN u_rank__qm_d[63]
    DIRECTION INPUT ;
    USE SIGNAL ;
    PORT
      LAYER M4 ;
        RECT 345.408 24.384 345.600 24.408 ;
    END
  END u_rank__qm_d[63]
  PIN u_rank__qm_d[64]
    DIRECTION INPUT ;
    USE SIGNAL ;
    PORT
      LAYER M4 ;
        RECT 345.408 24.576 345.600 24.600 ;
    END
  END u_rank__qm_d[64]
  PIN u_rank__qm_d[65]
    DIRECTION INPUT ;
    USE SIGNAL ;
    PORT
      LAYER M4 ;
        RECT 345.408 24.720 345.600 24.744 ;
    END
  END u_rank__qm_d[65]
  PIN u_rank__qm_d[66]
    DIRECTION INPUT ;
    USE SIGNAL ;
    PORT
      LAYER M4 ;
        RECT 345.408 24.912 345.600 24.936 ;
    END
  END u_rank__qm_d[66]
  PIN u_rank__qm_d[67]
    DIRECTION INPUT ;
    USE SIGNAL ;
    PORT
      LAYER M4 ;
        RECT 345.408 25.056 345.600 25.080 ;
    END
  END u_rank__qm_d[67]
  PIN u_rank__qm_d[68]
    DIRECTION INPUT ;
    USE SIGNAL ;
    PORT
      LAYER M4 ;
        RECT 345.408 25.248 345.600 25.272 ;
    END
  END u_rank__qm_d[68]
  PIN u_rank__qm_d[69]
    DIRECTION INPUT ;
    USE SIGNAL ;
    PORT
      LAYER M4 ;
        RECT 345.408 25.392 345.600 25.416 ;
    END
  END u_rank__qm_d[69]
  PIN u_rank__qm_d[6]
    DIRECTION INPUT ;
    USE SIGNAL ;
    PORT
      LAYER M4 ;
        RECT 345.408 14.880 345.600 14.904 ;
    END
  END u_rank__qm_d[6]
  PIN u_rank__qm_d[70]
    DIRECTION INPUT ;
    USE SIGNAL ;
    PORT
      LAYER M4 ;
        RECT 345.408 25.584 345.600 25.608 ;
    END
  END u_rank__qm_d[70]
  PIN u_rank__qm_d[71]
    DIRECTION INPUT ;
    USE SIGNAL ;
    PORT
      LAYER M4 ;
        RECT 345.408 25.728 345.600 25.752 ;
    END
  END u_rank__qm_d[71]
  PIN u_rank__qm_d[72]
    DIRECTION INPUT ;
    USE SIGNAL ;
    PORT
      LAYER M4 ;
        RECT 345.408 25.872 345.600 25.896 ;
    END
  END u_rank__qm_d[72]
  PIN u_rank__qm_d[73]
    DIRECTION INPUT ;
    USE SIGNAL ;
    PORT
      LAYER M4 ;
        RECT 345.408 26.064 345.600 26.088 ;
    END
  END u_rank__qm_d[73]
  PIN u_rank__qm_d[74]
    DIRECTION INPUT ;
    USE SIGNAL ;
    PORT
      LAYER M4 ;
        RECT 345.408 26.208 345.600 26.232 ;
    END
  END u_rank__qm_d[74]
  PIN u_rank__qm_d[75]
    DIRECTION INPUT ;
    USE SIGNAL ;
    PORT
      LAYER M4 ;
        RECT 345.408 26.400 345.600 26.424 ;
    END
  END u_rank__qm_d[75]
  PIN u_rank__qm_d[76]
    DIRECTION INPUT ;
    USE SIGNAL ;
    PORT
      LAYER M4 ;
        RECT 345.408 26.544 345.600 26.568 ;
    END
  END u_rank__qm_d[76]
  PIN u_rank__qm_d[77]
    DIRECTION INPUT ;
    USE SIGNAL ;
    PORT
      LAYER M4 ;
        RECT 345.408 26.736 345.600 26.760 ;
    END
  END u_rank__qm_d[77]
  PIN u_rank__qm_d[78]
    DIRECTION INPUT ;
    USE SIGNAL ;
    PORT
      LAYER M4 ;
        RECT 345.408 26.880 345.600 26.904 ;
    END
  END u_rank__qm_d[78]
  PIN u_rank__qm_d[79]
    DIRECTION INPUT ;
    USE SIGNAL ;
    PORT
      LAYER M4 ;
        RECT 345.408 27.072 345.600 27.096 ;
    END
  END u_rank__qm_d[79]
  PIN u_rank__qm_d[7]
    DIRECTION INPUT ;
    USE SIGNAL ;
    PORT
      LAYER M4 ;
        RECT 345.408 15.072 345.600 15.096 ;
    END
  END u_rank__qm_d[7]
  PIN u_rank__qm_d[80]
    DIRECTION INPUT ;
    USE SIGNAL ;
    PORT
      LAYER M4 ;
        RECT 345.408 27.216 345.600 27.240 ;
    END
  END u_rank__qm_d[80]
  PIN u_rank__qm_d[81]
    DIRECTION INPUT ;
    USE SIGNAL ;
    PORT
      LAYER M4 ;
        RECT 345.408 27.408 345.600 27.432 ;
    END
  END u_rank__qm_d[81]
  PIN u_rank__qm_d[82]
    DIRECTION INPUT ;
    USE SIGNAL ;
    PORT
      LAYER M4 ;
        RECT 345.408 27.552 345.600 27.576 ;
    END
  END u_rank__qm_d[82]
  PIN u_rank__qm_d[83]
    DIRECTION INPUT ;
    USE SIGNAL ;
    PORT
      LAYER M4 ;
        RECT 345.408 27.744 345.600 27.768 ;
    END
  END u_rank__qm_d[83]
  PIN u_rank__qm_d[84]
    DIRECTION INPUT ;
    USE SIGNAL ;
    PORT
      LAYER M4 ;
        RECT 345.408 27.888 345.600 27.912 ;
    END
  END u_rank__qm_d[84]
  PIN u_rank__qm_d[85]
    DIRECTION INPUT ;
    USE SIGNAL ;
    PORT
      LAYER M4 ;
        RECT 345.408 28.080 345.600 28.104 ;
    END
  END u_rank__qm_d[85]
  PIN u_rank__qm_d[86]
    DIRECTION INPUT ;
    USE SIGNAL ;
    PORT
      LAYER M4 ;
        RECT 345.408 28.224 345.600 28.248 ;
    END
  END u_rank__qm_d[86]
  PIN u_rank__qm_d[87]
    DIRECTION INPUT ;
    USE SIGNAL ;
    PORT
      LAYER M4 ;
        RECT 345.408 28.416 345.600 28.440 ;
    END
  END u_rank__qm_d[87]
  PIN u_rank__qm_d[88]
    DIRECTION INPUT ;
    USE SIGNAL ;
    PORT
      LAYER M4 ;
        RECT 345.408 28.560 345.600 28.584 ;
    END
  END u_rank__qm_d[88]
  PIN u_rank__qm_d[89]
    DIRECTION INPUT ;
    USE SIGNAL ;
    PORT
      LAYER M4 ;
        RECT 345.408 28.752 345.600 28.776 ;
    END
  END u_rank__qm_d[89]
  PIN u_rank__qm_d[8]
    DIRECTION INPUT ;
    USE SIGNAL ;
    PORT
      LAYER M4 ;
        RECT 345.408 15.216 345.600 15.240 ;
    END
  END u_rank__qm_d[8]
  PIN u_rank__qm_d[90]
    DIRECTION INPUT ;
    USE SIGNAL ;
    PORT
      LAYER M4 ;
        RECT 345.408 28.896 345.600 28.920 ;
    END
  END u_rank__qm_d[90]
  PIN u_rank__qm_d[91]
    DIRECTION INPUT ;
    USE SIGNAL ;
    PORT
      LAYER M4 ;
        RECT 345.408 29.040 345.600 29.064 ;
    END
  END u_rank__qm_d[91]
  PIN u_rank__qm_d[92]
    DIRECTION INPUT ;
    USE SIGNAL ;
    PORT
      LAYER M4 ;
        RECT 345.408 29.232 345.600 29.256 ;
    END
  END u_rank__qm_d[92]
  PIN u_rank__qm_d[93]
    DIRECTION INPUT ;
    USE SIGNAL ;
    PORT
      LAYER M4 ;
        RECT 345.408 29.376 345.600 29.400 ;
    END
  END u_rank__qm_d[93]
  PIN u_rank__qm_d[94]
    DIRECTION INPUT ;
    USE SIGNAL ;
    PORT
      LAYER M4 ;
        RECT 345.408 29.568 345.600 29.592 ;
    END
  END u_rank__qm_d[94]
  PIN u_rank__qm_d[95]
    DIRECTION INPUT ;
    USE SIGNAL ;
    PORT
      LAYER M4 ;
        RECT 345.408 29.712 345.600 29.736 ;
    END
  END u_rank__qm_d[95]
  PIN u_rank__qm_d[96]
    DIRECTION INPUT ;
    USE SIGNAL ;
    PORT
      LAYER M4 ;
        RECT 345.408 29.904 345.600 29.928 ;
    END
  END u_rank__qm_d[96]
  PIN u_rank__qm_d[97]
    DIRECTION INPUT ;
    USE SIGNAL ;
    PORT
      LAYER M4 ;
        RECT 345.408 30.048 345.600 30.072 ;
    END
  END u_rank__qm_d[97]
  PIN u_rank__qm_d[98]
    DIRECTION INPUT ;
    USE SIGNAL ;
    PORT
      LAYER M4 ;
        RECT 345.408 30.240 345.600 30.264 ;
    END
  END u_rank__qm_d[98]
  PIN u_rank__qm_d[99]
    DIRECTION INPUT ;
    USE SIGNAL ;
    PORT
      LAYER M4 ;
        RECT 345.408 30.384 345.600 30.408 ;
    END
  END u_rank__qm_d[99]
  PIN u_rank__qm_d[9]
    DIRECTION INPUT ;
    USE SIGNAL ;
    PORT
      LAYER M4 ;
        RECT 345.408 15.408 345.600 15.432 ;
    END
  END u_rank__qm_d[9]
  PIN u_rank__qm_t_cr
    DIRECTION INPUT ;
    USE SIGNAL ;
    PORT
      LAYER M4 ;
        RECT 345.408 99.216 345.600 99.240 ;
    END
  END u_rank__qm_t_cr
  PIN u_rank__qm_t_d[0]
    DIRECTION OUTPUT ;
    USE SIGNAL ;
    PORT
      LAYER M4 ;
        RECT 345.408 99.408 345.600 99.432 ;
    END
  END u_rank__qm_t_d[0]
  PIN u_rank__qm_t_d[10]
    DIRECTION OUTPUT ;
    USE SIGNAL ;
    PORT
      LAYER M4 ;
        RECT 345.408 101.040 345.600 101.064 ;
    END
  END u_rank__qm_t_d[10]
  PIN u_rank__qm_t_d[11]
    DIRECTION OUTPUT ;
    USE SIGNAL ;
    PORT
      LAYER M4 ;
        RECT 345.408 101.232 345.600 101.256 ;
    END
  END u_rank__qm_t_d[11]
  PIN u_rank__qm_t_d[12]
    DIRECTION OUTPUT ;
    USE SIGNAL ;
    PORT
      LAYER M4 ;
        RECT 345.408 101.376 345.600 101.400 ;
    END
  END u_rank__qm_t_d[12]
  PIN u_rank__qm_t_d[13]
    DIRECTION OUTPUT ;
    USE SIGNAL ;
    PORT
      LAYER M4 ;
        RECT 345.408 101.568 345.600 101.592 ;
    END
  END u_rank__qm_t_d[13]
  PIN u_rank__qm_t_d[14]
    DIRECTION OUTPUT ;
    USE SIGNAL ;
    PORT
      LAYER M4 ;
        RECT 345.408 101.712 345.600 101.736 ;
    END
  END u_rank__qm_t_d[14]
  PIN u_rank__qm_t_d[15]
    DIRECTION OUTPUT ;
    USE SIGNAL ;
    PORT
      LAYER M4 ;
        RECT 345.408 101.904 345.600 101.928 ;
    END
  END u_rank__qm_t_d[15]
  PIN u_rank__qm_t_d[16]
    DIRECTION OUTPUT ;
    USE SIGNAL ;
    PORT
      LAYER M4 ;
        RECT 345.408 102.048 345.600 102.072 ;
    END
  END u_rank__qm_t_d[16]
  PIN u_rank__qm_t_d[17]
    DIRECTION OUTPUT ;
    USE SIGNAL ;
    PORT
      LAYER M4 ;
        RECT 345.408 102.240 345.600 102.264 ;
    END
  END u_rank__qm_t_d[17]
  PIN u_rank__qm_t_d[18]
    DIRECTION OUTPUT ;
    USE SIGNAL ;
    PORT
      LAYER M4 ;
        RECT 345.408 102.384 345.600 102.408 ;
    END
  END u_rank__qm_t_d[18]
  PIN u_rank__qm_t_d[19]
    DIRECTION OUTPUT ;
    USE SIGNAL ;
    PORT
      LAYER M4 ;
        RECT 345.408 102.576 345.600 102.600 ;
    END
  END u_rank__qm_t_d[19]
  PIN u_rank__qm_t_d[1]
    DIRECTION OUTPUT ;
    USE SIGNAL ;
    PORT
      LAYER M4 ;
        RECT 345.408 99.552 345.600 99.576 ;
    END
  END u_rank__qm_t_d[1]
  PIN u_rank__qm_t_d[20]
    DIRECTION OUTPUT ;
    USE SIGNAL ;
    PORT
      LAYER M4 ;
        RECT 345.408 102.720 345.600 102.744 ;
    END
  END u_rank__qm_t_d[20]
  PIN u_rank__qm_t_d[21]
    DIRECTION OUTPUT ;
    USE SIGNAL ;
    PORT
      LAYER M4 ;
        RECT 345.408 102.912 345.600 102.936 ;
    END
  END u_rank__qm_t_d[21]
  PIN u_rank__qm_t_d[22]
    DIRECTION OUTPUT ;
    USE SIGNAL ;
    PORT
      LAYER M4 ;
        RECT 345.408 103.056 345.600 103.080 ;
    END
  END u_rank__qm_t_d[22]
  PIN u_rank__qm_t_d[23]
    DIRECTION OUTPUT ;
    USE SIGNAL ;
    PORT
      LAYER M4 ;
        RECT 345.408 103.248 345.600 103.272 ;
    END
  END u_rank__qm_t_d[23]
  PIN u_rank__qm_t_d[24]
    DIRECTION OUTPUT ;
    USE SIGNAL ;
    PORT
      LAYER M4 ;
        RECT 345.408 103.392 345.600 103.416 ;
    END
  END u_rank__qm_t_d[24]
  PIN u_rank__qm_t_d[25]
    DIRECTION OUTPUT ;
    USE SIGNAL ;
    PORT
      LAYER M4 ;
        RECT 345.408 103.584 345.600 103.608 ;
    END
  END u_rank__qm_t_d[25]
  PIN u_rank__qm_t_d[26]
    DIRECTION OUTPUT ;
    USE SIGNAL ;
    PORT
      LAYER M4 ;
        RECT 345.408 103.728 345.600 103.752 ;
    END
  END u_rank__qm_t_d[26]
  PIN u_rank__qm_t_d[27]
    DIRECTION OUTPUT ;
    USE SIGNAL ;
    PORT
      LAYER M4 ;
        RECT 345.408 103.872 345.600 103.896 ;
    END
  END u_rank__qm_t_d[27]
  PIN u_rank__qm_t_d[28]
    DIRECTION OUTPUT ;
    USE SIGNAL ;
    PORT
      LAYER M4 ;
        RECT 345.408 104.064 345.600 104.088 ;
    END
  END u_rank__qm_t_d[28]
  PIN u_rank__qm_t_d[29]
    DIRECTION OUTPUT ;
    USE SIGNAL ;
    PORT
      LAYER M4 ;
        RECT 345.408 104.208 345.600 104.232 ;
    END
  END u_rank__qm_t_d[29]
  PIN u_rank__qm_t_d[2]
    DIRECTION OUTPUT ;
    USE SIGNAL ;
    PORT
      LAYER M4 ;
        RECT 345.408 99.744 345.600 99.768 ;
    END
  END u_rank__qm_t_d[2]
  PIN u_rank__qm_t_d[30]
    DIRECTION OUTPUT ;
    USE SIGNAL ;
    PORT
      LAYER M4 ;
        RECT 345.408 104.400 345.600 104.424 ;
    END
  END u_rank__qm_t_d[30]
  PIN u_rank__qm_t_d[31]
    DIRECTION OUTPUT ;
    USE SIGNAL ;
    PORT
      LAYER M4 ;
        RECT 345.408 104.544 345.600 104.568 ;
    END
  END u_rank__qm_t_d[31]
  PIN u_rank__qm_t_d[32]
    DIRECTION OUTPUT ;
    USE SIGNAL ;
    PORT
      LAYER M4 ;
        RECT 345.408 104.736 345.600 104.760 ;
    END
  END u_rank__qm_t_d[32]
  PIN u_rank__qm_t_d[33]
    DIRECTION OUTPUT ;
    USE SIGNAL ;
    PORT
      LAYER M4 ;
        RECT 345.408 104.880 345.600 104.904 ;
    END
  END u_rank__qm_t_d[33]
  PIN u_rank__qm_t_d[34]
    DIRECTION OUTPUT ;
    USE SIGNAL ;
    PORT
      LAYER M4 ;
        RECT 345.408 105.072 345.600 105.096 ;
    END
  END u_rank__qm_t_d[34]
  PIN u_rank__qm_t_d[35]
    DIRECTION OUTPUT ;
    USE SIGNAL ;
    PORT
      LAYER M4 ;
        RECT 345.408 105.216 345.600 105.240 ;
    END
  END u_rank__qm_t_d[35]
  PIN u_rank__qm_t_d[36]
    DIRECTION OUTPUT ;
    USE SIGNAL ;
    PORT
      LAYER M4 ;
        RECT 345.408 105.408 345.600 105.432 ;
    END
  END u_rank__qm_t_d[36]
  PIN u_rank__qm_t_d[37]
    DIRECTION OUTPUT ;
    USE SIGNAL ;
    PORT
      LAYER M4 ;
        RECT 345.408 105.552 345.600 105.576 ;
    END
  END u_rank__qm_t_d[37]
  PIN u_rank__qm_t_d[38]
    DIRECTION OUTPUT ;
    USE SIGNAL ;
    PORT
      LAYER M4 ;
        RECT 345.408 105.744 345.600 105.768 ;
    END
  END u_rank__qm_t_d[38]
  PIN u_rank__qm_t_d[39]
    DIRECTION OUTPUT ;
    USE SIGNAL ;
    PORT
      LAYER M4 ;
        RECT 345.408 105.888 345.600 105.912 ;
    END
  END u_rank__qm_t_d[39]
  PIN u_rank__qm_t_d[3]
    DIRECTION OUTPUT ;
    USE SIGNAL ;
    PORT
      LAYER M4 ;
        RECT 345.408 99.888 345.600 99.912 ;
    END
  END u_rank__qm_t_d[3]
  PIN u_rank__qm_t_d[40]
    DIRECTION OUTPUT ;
    USE SIGNAL ;
    PORT
      LAYER M4 ;
        RECT 345.408 106.080 345.600 106.104 ;
    END
  END u_rank__qm_t_d[40]
  PIN u_rank__qm_t_d[41]
    DIRECTION OUTPUT ;
    USE SIGNAL ;
    PORT
      LAYER M4 ;
        RECT 345.408 106.224 345.600 106.248 ;
    END
  END u_rank__qm_t_d[41]
  PIN u_rank__qm_t_d[42]
    DIRECTION OUTPUT ;
    USE SIGNAL ;
    PORT
      LAYER M4 ;
        RECT 345.408 106.416 345.600 106.440 ;
    END
  END u_rank__qm_t_d[42]
  PIN u_rank__qm_t_d[43]
    DIRECTION OUTPUT ;
    USE SIGNAL ;
    PORT
      LAYER M4 ;
        RECT 345.408 106.560 345.600 106.584 ;
    END
  END u_rank__qm_t_d[43]
  PIN u_rank__qm_t_d[44]
    DIRECTION OUTPUT ;
    USE SIGNAL ;
    PORT
      LAYER M4 ;
        RECT 345.408 106.752 345.600 106.776 ;
    END
  END u_rank__qm_t_d[44]
  PIN u_rank__qm_t_d[45]
    DIRECTION OUTPUT ;
    USE SIGNAL ;
    PORT
      LAYER M4 ;
        RECT 345.408 106.896 345.600 106.920 ;
    END
  END u_rank__qm_t_d[45]
  PIN u_rank__qm_t_d[46]
    DIRECTION OUTPUT ;
    USE SIGNAL ;
    PORT
      LAYER M4 ;
        RECT 345.408 107.040 345.600 107.064 ;
    END
  END u_rank__qm_t_d[46]
  PIN u_rank__qm_t_d[47]
    DIRECTION OUTPUT ;
    USE SIGNAL ;
    PORT
      LAYER M4 ;
        RECT 345.408 107.232 345.600 107.256 ;
    END
  END u_rank__qm_t_d[47]
  PIN u_rank__qm_t_d[48]
    DIRECTION OUTPUT ;
    USE SIGNAL ;
    PORT
      LAYER M4 ;
        RECT 345.408 107.376 345.600 107.400 ;
    END
  END u_rank__qm_t_d[48]
  PIN u_rank__qm_t_d[49]
    DIRECTION OUTPUT ;
    USE SIGNAL ;
    PORT
      LAYER M4 ;
        RECT 345.408 107.568 345.600 107.592 ;
    END
  END u_rank__qm_t_d[49]
  PIN u_rank__qm_t_d[4]
    DIRECTION OUTPUT ;
    USE SIGNAL ;
    PORT
      LAYER M4 ;
        RECT 345.408 100.080 345.600 100.104 ;
    END
  END u_rank__qm_t_d[4]
  PIN u_rank__qm_t_d[50]
    DIRECTION OUTPUT ;
    USE SIGNAL ;
    PORT
      LAYER M4 ;
        RECT 345.408 107.712 345.600 107.736 ;
    END
  END u_rank__qm_t_d[50]
  PIN u_rank__qm_t_d[51]
    DIRECTION OUTPUT ;
    USE SIGNAL ;
    PORT
      LAYER M4 ;
        RECT 345.408 107.904 345.600 107.928 ;
    END
  END u_rank__qm_t_d[51]
  PIN u_rank__qm_t_d[52]
    DIRECTION OUTPUT ;
    USE SIGNAL ;
    PORT
      LAYER M4 ;
        RECT 345.408 108.048 345.600 108.072 ;
    END
  END u_rank__qm_t_d[52]
  PIN u_rank__qm_t_d[53]
    DIRECTION OUTPUT ;
    USE SIGNAL ;
    PORT
      LAYER M4 ;
        RECT 345.408 108.240 345.600 108.264 ;
    END
  END u_rank__qm_t_d[53]
  PIN u_rank__qm_t_d[54]
    DIRECTION OUTPUT ;
    USE SIGNAL ;
    PORT
      LAYER M4 ;
        RECT 345.408 108.384 345.600 108.408 ;
    END
  END u_rank__qm_t_d[54]
  PIN u_rank__qm_t_d[55]
    DIRECTION OUTPUT ;
    USE SIGNAL ;
    PORT
      LAYER M4 ;
        RECT 345.408 108.576 345.600 108.600 ;
    END
  END u_rank__qm_t_d[55]
  PIN u_rank__qm_t_d[56]
    DIRECTION OUTPUT ;
    USE SIGNAL ;
    PORT
      LAYER M4 ;
        RECT 345.408 108.720 345.600 108.744 ;
    END
  END u_rank__qm_t_d[56]
  PIN u_rank__qm_t_d[57]
    DIRECTION OUTPUT ;
    USE SIGNAL ;
    PORT
      LAYER M4 ;
        RECT 345.408 108.912 345.600 108.936 ;
    END
  END u_rank__qm_t_d[57]
  PIN u_rank__qm_t_d[58]
    DIRECTION OUTPUT ;
    USE SIGNAL ;
    PORT
      LAYER M4 ;
        RECT 345.408 109.056 345.600 109.080 ;
    END
  END u_rank__qm_t_d[58]
  PIN u_rank__qm_t_d[59]
    DIRECTION OUTPUT ;
    USE SIGNAL ;
    PORT
      LAYER M4 ;
        RECT 345.408 109.248 345.600 109.272 ;
    END
  END u_rank__qm_t_d[59]
  PIN u_rank__qm_t_d[5]
    DIRECTION OUTPUT ;
    USE SIGNAL ;
    PORT
      LAYER M4 ;
        RECT 345.408 100.224 345.600 100.248 ;
    END
  END u_rank__qm_t_d[5]
  PIN u_rank__qm_t_d[60]
    DIRECTION OUTPUT ;
    USE SIGNAL ;
    PORT
      LAYER M4 ;
        RECT 345.408 109.392 345.600 109.416 ;
    END
  END u_rank__qm_t_d[60]
  PIN u_rank__qm_t_d[61]
    DIRECTION OUTPUT ;
    USE SIGNAL ;
    PORT
      LAYER M4 ;
        RECT 345.408 109.584 345.600 109.608 ;
    END
  END u_rank__qm_t_d[61]
  PIN u_rank__qm_t_d[62]
    DIRECTION OUTPUT ;
    USE SIGNAL ;
    PORT
      LAYER M4 ;
        RECT 345.408 109.728 345.600 109.752 ;
    END
  END u_rank__qm_t_d[62]
  PIN u_rank__qm_t_d[63]
    DIRECTION OUTPUT ;
    USE SIGNAL ;
    PORT
      LAYER M4 ;
        RECT 345.408 109.872 345.600 109.896 ;
    END
  END u_rank__qm_t_d[63]
  PIN u_rank__qm_t_d[6]
    DIRECTION OUTPUT ;
    USE SIGNAL ;
    PORT
      LAYER M4 ;
        RECT 345.408 100.416 345.600 100.440 ;
    END
  END u_rank__qm_t_d[6]
  PIN u_rank__qm_t_d[7]
    DIRECTION OUTPUT ;
    USE SIGNAL ;
    PORT
      LAYER M4 ;
        RECT 345.408 100.560 345.600 100.584 ;
    END
  END u_rank__qm_t_d[7]
  PIN u_rank__qm_t_d[8]
    DIRECTION OUTPUT ;
    USE SIGNAL ;
    PORT
      LAYER M4 ;
        RECT 345.408 100.752 345.600 100.776 ;
    END
  END u_rank__qm_t_d[8]
  PIN u_rank__qm_t_d[9]
    DIRECTION OUTPUT ;
    USE SIGNAL ;
    PORT
      LAYER M4 ;
        RECT 345.408 100.896 345.600 100.920 ;
    END
  END u_rank__qm_t_d[9]
  PIN u_rank__qm_t_v
    DIRECTION OUTPUT ;
    USE SIGNAL ;
    PORT
      LAYER M4 ;
        RECT 345.408 110.064 345.600 110.088 ;
    END
  END u_rank__qm_t_v
  PIN u_rank__qm_v
    DIRECTION INPUT ;
    USE SIGNAL ;
    PORT
      LAYER M4 ;
        RECT 345.408 110.208 345.600 110.232 ;
    END
  END u_rank__qm_v
  PIN VDD
    DIRECTION INOUT ;
    USE POWER ;
    PORT
      LAYER M5 ;
        RECT 2.460 2.151 2.580 343.449 ;
        RECT 7.860 2.151 7.980 343.449 ;
        RECT 13.260 2.151 13.380 343.449 ;
        RECT 18.660 2.151 18.780 343.449 ;
        RECT 24.060 2.151 24.180 343.449 ;
        RECT 29.460 2.151 29.580 343.449 ;
        RECT 34.860 2.151 34.980 343.449 ;
        RECT 40.260 2.151 40.380 343.449 ;
        RECT 45.660 2.151 45.780 343.449 ;
        RECT 51.060 2.151 51.180 343.449 ;
        RECT 56.460 2.151 56.580 343.449 ;
        RECT 61.860 2.151 61.980 343.449 ;
        RECT 67.260 2.151 67.380 343.449 ;
        RECT 72.660 2.151 72.780 343.449 ;
        RECT 78.060 2.151 78.180 343.449 ;
        RECT 83.460 2.151 83.580 343.449 ;
        RECT 88.860 2.151 88.980 343.449 ;
        RECT 94.260 2.151 94.380 343.449 ;
        RECT 99.660 2.151 99.780 343.449 ;
        RECT 105.060 2.151 105.180 343.449 ;
        RECT 110.460 2.151 110.580 343.449 ;
        RECT 115.860 2.151 115.980 343.449 ;
        RECT 121.260 2.151 121.380 343.449 ;
        RECT 126.660 2.151 126.780 343.449 ;
        RECT 132.060 2.151 132.180 343.449 ;
        RECT 137.460 2.151 137.580 343.449 ;
        RECT 142.860 2.151 142.980 343.449 ;
        RECT 148.260 2.151 148.380 343.449 ;
        RECT 153.660 2.151 153.780 343.449 ;
        RECT 159.060 2.151 159.180 343.449 ;
        RECT 164.460 2.151 164.580 343.449 ;
        RECT 169.860 2.151 169.980 343.449 ;
        RECT 175.260 2.151 175.380 343.449 ;
        RECT 180.660 2.151 180.780 343.449 ;
        RECT 186.060 2.151 186.180 343.449 ;
        RECT 191.460 2.151 191.580 343.449 ;
        RECT 196.860 2.151 196.980 343.449 ;
        RECT 202.260 2.151 202.380 343.449 ;
        RECT 207.660 2.151 207.780 343.449 ;
        RECT 213.060 2.151 213.180 343.449 ;
        RECT 218.460 2.151 218.580 343.449 ;
        RECT 223.860 2.151 223.980 343.449 ;
        RECT 229.260 2.151 229.380 343.449 ;
        RECT 234.660 2.151 234.780 343.449 ;
        RECT 240.060 2.151 240.180 343.449 ;
        RECT 245.460 2.151 245.580 343.449 ;
        RECT 250.860 2.151 250.980 343.449 ;
        RECT 256.260 2.151 256.380 343.449 ;
        RECT 261.660 2.151 261.780 343.449 ;
        RECT 267.060 2.151 267.180 343.449 ;
        RECT 272.460 2.151 272.580 343.449 ;
        RECT 277.860 2.151 277.980 343.449 ;
        RECT 283.260 2.151 283.380 343.449 ;
        RECT 288.660 2.151 288.780 343.449 ;
        RECT 294.060 2.151 294.180 343.449 ;
        RECT 299.460 2.151 299.580 343.449 ;
        RECT 304.860 2.151 304.980 343.449 ;
        RECT 310.260 2.151 310.380 343.449 ;
        RECT 315.660 2.151 315.780 343.449 ;
        RECT 321.060 2.151 321.180 343.449 ;
        RECT 326.460 2.151 326.580 343.449 ;
        RECT 331.860 2.151 331.980 343.449 ;
        RECT 337.260 2.151 337.380 343.449 ;
        RECT 342.660 2.151 342.780 343.449 ;
    END
  END VDD
  PIN VSS
    DIRECTION INOUT ;
    USE GROUND ;
    PORT
      LAYER M5 ;
        RECT 2.652 2.151 2.772 343.449 ;
        RECT 8.052 2.151 8.172 343.449 ;
        RECT 13.452 2.151 13.572 343.449 ;
        RECT 18.852 2.151 18.972 343.449 ;
        RECT 24.252 2.151 24.372 343.449 ;
        RECT 29.652 2.151 29.772 343.449 ;
        RECT 35.052 2.151 35.172 343.449 ;
        RECT 40.452 2.151 40.572 343.449 ;
        RECT 45.852 2.151 45.972 343.449 ;
        RECT 51.252 2.151 51.372 343.449 ;
        RECT 56.652 2.151 56.772 343.449 ;
        RECT 62.052 2.151 62.172 343.449 ;
        RECT 67.452 2.151 67.572 343.449 ;
        RECT 72.852 2.151 72.972 343.449 ;
        RECT 78.252 2.151 78.372 343.449 ;
        RECT 83.652 2.151 83.772 343.449 ;
        RECT 89.052 2.151 89.172 343.449 ;
        RECT 94.452 2.151 94.572 343.449 ;
        RECT 99.852 2.151 99.972 343.449 ;
        RECT 105.252 2.151 105.372 343.449 ;
        RECT 110.652 2.151 110.772 343.449 ;
        RECT 116.052 2.151 116.172 343.449 ;
        RECT 121.452 2.151 121.572 343.449 ;
        RECT 126.852 2.151 126.972 343.449 ;
        RECT 132.252 2.151 132.372 343.449 ;
        RECT 137.652 2.151 137.772 343.449 ;
        RECT 143.052 2.151 143.172 343.449 ;
        RECT 148.452 2.151 148.572 343.449 ;
        RECT 153.852 2.151 153.972 343.449 ;
        RECT 159.252 2.151 159.372 343.449 ;
        RECT 164.652 2.151 164.772 343.449 ;
        RECT 170.052 2.151 170.172 343.449 ;
        RECT 175.452 2.151 175.572 343.449 ;
        RECT 180.852 2.151 180.972 343.449 ;
        RECT 186.252 2.151 186.372 343.449 ;
        RECT 191.652 2.151 191.772 343.449 ;
        RECT 197.052 2.151 197.172 343.449 ;
        RECT 202.452 2.151 202.572 343.449 ;
        RECT 207.852 2.151 207.972 343.449 ;
        RECT 213.252 2.151 213.372 343.449 ;
        RECT 218.652 2.151 218.772 343.449 ;
        RECT 224.052 2.151 224.172 343.449 ;
        RECT 229.452 2.151 229.572 343.449 ;
        RECT 234.852 2.151 234.972 343.449 ;
        RECT 240.252 2.151 240.372 343.449 ;
        RECT 245.652 2.151 245.772 343.449 ;
        RECT 251.052 2.151 251.172 343.449 ;
        RECT 256.452 2.151 256.572 343.449 ;
        RECT 261.852 2.151 261.972 343.449 ;
        RECT 267.252 2.151 267.372 343.449 ;
        RECT 272.652 2.151 272.772 343.449 ;
        RECT 278.052 2.151 278.172 343.449 ;
        RECT 283.452 2.151 283.572 343.449 ;
        RECT 288.852 2.151 288.972 343.449 ;
        RECT 294.252 2.151 294.372 343.449 ;
        RECT 299.652 2.151 299.772 343.449 ;
        RECT 305.052 2.151 305.172 343.449 ;
        RECT 310.452 2.151 310.572 343.449 ;
        RECT 315.852 2.151 315.972 343.449 ;
        RECT 321.252 2.151 321.372 343.449 ;
        RECT 326.652 2.151 326.772 343.449 ;
        RECT 332.052 2.151 332.172 343.449 ;
        RECT 337.452 2.151 337.572 343.449 ;
        RECT 342.852 2.151 342.972 343.449 ;
    END
  END VSS
  OBS
    LAYER M1 ;
      RECT 10.800 10.800 334.800 334.800 ;
    LAYER M2 ;
      RECT 10.800 10.800 334.800 334.800 ;
    LAYER M3 ;
      RECT 10.800 10.800 334.800 334.800 ;
    LAYER M4 ;
      RECT 10.800 10.800 334.800 334.800 ;
    LAYER M5 ;
      RECT 10.800 10.800 13.160 334.800 ;
      RECT 13.672 10.800 18.560 334.800 ;
      RECT 19.072 10.800 23.960 334.800 ;
      RECT 24.472 10.800 29.360 334.800 ;
      RECT 29.872 10.800 34.760 334.800 ;
      RECT 35.272 10.800 40.160 334.800 ;
      RECT 40.672 10.800 45.560 334.800 ;
      RECT 46.072 10.800 50.960 334.800 ;
      RECT 51.472 10.800 56.360 334.800 ;
      RECT 56.872 10.800 61.760 334.800 ;
      RECT 62.272 10.800 67.160 334.800 ;
      RECT 67.672 10.800 72.560 334.800 ;
      RECT 73.072 10.800 77.960 334.800 ;
      RECT 78.472 10.800 83.360 334.800 ;
      RECT 83.872 10.800 88.760 334.800 ;
      RECT 89.272 10.800 94.160 334.800 ;
      RECT 94.672 10.800 99.560 334.800 ;
      RECT 100.072 10.800 104.960 334.800 ;
      RECT 105.472 10.800 110.360 334.800 ;
      RECT 110.872 10.800 115.760 334.800 ;
      RECT 116.272 10.800 121.160 334.800 ;
      RECT 121.672 10.800 126.560 334.800 ;
      RECT 127.072 10.800 131.960 334.800 ;
      RECT 132.472 10.800 137.360 334.800 ;
      RECT 137.872 10.800 142.760 334.800 ;
      RECT 143.272 10.800 148.160 334.800 ;
      RECT 148.672 10.800 153.560 334.800 ;
      RECT 154.072 10.800 158.960 334.800 ;
      RECT 159.472 10.800 164.360 334.800 ;
      RECT 164.872 10.800 169.760 334.800 ;
      RECT 170.272 10.800 175.160 334.800 ;
      RECT 175.672 10.800 180.560 334.800 ;
      RECT 181.072 10.800 185.960 334.800 ;
      RECT 186.472 10.800 191.360 334.800 ;
      RECT 191.872 10.800 196.760 334.800 ;
      RECT 197.272 10.800 202.160 334.800 ;
      RECT 202.672 10.800 207.560 334.800 ;
      RECT 208.072 10.800 212.960 334.800 ;
      RECT 213.472 10.800 218.360 334.800 ;
      RECT 218.872 10.800 223.760 334.800 ;
      RECT 224.272 10.800 229.160 334.800 ;
      RECT 229.672 10.800 234.560 334.800 ;
      RECT 235.072 10.800 239.960 334.800 ;
      RECT 240.472 10.800 245.360 334.800 ;
      RECT 245.872 10.800 250.760 334.800 ;
      RECT 251.272 10.800 256.160 334.800 ;
      RECT 256.672 10.800 261.560 334.800 ;
      RECT 262.072 10.800 266.960 334.800 ;
      RECT 267.472 10.800 272.360 334.800 ;
      RECT 272.872 10.800 277.760 334.800 ;
      RECT 278.272 10.800 283.160 334.800 ;
      RECT 283.672 10.800 288.560 334.800 ;
      RECT 289.072 10.800 293.960 334.800 ;
      RECT 294.472 10.800 299.360 334.800 ;
      RECT 299.872 10.800 304.760 334.800 ;
      RECT 305.272 10.800 310.160 334.800 ;
      RECT 310.672 10.800 315.560 334.800 ;
      RECT 316.072 10.800 320.960 334.800 ;
      RECT 321.472 10.800 326.360 334.800 ;
      RECT 326.872 10.800 331.760 334.800 ;
      RECT 332.272 10.800 334.800 334.800 ;
  END
END qkd_hr_ingest_qm
END LIBRARY
